VERSION 5.8 ;
BUSBITCHARS "[]" ;
DIVIDERCHAR "/" ;
UNITS
    DATABASE MICRONS 1000 ;
END UNITS

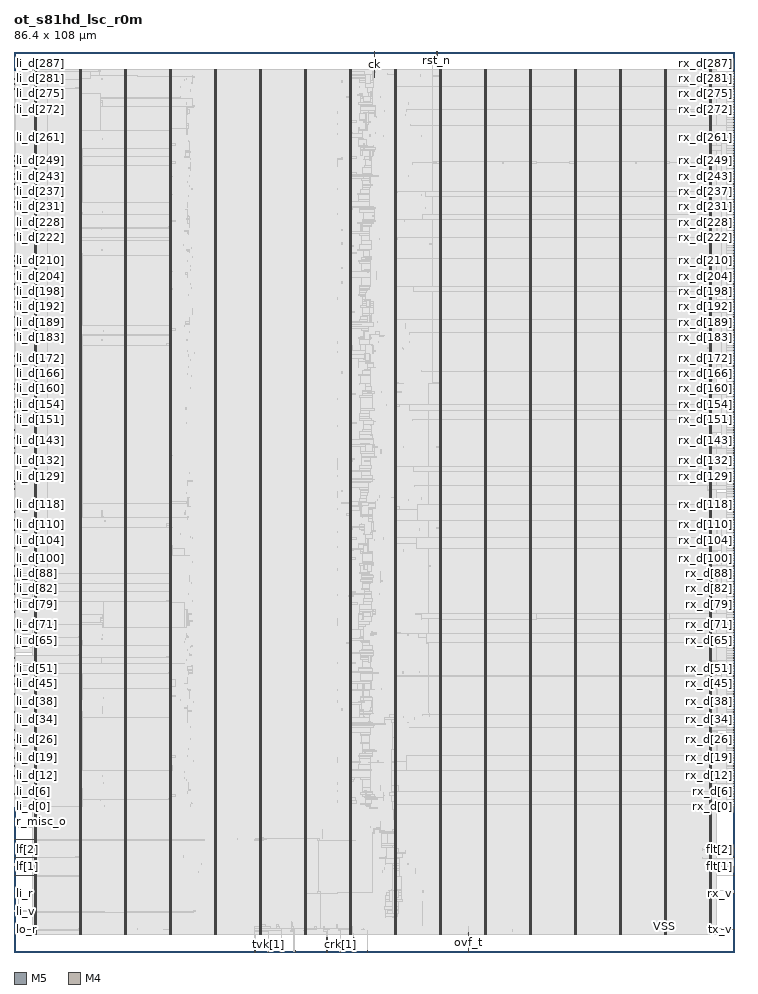
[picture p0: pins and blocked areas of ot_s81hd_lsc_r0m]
MACRO ot_s81hd_lsc_r0m
  FOREIGN ot_s81hd_lsc_r0m 0 0 ;
  CLASS BLOCK ;
  SIZE 86.4 BY 108 ;
  PIN ck
    DIRECTION INPUT ;
    USE SIGNAL ;
    PORT
      LAYER M5 ;
        RECT  43.2 107.916 43.224 108 ;
    END
    PORT
      LAYER M5 ;
        RECT  43.2 104.915 43.224 107.984 ;
    END
  END ck
  PIN crk[0]
    DIRECTION OUTPUT ;
    USE SIGNAL ;
    PORT
      LAYER M5 ;
        RECT  37.536 0 37.56 0.084 ;
    END
    PORT
      LAYER M5 ;
        RECT  37.536 0.016 37.56 1.763 ;
    END
  END crk[0]
  PIN crk[1]
    DIRECTION OUTPUT ;
    USE SIGNAL ;
    PORT
      LAYER M5 ;
        RECT  39.12 0 39.144 0.084 ;
    END
    PORT
      LAYER M5 ;
        RECT  39.12 0.016 39.144 0.131 ;
    END
  END crk[1]
  PIN crk[2]
    DIRECTION OUTPUT ;
    USE SIGNAL ;
    PORT
      LAYER M5 ;
        RECT  40.752 0 40.776 0.084 ;
    END
    PORT
      LAYER M5 ;
        RECT  40.752 0.016 40.776 1.763 ;
    END
  END crk[2]
  PIN crk[3]
    DIRECTION OUTPUT ;
    USE SIGNAL ;
    PORT
      LAYER M5 ;
        RECT  42.384 0 42.408 0.084 ;
    END
    PORT
      LAYER M5 ;
        RECT  42.384 0.016 42.408 0.131 ;
    END
  END crk[3]
  PIN flt[0]
    DIRECTION OUTPUT ;
    USE SIGNAL ;
    PORT
      LAYER M4 ;
        RECT  86.316 9.168 86.4 9.192 ;
    END
    PORT
      LAYER M4 ;
        RECT  86.281 9.168 86.364 9.192 ;
    END
  END flt[0]
  PIN flt[1]
    DIRECTION OUTPUT ;
    USE SIGNAL ;
    PORT
      LAYER M4 ;
        RECT  86.316 10.272 86.4 10.296 ;
    END
    PORT
      LAYER M4 ;
        RECT  86.321 10.272 86.364 10.296 ;
    END
  END flt[1]
  PIN flt[2]
    DIRECTION OUTPUT ;
    USE SIGNAL ;
    PORT
      LAYER M4 ;
        RECT  86.316 11.328 86.4 11.352 ;
    END
    PORT
      LAYER M4 ;
        RECT  86.321 11.328 86.364 11.352 ;
    END
  END flt[2]
  PIN flt[3]
    DIRECTION OUTPUT ;
    USE SIGNAL ;
    PORT
      LAYER M4 ;
        RECT  86.316 12.432 86.4 12.456 ;
    END
    PORT
      LAYER M4 ;
        RECT  83.704 12.432 86.364 12.456 ;
    END
  END flt[3]
  PIN lf[0]
    DIRECTION INPUT ;
    USE SIGNAL ;
    PORT
      LAYER M4 ;
        RECT  0 9.168 0.084 9.192 ;
    END
    PORT
      LAYER M4 ;
        RECT  0.06 9.168 2.408 9.192 ;
    END
  END lf[0]
  PIN lf[1]
    DIRECTION INPUT ;
    USE SIGNAL ;
    PORT
      LAYER M4 ;
        RECT  0 10.272 0.084 10.296 ;
    END
    PORT
      LAYER M4 ;
        RECT  0.06 10.272 0.137 10.296 ;
    END
  END lf[1]
  PIN lf[2]
    DIRECTION INPUT ;
    USE SIGNAL ;
    PORT
      LAYER M4 ;
        RECT  0 11.328 0.084 11.352 ;
    END
    PORT
      LAYER M4 ;
        RECT  0.06 11.328 2.408 11.352 ;
    END
  END lf[2]
  PIN li_d[0]
    DIRECTION INPUT ;
    USE SIGNAL ;
    PORT
      LAYER M4 ;
        RECT  0 17.424 0.084 17.448 ;
    END
  END li_d[0]
  PIN li_d[100]
    DIRECTION INPUT ;
    USE SIGNAL ;
    PORT
      LAYER M4 ;
        RECT  0 48.192 0.084 48.216 ;
    END
  END li_d[100]
  PIN li_d[101]
    DIRECTION INPUT ;
    USE SIGNAL ;
    PORT
      LAYER M4 ;
        RECT  0 48.48 0.084 48.504 ;
    END
  END li_d[101]
  PIN li_d[102]
    DIRECTION INPUT ;
    USE SIGNAL ;
    PORT
      LAYER M4 ;
        RECT  0 48.768 0.084 48.792 ;
    END
  END li_d[102]
  PIN li_d[103]
    DIRECTION INPUT ;
    USE SIGNAL ;
    PORT
      LAYER M4 ;
        RECT  0 49.104 0.084 49.128 ;
    END
  END li_d[103]
  PIN li_d[104]
    DIRECTION INPUT ;
    USE SIGNAL ;
    PORT
      LAYER M4 ;
        RECT  0 49.392 0.084 49.416 ;
    END
  END li_d[104]
  PIN li_d[105]
    DIRECTION INPUT ;
    USE SIGNAL ;
    PORT
      LAYER M4 ;
        RECT  0 49.728 0.084 49.752 ;
    END
  END li_d[105]
  PIN li_d[106]
    DIRECTION INPUT ;
    USE SIGNAL ;
    PORT
      LAYER M4 ;
        RECT  0 50.016 0.084 50.04 ;
    END
  END li_d[106]
  PIN li_d[107]
    DIRECTION INPUT ;
    USE SIGNAL ;
    PORT
      LAYER M4 ;
        RECT  0 50.304 0.084 50.328 ;
    END
  END li_d[107]
  PIN li_d[108]
    DIRECTION INPUT ;
    USE SIGNAL ;
    PORT
      LAYER M4 ;
        RECT  0 50.64 0.084 50.664 ;
    END
  END li_d[108]
  PIN li_d[109]
    DIRECTION INPUT ;
    USE SIGNAL ;
    PORT
      LAYER M4 ;
        RECT  0 50.928 0.084 50.952 ;
    END
  END li_d[109]
  PIN li_d[10]
    DIRECTION INPUT ;
    USE SIGNAL ;
    PORT
      LAYER M4 ;
        RECT  0 20.496 0.084 20.52 ;
    END
  END li_d[10]
  PIN li_d[110]
    DIRECTION INPUT ;
    USE SIGNAL ;
    PORT
      LAYER M4 ;
        RECT  0 51.264 0.084 51.288 ;
    END
  END li_d[110]
  PIN li_d[111]
    DIRECTION INPUT ;
    USE SIGNAL ;
    PORT
      LAYER M4 ;
        RECT  0 51.552 0.084 51.576 ;
    END
  END li_d[111]
  PIN li_d[112]
    DIRECTION INPUT ;
    USE SIGNAL ;
    PORT
      LAYER M4 ;
        RECT  0 51.84 0.084 51.864 ;
    END
  END li_d[112]
  PIN li_d[113]
    DIRECTION INPUT ;
    USE SIGNAL ;
    PORT
      LAYER M4 ;
        RECT  0 52.176 0.084 52.2 ;
    END
  END li_d[113]
  PIN li_d[114]
    DIRECTION INPUT ;
    USE SIGNAL ;
    PORT
      LAYER M4 ;
        RECT  0 52.464 0.084 52.488 ;
    END
  END li_d[114]
  PIN li_d[115]
    DIRECTION INPUT ;
    USE SIGNAL ;
    PORT
      LAYER M4 ;
        RECT  0 52.8 0.084 52.824 ;
    END
  END li_d[115]
  PIN li_d[116]
    DIRECTION INPUT ;
    USE SIGNAL ;
    PORT
      LAYER M4 ;
        RECT  0 53.088 0.084 53.112 ;
    END
  END li_d[116]
  PIN li_d[117]
    DIRECTION INPUT ;
    USE SIGNAL ;
    PORT
      LAYER M4 ;
        RECT  0 53.376 0.084 53.4 ;
    END
  END li_d[117]
  PIN li_d[118]
    DIRECTION INPUT ;
    USE SIGNAL ;
    PORT
      LAYER M4 ;
        RECT  0 53.712 0.084 53.736 ;
    END
  END li_d[118]
  PIN li_d[119]
    DIRECTION INPUT ;
    USE SIGNAL ;
    PORT
      LAYER M4 ;
        RECT  0 54 0.084 54.024 ;
    END
  END li_d[119]
  PIN li_d[11]
    DIRECTION INPUT ;
    USE SIGNAL ;
    PORT
      LAYER M4 ;
        RECT  0 20.784 0.084 20.808 ;
    END
  END li_d[11]
  PIN li_d[120]
    DIRECTION INPUT ;
    USE SIGNAL ;
    PORT
      LAYER M4 ;
        RECT  0 54.336 0.084 54.36 ;
    END
  END li_d[120]
  PIN li_d[121]
    DIRECTION INPUT ;
    USE SIGNAL ;
    PORT
      LAYER M4 ;
        RECT  0 54.624 0.084 54.648 ;
    END
  END li_d[121]
  PIN li_d[122]
    DIRECTION INPUT ;
    USE SIGNAL ;
    PORT
      LAYER M4 ;
        RECT  0 54.96 0.084 54.984 ;
    END
  END li_d[122]
  PIN li_d[123]
    DIRECTION INPUT ;
    USE SIGNAL ;
    PORT
      LAYER M4 ;
        RECT  0 55.248 0.084 55.272 ;
    END
  END li_d[123]
  PIN li_d[124]
    DIRECTION INPUT ;
    USE SIGNAL ;
    PORT
      LAYER M4 ;
        RECT  0 55.536 0.084 55.56 ;
    END
  END li_d[124]
  PIN li_d[125]
    DIRECTION INPUT ;
    USE SIGNAL ;
    PORT
      LAYER M4 ;
        RECT  0 55.872 0.084 55.896 ;
    END
  END li_d[125]
  PIN li_d[126]
    DIRECTION INPUT ;
    USE SIGNAL ;
    PORT
      LAYER M4 ;
        RECT  0 56.16 0.084 56.184 ;
    END
  END li_d[126]
  PIN li_d[127]
    DIRECTION INPUT ;
    USE SIGNAL ;
    PORT
      LAYER M4 ;
        RECT  0 56.496 0.084 56.52 ;
    END
  END li_d[127]
  PIN li_d[128]
    DIRECTION INPUT ;
    USE SIGNAL ;
    PORT
      LAYER M4 ;
        RECT  0 56.784 0.084 56.808 ;
    END
  END li_d[128]
  PIN li_d[129]
    DIRECTION INPUT ;
    USE SIGNAL ;
    PORT
      LAYER M4 ;
        RECT  0 57.072 0.084 57.096 ;
    END
  END li_d[129]
  PIN li_d[12]
    DIRECTION INPUT ;
    USE SIGNAL ;
    PORT
      LAYER M4 ;
        RECT  0 21.12 0.084 21.144 ;
    END
  END li_d[12]
  PIN li_d[130]
    DIRECTION INPUT ;
    USE SIGNAL ;
    PORT
      LAYER M4 ;
        RECT  0 57.408 0.084 57.432 ;
    END
  END li_d[130]
  PIN li_d[131]
    DIRECTION INPUT ;
    USE SIGNAL ;
    PORT
      LAYER M4 ;
        RECT  0 57.696 0.084 57.72 ;
    END
  END li_d[131]
  PIN li_d[132]
    DIRECTION INPUT ;
    USE SIGNAL ;
    PORT
      LAYER M4 ;
        RECT  0 58.032 0.084 58.056 ;
    END
  END li_d[132]
  PIN li_d[133]
    DIRECTION INPUT ;
    USE SIGNAL ;
    PORT
      LAYER M4 ;
        RECT  0 58.32 0.084 58.344 ;
    END
  END li_d[133]
  PIN li_d[134]
    DIRECTION INPUT ;
    USE SIGNAL ;
    PORT
      LAYER M4 ;
        RECT  0 58.608 0.084 58.632 ;
    END
  END li_d[134]
  PIN li_d[135]
    DIRECTION INPUT ;
    USE SIGNAL ;
    PORT
      LAYER M4 ;
        RECT  0 58.944 0.084 58.968 ;
    END
  END li_d[135]
  PIN li_d[136]
    DIRECTION INPUT ;
    USE SIGNAL ;
    PORT
      LAYER M4 ;
        RECT  0 59.232 0.084 59.256 ;
    END
  END li_d[136]
  PIN li_d[137]
    DIRECTION INPUT ;
    USE SIGNAL ;
    PORT
      LAYER M4 ;
        RECT  0 59.568 0.084 59.592 ;
    END
  END li_d[137]
  PIN li_d[138]
    DIRECTION INPUT ;
    USE SIGNAL ;
    PORT
      LAYER M4 ;
        RECT  0 59.856 0.084 59.88 ;
    END
  END li_d[138]
  PIN li_d[139]
    DIRECTION INPUT ;
    USE SIGNAL ;
    PORT
      LAYER M4 ;
        RECT  0 60.144 0.084 60.168 ;
    END
  END li_d[139]
  PIN li_d[13]
    DIRECTION INPUT ;
    USE SIGNAL ;
    PORT
      LAYER M4 ;
        RECT  0 21.408 0.084 21.432 ;
    END
  END li_d[13]
  PIN li_d[140]
    DIRECTION INPUT ;
    USE SIGNAL ;
    PORT
      LAYER M4 ;
        RECT  0 60.48 0.084 60.504 ;
    END
  END li_d[140]
  PIN li_d[141]
    DIRECTION INPUT ;
    USE SIGNAL ;
    PORT
      LAYER M4 ;
        RECT  0 60.768 0.084 60.792 ;
    END
  END li_d[141]
  PIN li_d[142]
    DIRECTION INPUT ;
    USE SIGNAL ;
    PORT
      LAYER M4 ;
        RECT  0 61.104 0.084 61.128 ;
    END
  END li_d[142]
  PIN li_d[143]
    DIRECTION INPUT ;
    USE SIGNAL ;
    PORT
      LAYER M4 ;
        RECT  0 61.392 0.084 61.416 ;
    END
  END li_d[143]
  PIN li_d[144]
    DIRECTION INPUT ;
    USE SIGNAL ;
    PORT
      LAYER M4 ;
        RECT  0 61.68 0.084 61.704 ;
    END
  END li_d[144]
  PIN li_d[145]
    DIRECTION INPUT ;
    USE SIGNAL ;
    PORT
      LAYER M4 ;
        RECT  0 62.016 0.084 62.04 ;
    END
  END li_d[145]
  PIN li_d[146]
    DIRECTION INPUT ;
    USE SIGNAL ;
    PORT
      LAYER M4 ;
        RECT  0 62.304 0.084 62.328 ;
    END
  END li_d[146]
  PIN li_d[147]
    DIRECTION INPUT ;
    USE SIGNAL ;
    PORT
      LAYER M4 ;
        RECT  0 62.64 0.084 62.664 ;
    END
  END li_d[147]
  PIN li_d[148]
    DIRECTION INPUT ;
    USE SIGNAL ;
    PORT
      LAYER M4 ;
        RECT  0 62.928 0.084 62.952 ;
    END
  END li_d[148]
  PIN li_d[149]
    DIRECTION INPUT ;
    USE SIGNAL ;
    PORT
      LAYER M4 ;
        RECT  0 63.216 0.084 63.24 ;
    END
  END li_d[149]
  PIN li_d[14]
    DIRECTION INPUT ;
    USE SIGNAL ;
    PORT
      LAYER M4 ;
        RECT  0 21.744 0.084 21.768 ;
    END
  END li_d[14]
  PIN li_d[150]
    DIRECTION INPUT ;
    USE SIGNAL ;
    PORT
      LAYER M4 ;
        RECT  0 63.552 0.084 63.576 ;
    END
  END li_d[150]
  PIN li_d[151]
    DIRECTION INPUT ;
    USE SIGNAL ;
    PORT
      LAYER M4 ;
        RECT  0 63.84 0.084 63.864 ;
    END
  END li_d[151]
  PIN li_d[152]
    DIRECTION INPUT ;
    USE SIGNAL ;
    PORT
      LAYER M4 ;
        RECT  0 64.176 0.084 64.2 ;
    END
  END li_d[152]
  PIN li_d[153]
    DIRECTION INPUT ;
    USE SIGNAL ;
    PORT
      LAYER M4 ;
        RECT  0 64.464 0.084 64.488 ;
    END
  END li_d[153]
  PIN li_d[154]
    DIRECTION INPUT ;
    USE SIGNAL ;
    PORT
      LAYER M4 ;
        RECT  0 64.8 0.084 64.824 ;
    END
  END li_d[154]
  PIN li_d[155]
    DIRECTION INPUT ;
    USE SIGNAL ;
    PORT
      LAYER M4 ;
        RECT  0 65.088 0.084 65.112 ;
    END
  END li_d[155]
  PIN li_d[156]
    DIRECTION INPUT ;
    USE SIGNAL ;
    PORT
      LAYER M4 ;
        RECT  0 65.376 0.084 65.4 ;
    END
  END li_d[156]
  PIN li_d[157]
    DIRECTION INPUT ;
    USE SIGNAL ;
    PORT
      LAYER M4 ;
        RECT  0 65.712 0.084 65.736 ;
    END
  END li_d[157]
  PIN li_d[158]
    DIRECTION INPUT ;
    USE SIGNAL ;
    PORT
      LAYER M4 ;
        RECT  0 66 0.084 66.024 ;
    END
  END li_d[158]
  PIN li_d[159]
    DIRECTION INPUT ;
    USE SIGNAL ;
    PORT
      LAYER M4 ;
        RECT  0 66.336 0.084 66.36 ;
    END
  END li_d[159]
  PIN li_d[15]
    DIRECTION INPUT ;
    USE SIGNAL ;
    PORT
      LAYER M4 ;
        RECT  0 22.032 0.084 22.056 ;
    END
  END li_d[15]
  PIN li_d[160]
    DIRECTION INPUT ;
    USE SIGNAL ;
    PORT
      LAYER M4 ;
        RECT  0 66.624 0.084 66.648 ;
    END
  END li_d[160]
  PIN li_d[161]
    DIRECTION INPUT ;
    USE SIGNAL ;
    PORT
      LAYER M4 ;
        RECT  0 66.912 0.084 66.936 ;
    END
  END li_d[161]
  PIN li_d[162]
    DIRECTION INPUT ;
    USE SIGNAL ;
    PORT
      LAYER M4 ;
        RECT  0 67.248 0.084 67.272 ;
    END
  END li_d[162]
  PIN li_d[163]
    DIRECTION INPUT ;
    USE SIGNAL ;
    PORT
      LAYER M4 ;
        RECT  0 67.536 0.084 67.56 ;
    END
  END li_d[163]
  PIN li_d[164]
    DIRECTION INPUT ;
    USE SIGNAL ;
    PORT
      LAYER M4 ;
        RECT  0 67.872 0.084 67.896 ;
    END
  END li_d[164]
  PIN li_d[165]
    DIRECTION INPUT ;
    USE SIGNAL ;
    PORT
      LAYER M4 ;
        RECT  0 68.16 0.084 68.184 ;
    END
  END li_d[165]
  PIN li_d[166]
    DIRECTION INPUT ;
    USE SIGNAL ;
    PORT
      LAYER M4 ;
        RECT  0 68.448 0.084 68.472 ;
    END
  END li_d[166]
  PIN li_d[167]
    DIRECTION INPUT ;
    USE SIGNAL ;
    PORT
      LAYER M4 ;
        RECT  0 68.784 0.084 68.808 ;
    END
  END li_d[167]
  PIN li_d[168]
    DIRECTION INPUT ;
    USE SIGNAL ;
    PORT
      LAYER M4 ;
        RECT  0 69.072 0.084 69.096 ;
    END
  END li_d[168]
  PIN li_d[169]
    DIRECTION INPUT ;
    USE SIGNAL ;
    PORT
      LAYER M4 ;
        RECT  0 69.408 0.084 69.432 ;
    END
  END li_d[169]
  PIN li_d[16]
    DIRECTION INPUT ;
    USE SIGNAL ;
    PORT
      LAYER M4 ;
        RECT  0 22.32 0.084 22.344 ;
    END
  END li_d[16]
  PIN li_d[170]
    DIRECTION INPUT ;
    USE SIGNAL ;
    PORT
      LAYER M4 ;
        RECT  0 69.696 0.084 69.72 ;
    END
  END li_d[170]
  PIN li_d[171]
    DIRECTION INPUT ;
    USE SIGNAL ;
    PORT
      LAYER M4 ;
        RECT  0 69.984 0.084 70.008 ;
    END
  END li_d[171]
  PIN li_d[172]
    DIRECTION INPUT ;
    USE SIGNAL ;
    PORT
      LAYER M4 ;
        RECT  0 70.32 0.084 70.344 ;
    END
  END li_d[172]
  PIN li_d[173]
    DIRECTION INPUT ;
    USE SIGNAL ;
    PORT
      LAYER M4 ;
        RECT  0 70.608 0.084 70.632 ;
    END
  END li_d[173]
  PIN li_d[174]
    DIRECTION INPUT ;
    USE SIGNAL ;
    PORT
      LAYER M4 ;
        RECT  0 70.944 0.084 70.968 ;
    END
  END li_d[174]
  PIN li_d[175]
    DIRECTION INPUT ;
    USE SIGNAL ;
    PORT
      LAYER M4 ;
        RECT  0 71.232 0.084 71.256 ;
    END
  END li_d[175]
  PIN li_d[176]
    DIRECTION INPUT ;
    USE SIGNAL ;
    PORT
      LAYER M4 ;
        RECT  0 71.52 0.084 71.544 ;
    END
  END li_d[176]
  PIN li_d[177]
    DIRECTION INPUT ;
    USE SIGNAL ;
    PORT
      LAYER M4 ;
        RECT  0 71.856 0.084 71.88 ;
    END
  END li_d[177]
  PIN li_d[178]
    DIRECTION INPUT ;
    USE SIGNAL ;
    PORT
      LAYER M4 ;
        RECT  0 72.144 0.084 72.168 ;
    END
  END li_d[178]
  PIN li_d[179]
    DIRECTION INPUT ;
    USE SIGNAL ;
    PORT
      LAYER M4 ;
        RECT  0 72.48 0.084 72.504 ;
    END
  END li_d[179]
  PIN li_d[17]
    DIRECTION INPUT ;
    USE SIGNAL ;
    PORT
      LAYER M4 ;
        RECT  0 22.656 0.084 22.68 ;
    END
  END li_d[17]
  PIN li_d[180]
    DIRECTION INPUT ;
    USE SIGNAL ;
    PORT
      LAYER M4 ;
        RECT  0 72.768 0.084 72.792 ;
    END
  END li_d[180]
  PIN li_d[181]
    DIRECTION INPUT ;
    USE SIGNAL ;
    PORT
      LAYER M4 ;
        RECT  0 73.056 0.084 73.08 ;
    END
  END li_d[181]
  PIN li_d[182]
    DIRECTION INPUT ;
    USE SIGNAL ;
    PORT
      LAYER M4 ;
        RECT  0 73.392 0.084 73.416 ;
    END
  END li_d[182]
  PIN li_d[183]
    DIRECTION INPUT ;
    USE SIGNAL ;
    PORT
      LAYER M4 ;
        RECT  0 73.68 0.084 73.704 ;
    END
  END li_d[183]
  PIN li_d[184]
    DIRECTION INPUT ;
    USE SIGNAL ;
    PORT
      LAYER M4 ;
        RECT  0 74.016 0.084 74.04 ;
    END
  END li_d[184]
  PIN li_d[185]
    DIRECTION INPUT ;
    USE SIGNAL ;
    PORT
      LAYER M4 ;
        RECT  0 74.304 0.084 74.328 ;
    END
  END li_d[185]
  PIN li_d[186]
    DIRECTION INPUT ;
    USE SIGNAL ;
    PORT
      LAYER M4 ;
        RECT  0 74.64 0.084 74.664 ;
    END
  END li_d[186]
  PIN li_d[187]
    DIRECTION INPUT ;
    USE SIGNAL ;
    PORT
      LAYER M4 ;
        RECT  0 74.928 0.084 74.952 ;
    END
  END li_d[187]
  PIN li_d[188]
    DIRECTION INPUT ;
    USE SIGNAL ;
    PORT
      LAYER M4 ;
        RECT  0 75.216 0.084 75.24 ;
    END
  END li_d[188]
  PIN li_d[189]
    DIRECTION INPUT ;
    USE SIGNAL ;
    PORT
      LAYER M4 ;
        RECT  0 75.552 0.084 75.576 ;
    END
  END li_d[189]
  PIN li_d[18]
    DIRECTION INPUT ;
    USE SIGNAL ;
    PORT
      LAYER M4 ;
        RECT  0 22.944 0.084 22.968 ;
    END
  END li_d[18]
  PIN li_d[190]
    DIRECTION INPUT ;
    USE SIGNAL ;
    PORT
      LAYER M4 ;
        RECT  0 75.84 0.084 75.864 ;
    END
  END li_d[190]
  PIN li_d[191]
    DIRECTION INPUT ;
    USE SIGNAL ;
    PORT
      LAYER M4 ;
        RECT  0 76.176 0.084 76.2 ;
    END
  END li_d[191]
  PIN li_d[192]
    DIRECTION INPUT ;
    USE SIGNAL ;
    PORT
      LAYER M4 ;
        RECT  0 76.464 0.084 76.488 ;
    END
  END li_d[192]
  PIN li_d[193]
    DIRECTION INPUT ;
    USE SIGNAL ;
    PORT
      LAYER M4 ;
        RECT  0 76.752 0.084 76.776 ;
    END
  END li_d[193]
  PIN li_d[194]
    DIRECTION INPUT ;
    USE SIGNAL ;
    PORT
      LAYER M4 ;
        RECT  0 77.088 0.084 77.112 ;
    END
  END li_d[194]
  PIN li_d[195]
    DIRECTION INPUT ;
    USE SIGNAL ;
    PORT
      LAYER M4 ;
        RECT  0 77.376 0.084 77.4 ;
    END
  END li_d[195]
  PIN li_d[196]
    DIRECTION INPUT ;
    USE SIGNAL ;
    PORT
      LAYER M4 ;
        RECT  0 77.712 0.084 77.736 ;
    END
  END li_d[196]
  PIN li_d[197]
    DIRECTION INPUT ;
    USE SIGNAL ;
    PORT
      LAYER M4 ;
        RECT  0 78 0.084 78.024 ;
    END
  END li_d[197]
  PIN li_d[198]
    DIRECTION INPUT ;
    USE SIGNAL ;
    PORT
      LAYER M4 ;
        RECT  0 78.288 0.084 78.312 ;
    END
  END li_d[198]
  PIN li_d[199]
    DIRECTION INPUT ;
    USE SIGNAL ;
    PORT
      LAYER M4 ;
        RECT  0 78.624 0.084 78.648 ;
    END
  END li_d[199]
  PIN li_d[19]
    DIRECTION INPUT ;
    USE SIGNAL ;
    PORT
      LAYER M4 ;
        RECT  0 23.28 0.084 23.304 ;
    END
  END li_d[19]
  PIN li_d[1]
    DIRECTION INPUT ;
    USE SIGNAL ;
    PORT
      LAYER M4 ;
        RECT  0 17.712 0.084 17.736 ;
    END
  END li_d[1]
  PIN li_d[200]
    DIRECTION INPUT ;
    USE SIGNAL ;
    PORT
      LAYER M4 ;
        RECT  0 78.912 0.084 78.936 ;
    END
  END li_d[200]
  PIN li_d[201]
    DIRECTION INPUT ;
    USE SIGNAL ;
    PORT
      LAYER M4 ;
        RECT  0 79.248 0.084 79.272 ;
    END
  END li_d[201]
  PIN li_d[202]
    DIRECTION INPUT ;
    USE SIGNAL ;
    PORT
      LAYER M4 ;
        RECT  0 79.536 0.084 79.56 ;
    END
  END li_d[202]
  PIN li_d[203]
    DIRECTION INPUT ;
    USE SIGNAL ;
    PORT
      LAYER M4 ;
        RECT  0 79.824 0.084 79.848 ;
    END
  END li_d[203]
  PIN li_d[204]
    DIRECTION INPUT ;
    USE SIGNAL ;
    PORT
      LAYER M4 ;
        RECT  0 80.16 0.084 80.184 ;
    END
  END li_d[204]
  PIN li_d[205]
    DIRECTION INPUT ;
    USE SIGNAL ;
    PORT
      LAYER M4 ;
        RECT  0 80.448 0.084 80.472 ;
    END
  END li_d[205]
  PIN li_d[206]
    DIRECTION INPUT ;
    USE SIGNAL ;
    PORT
      LAYER M4 ;
        RECT  0 80.784 0.084 80.808 ;
    END
  END li_d[206]
  PIN li_d[207]
    DIRECTION INPUT ;
    USE SIGNAL ;
    PORT
      LAYER M4 ;
        RECT  0 81.072 0.084 81.096 ;
    END
  END li_d[207]
  PIN li_d[208]
    DIRECTION INPUT ;
    USE SIGNAL ;
    PORT
      LAYER M4 ;
        RECT  0 81.36 0.084 81.384 ;
    END
  END li_d[208]
  PIN li_d[209]
    DIRECTION INPUT ;
    USE SIGNAL ;
    PORT
      LAYER M4 ;
        RECT  0 81.696 0.084 81.72 ;
    END
  END li_d[209]
  PIN li_d[20]
    DIRECTION INPUT ;
    USE SIGNAL ;
    PORT
      LAYER M4 ;
        RECT  0 23.568 0.084 23.592 ;
    END
  END li_d[20]
  PIN li_d[210]
    DIRECTION INPUT ;
    USE SIGNAL ;
    PORT
      LAYER M4 ;
        RECT  0 81.984 0.084 82.008 ;
    END
  END li_d[210]
  PIN li_d[211]
    DIRECTION INPUT ;
    USE SIGNAL ;
    PORT
      LAYER M4 ;
        RECT  0 82.32 0.084 82.344 ;
    END
  END li_d[211]
  PIN li_d[212]
    DIRECTION INPUT ;
    USE SIGNAL ;
    PORT
      LAYER M4 ;
        RECT  0 82.608 0.084 82.632 ;
    END
  END li_d[212]
  PIN li_d[213]
    DIRECTION INPUT ;
    USE SIGNAL ;
    PORT
      LAYER M4 ;
        RECT  0 82.896 0.084 82.92 ;
    END
  END li_d[213]
  PIN li_d[214]
    DIRECTION INPUT ;
    USE SIGNAL ;
    PORT
      LAYER M4 ;
        RECT  0 83.232 0.084 83.256 ;
    END
  END li_d[214]
  PIN li_d[215]
    DIRECTION INPUT ;
    USE SIGNAL ;
    PORT
      LAYER M4 ;
        RECT  0 83.52 0.084 83.544 ;
    END
  END li_d[215]
  PIN li_d[216]
    DIRECTION INPUT ;
    USE SIGNAL ;
    PORT
      LAYER M4 ;
        RECT  0 83.856 0.084 83.88 ;
    END
  END li_d[216]
  PIN li_d[217]
    DIRECTION INPUT ;
    USE SIGNAL ;
    PORT
      LAYER M4 ;
        RECT  0 84.144 0.084 84.168 ;
    END
  END li_d[217]
  PIN li_d[218]
    DIRECTION INPUT ;
    USE SIGNAL ;
    PORT
      LAYER M4 ;
        RECT  0 84.48 0.084 84.504 ;
    END
  END li_d[218]
  PIN li_d[219]
    DIRECTION INPUT ;
    USE SIGNAL ;
    PORT
      LAYER M4 ;
        RECT  0 84.768 0.084 84.792 ;
    END
  END li_d[219]
  PIN li_d[21]
    DIRECTION INPUT ;
    USE SIGNAL ;
    PORT
      LAYER M4 ;
        RECT  0 23.856 0.084 23.88 ;
    END
  END li_d[21]
  PIN li_d[220]
    DIRECTION INPUT ;
    USE SIGNAL ;
    PORT
      LAYER M4 ;
        RECT  0 85.056 0.084 85.08 ;
    END
  END li_d[220]
  PIN li_d[221]
    DIRECTION INPUT ;
    USE SIGNAL ;
    PORT
      LAYER M4 ;
        RECT  0 85.392 0.084 85.416 ;
    END
  END li_d[221]
  PIN li_d[222]
    DIRECTION INPUT ;
    USE SIGNAL ;
    PORT
      LAYER M4 ;
        RECT  0 85.68 0.084 85.704 ;
    END
  END li_d[222]
  PIN li_d[223]
    DIRECTION INPUT ;
    USE SIGNAL ;
    PORT
      LAYER M4 ;
        RECT  0 86.016 0.084 86.04 ;
    END
  END li_d[223]
  PIN li_d[224]
    DIRECTION INPUT ;
    USE SIGNAL ;
    PORT
      LAYER M4 ;
        RECT  0 86.304 0.084 86.328 ;
    END
  END li_d[224]
  PIN li_d[225]
    DIRECTION INPUT ;
    USE SIGNAL ;
    PORT
      LAYER M4 ;
        RECT  0 86.592 0.084 86.616 ;
    END
  END li_d[225]
  PIN li_d[226]
    DIRECTION INPUT ;
    USE SIGNAL ;
    PORT
      LAYER M4 ;
        RECT  0 86.928 0.084 86.952 ;
    END
  END li_d[226]
  PIN li_d[227]
    DIRECTION INPUT ;
    USE SIGNAL ;
    PORT
      LAYER M4 ;
        RECT  0 87.216 0.084 87.24 ;
    END
  END li_d[227]
  PIN li_d[228]
    DIRECTION INPUT ;
    USE SIGNAL ;
    PORT
      LAYER M4 ;
        RECT  0 87.552 0.084 87.576 ;
    END
  END li_d[228]
  PIN li_d[229]
    DIRECTION INPUT ;
    USE SIGNAL ;
    PORT
      LAYER M4 ;
        RECT  0 87.84 0.084 87.864 ;
    END
  END li_d[229]
  PIN li_d[22]
    DIRECTION INPUT ;
    USE SIGNAL ;
    PORT
      LAYER M4 ;
        RECT  0 24.192 0.084 24.216 ;
    END
  END li_d[22]
  PIN li_d[230]
    DIRECTION INPUT ;
    USE SIGNAL ;
    PORT
      LAYER M4 ;
        RECT  0 88.128 0.084 88.152 ;
    END
  END li_d[230]
  PIN li_d[231]
    DIRECTION INPUT ;
    USE SIGNAL ;
    PORT
      LAYER M4 ;
        RECT  0 88.464 0.084 88.488 ;
    END
  END li_d[231]
  PIN li_d[232]
    DIRECTION INPUT ;
    USE SIGNAL ;
    PORT
      LAYER M4 ;
        RECT  0 88.752 0.084 88.776 ;
    END
  END li_d[232]
  PIN li_d[233]
    DIRECTION INPUT ;
    USE SIGNAL ;
    PORT
      LAYER M4 ;
        RECT  0 89.088 0.084 89.112 ;
    END
  END li_d[233]
  PIN li_d[234]
    DIRECTION INPUT ;
    USE SIGNAL ;
    PORT
      LAYER M4 ;
        RECT  0 89.376 0.084 89.4 ;
    END
  END li_d[234]
  PIN li_d[235]
    DIRECTION INPUT ;
    USE SIGNAL ;
    PORT
      LAYER M4 ;
        RECT  0 89.664 0.084 89.688 ;
    END
  END li_d[235]
  PIN li_d[236]
    DIRECTION INPUT ;
    USE SIGNAL ;
    PORT
      LAYER M4 ;
        RECT  0 90 0.084 90.024 ;
    END
  END li_d[236]
  PIN li_d[237]
    DIRECTION INPUT ;
    USE SIGNAL ;
    PORT
      LAYER M4 ;
        RECT  0 90.288 0.084 90.312 ;
    END
  END li_d[237]
  PIN li_d[238]
    DIRECTION INPUT ;
    USE SIGNAL ;
    PORT
      LAYER M4 ;
        RECT  0 90.624 0.084 90.648 ;
    END
  END li_d[238]
  PIN li_d[239]
    DIRECTION INPUT ;
    USE SIGNAL ;
    PORT
      LAYER M4 ;
        RECT  0 90.912 0.084 90.936 ;
    END
  END li_d[239]
  PIN li_d[23]
    DIRECTION INPUT ;
    USE SIGNAL ;
    PORT
      LAYER M4 ;
        RECT  0 24.48 0.084 24.504 ;
    END
  END li_d[23]
  PIN li_d[240]
    DIRECTION INPUT ;
    USE SIGNAL ;
    PORT
      LAYER M4 ;
        RECT  0 91.2 0.084 91.224 ;
    END
  END li_d[240]
  PIN li_d[241]
    DIRECTION INPUT ;
    USE SIGNAL ;
    PORT
      LAYER M4 ;
        RECT  0 91.536 0.084 91.56 ;
    END
  END li_d[241]
  PIN li_d[242]
    DIRECTION INPUT ;
    USE SIGNAL ;
    PORT
      LAYER M4 ;
        RECT  0 91.824 0.084 91.848 ;
    END
  END li_d[242]
  PIN li_d[243]
    DIRECTION INPUT ;
    USE SIGNAL ;
    PORT
      LAYER M4 ;
        RECT  0 92.16 0.084 92.184 ;
    END
  END li_d[243]
  PIN li_d[244]
    DIRECTION INPUT ;
    USE SIGNAL ;
    PORT
      LAYER M4 ;
        RECT  0 92.448 0.084 92.472 ;
    END
  END li_d[244]
  PIN li_d[245]
    DIRECTION INPUT ;
    USE SIGNAL ;
    PORT
      LAYER M4 ;
        RECT  0 92.736 0.084 92.76 ;
    END
  END li_d[245]
  PIN li_d[246]
    DIRECTION INPUT ;
    USE SIGNAL ;
    PORT
      LAYER M4 ;
        RECT  0 93.072 0.084 93.096 ;
    END
  END li_d[246]
  PIN li_d[247]
    DIRECTION INPUT ;
    USE SIGNAL ;
    PORT
      LAYER M4 ;
        RECT  0 93.36 0.084 93.384 ;
    END
  END li_d[247]
  PIN li_d[248]
    DIRECTION INPUT ;
    USE SIGNAL ;
    PORT
      LAYER M4 ;
        RECT  0 93.696 0.084 93.72 ;
    END
  END li_d[248]
  PIN li_d[249]
    DIRECTION INPUT ;
    USE SIGNAL ;
    PORT
      LAYER M4 ;
        RECT  0 93.984 0.084 94.008 ;
    END
  END li_d[249]
  PIN li_d[24]
    DIRECTION INPUT ;
    USE SIGNAL ;
    PORT
      LAYER M4 ;
        RECT  0 24.816 0.084 24.84 ;
    END
  END li_d[24]
  PIN li_d[250]
    DIRECTION INPUT ;
    USE SIGNAL ;
    PORT
      LAYER M4 ;
        RECT  0 94.32 0.084 94.344 ;
    END
  END li_d[250]
  PIN li_d[251]
    DIRECTION INPUT ;
    USE SIGNAL ;
    PORT
      LAYER M4 ;
        RECT  0 94.608 0.084 94.632 ;
    END
  END li_d[251]
  PIN li_d[252]
    DIRECTION INPUT ;
    USE SIGNAL ;
    PORT
      LAYER M4 ;
        RECT  0 94.896 0.084 94.92 ;
    END
  END li_d[252]
  PIN li_d[253]
    DIRECTION INPUT ;
    USE SIGNAL ;
    PORT
      LAYER M4 ;
        RECT  0 95.232 0.084 95.256 ;
    END
  END li_d[253]
  PIN li_d[254]
    DIRECTION INPUT ;
    USE SIGNAL ;
    PORT
      LAYER M4 ;
        RECT  0 95.52 0.084 95.544 ;
    END
  END li_d[254]
  PIN li_d[255]
    DIRECTION INPUT ;
    USE SIGNAL ;
    PORT
      LAYER M4 ;
        RECT  0 95.856 0.084 95.88 ;
    END
  END li_d[255]
  PIN li_d[256]
    DIRECTION INPUT ;
    USE SIGNAL ;
    PORT
      LAYER M4 ;
        RECT  0 96.144 0.084 96.168 ;
    END
  END li_d[256]
  PIN li_d[257]
    DIRECTION INPUT ;
    USE SIGNAL ;
    PORT
      LAYER M4 ;
        RECT  0 96.432 0.084 96.456 ;
    END
  END li_d[257]
  PIN li_d[258]
    DIRECTION INPUT ;
    USE SIGNAL ;
    PORT
      LAYER M4 ;
        RECT  0 96.768 0.084 96.792 ;
    END
  END li_d[258]
  PIN li_d[259]
    DIRECTION INPUT ;
    USE SIGNAL ;
    PORT
      LAYER M4 ;
        RECT  0 97.056 0.084 97.08 ;
    END
  END li_d[259]
  PIN li_d[25]
    DIRECTION INPUT ;
    USE SIGNAL ;
    PORT
      LAYER M4 ;
        RECT  0 25.104 0.084 25.128 ;
    END
  END li_d[25]
  PIN li_d[260]
    DIRECTION INPUT ;
    USE SIGNAL ;
    PORT
      LAYER M4 ;
        RECT  0 97.392 0.084 97.416 ;
    END
  END li_d[260]
  PIN li_d[261]
    DIRECTION INPUT ;
    USE SIGNAL ;
    PORT
      LAYER M4 ;
        RECT  0 97.68 0.084 97.704 ;
    END
  END li_d[261]
  PIN li_d[262]
    DIRECTION INPUT ;
    USE SIGNAL ;
    PORT
      LAYER M4 ;
        RECT  0 97.968 0.084 97.992 ;
    END
  END li_d[262]
  PIN li_d[263]
    DIRECTION INPUT ;
    USE SIGNAL ;
    PORT
      LAYER M4 ;
        RECT  0 98.304 0.084 98.328 ;
    END
  END li_d[263]
  PIN li_d[264]
    DIRECTION INPUT ;
    USE SIGNAL ;
    PORT
      LAYER M4 ;
        RECT  0 98.592 0.084 98.616 ;
    END
  END li_d[264]
  PIN li_d[265]
    DIRECTION INPUT ;
    USE SIGNAL ;
    PORT
      LAYER M4 ;
        RECT  0 98.928 0.084 98.952 ;
    END
  END li_d[265]
  PIN li_d[266]
    DIRECTION INPUT ;
    USE SIGNAL ;
    PORT
      LAYER M4 ;
        RECT  0 99.216 0.084 99.24 ;
    END
  END li_d[266]
  PIN li_d[267]
    DIRECTION INPUT ;
    USE SIGNAL ;
    PORT
      LAYER M4 ;
        RECT  0 99.504 0.084 99.528 ;
    END
  END li_d[267]
  PIN li_d[268]
    DIRECTION INPUT ;
    USE SIGNAL ;
    PORT
      LAYER M4 ;
        RECT  0 99.84 0.084 99.864 ;
    END
  END li_d[268]
  PIN li_d[269]
    DIRECTION INPUT ;
    USE SIGNAL ;
    PORT
      LAYER M4 ;
        RECT  0 100.128 0.084 100.152 ;
    END
  END li_d[269]
  PIN li_d[26]
    DIRECTION INPUT ;
    USE SIGNAL ;
    PORT
      LAYER M4 ;
        RECT  0 25.44 0.084 25.464 ;
    END
  END li_d[26]
  PIN li_d[270]
    DIRECTION INPUT ;
    USE SIGNAL ;
    PORT
      LAYER M4 ;
        RECT  0 100.464 0.084 100.488 ;
    END
  END li_d[270]
  PIN li_d[271]
    DIRECTION INPUT ;
    USE SIGNAL ;
    PORT
      LAYER M4 ;
        RECT  0 100.752 0.084 100.776 ;
    END
  END li_d[271]
  PIN li_d[272]
    DIRECTION INPUT ;
    USE SIGNAL ;
    PORT
      LAYER M4 ;
        RECT  0 101.04 0.084 101.064 ;
    END
  END li_d[272]
  PIN li_d[273]
    DIRECTION INPUT ;
    USE SIGNAL ;
    PORT
      LAYER M4 ;
        RECT  0 101.376 0.084 101.4 ;
    END
  END li_d[273]
  PIN li_d[274]
    DIRECTION INPUT ;
    USE SIGNAL ;
    PORT
      LAYER M4 ;
        RECT  0 101.664 0.084 101.688 ;
    END
  END li_d[274]
  PIN li_d[275]
    DIRECTION INPUT ;
    USE SIGNAL ;
    PORT
      LAYER M4 ;
        RECT  0 102 0.084 102.024 ;
    END
  END li_d[275]
  PIN li_d[276]
    DIRECTION INPUT ;
    USE SIGNAL ;
    PORT
      LAYER M4 ;
        RECT  0 102.288 0.084 102.312 ;
    END
  END li_d[276]
  PIN li_d[277]
    DIRECTION INPUT ;
    USE SIGNAL ;
    PORT
      LAYER M4 ;
        RECT  0 102.576 0.084 102.6 ;
    END
  END li_d[277]
  PIN li_d[278]
    DIRECTION INPUT ;
    USE SIGNAL ;
    PORT
      LAYER M4 ;
        RECT  0 102.912 0.084 102.936 ;
    END
  END li_d[278]
  PIN li_d[279]
    DIRECTION INPUT ;
    USE SIGNAL ;
    PORT
      LAYER M4 ;
        RECT  0 103.2 0.084 103.224 ;
    END
  END li_d[279]
  PIN li_d[27]
    DIRECTION INPUT ;
    USE SIGNAL ;
    PORT
      LAYER M4 ;
        RECT  0 25.728 0.084 25.752 ;
    END
  END li_d[27]
  PIN li_d[280]
    DIRECTION INPUT ;
    USE SIGNAL ;
    PORT
      LAYER M4 ;
        RECT  0 103.536 0.084 103.56 ;
    END
  END li_d[280]
  PIN li_d[281]
    DIRECTION INPUT ;
    USE SIGNAL ;
    PORT
      LAYER M4 ;
        RECT  0 103.824 0.084 103.848 ;
    END
  END li_d[281]
  PIN li_d[282]
    DIRECTION INPUT ;
    USE SIGNAL ;
    PORT
      LAYER M4 ;
        RECT  0 104.16 0.084 104.184 ;
    END
  END li_d[282]
  PIN li_d[283]
    DIRECTION INPUT ;
    USE SIGNAL ;
    PORT
      LAYER M4 ;
        RECT  0 104.448 0.084 104.472 ;
    END
  END li_d[283]
  PIN li_d[284]
    DIRECTION INPUT ;
    USE SIGNAL ;
    PORT
      LAYER M4 ;
        RECT  0 104.736 0.084 104.76 ;
    END
  END li_d[284]
  PIN li_d[285]
    DIRECTION INPUT ;
    USE SIGNAL ;
    PORT
      LAYER M4 ;
        RECT  0 105.072 0.084 105.096 ;
    END
  END li_d[285]
  PIN li_d[286]
    DIRECTION INPUT ;
    USE SIGNAL ;
    PORT
      LAYER M4 ;
        RECT  0 105.36 0.084 105.384 ;
    END
  END li_d[286]
  PIN li_d[287]
    DIRECTION INPUT ;
    USE SIGNAL ;
    PORT
      LAYER M4 ;
        RECT  0 105.696 0.084 105.72 ;
    END
  END li_d[287]
  PIN li_d[28]
    DIRECTION INPUT ;
    USE SIGNAL ;
    PORT
      LAYER M4 ;
        RECT  0 26.016 0.084 26.04 ;
    END
  END li_d[28]
  PIN li_d[29]
    DIRECTION INPUT ;
    USE SIGNAL ;
    PORT
      LAYER M4 ;
        RECT  0 26.352 0.084 26.376 ;
    END
  END li_d[29]
  PIN li_d[2]
    DIRECTION INPUT ;
    USE SIGNAL ;
    PORT
      LAYER M4 ;
        RECT  0 18.048 0.084 18.072 ;
    END
  END li_d[2]
  PIN li_d[30]
    DIRECTION INPUT ;
    USE SIGNAL ;
    PORT
      LAYER M4 ;
        RECT  0 26.64 0.084 26.664 ;
    END
  END li_d[30]
  PIN li_d[31]
    DIRECTION INPUT ;
    USE SIGNAL ;
    PORT
      LAYER M4 ;
        RECT  0 26.976 0.084 27 ;
    END
  END li_d[31]
  PIN li_d[32]
    DIRECTION INPUT ;
    USE SIGNAL ;
    PORT
      LAYER M4 ;
        RECT  0 27.264 0.084 27.288 ;
    END
  END li_d[32]
  PIN li_d[33]
    DIRECTION INPUT ;
    USE SIGNAL ;
    PORT
      LAYER M4 ;
        RECT  0 27.552 0.084 27.576 ;
    END
  END li_d[33]
  PIN li_d[34]
    DIRECTION INPUT ;
    USE SIGNAL ;
    PORT
      LAYER M4 ;
        RECT  0 27.888 0.084 27.912 ;
    END
  END li_d[34]
  PIN li_d[35]
    DIRECTION INPUT ;
    USE SIGNAL ;
    PORT
      LAYER M4 ;
        RECT  0 28.176 0.084 28.2 ;
    END
  END li_d[35]
  PIN li_d[36]
    DIRECTION INPUT ;
    USE SIGNAL ;
    PORT
      LAYER M4 ;
        RECT  0 28.512 0.084 28.536 ;
    END
  END li_d[36]
  PIN li_d[37]
    DIRECTION INPUT ;
    USE SIGNAL ;
    PORT
      LAYER M4 ;
        RECT  0 28.8 0.084 28.824 ;
    END
  END li_d[37]
  PIN li_d[38]
    DIRECTION INPUT ;
    USE SIGNAL ;
    PORT
      LAYER M4 ;
        RECT  0 29.088 0.084 29.112 ;
    END
  END li_d[38]
  PIN li_d[39]
    DIRECTION INPUT ;
    USE SIGNAL ;
    PORT
      LAYER M4 ;
        RECT  0 29.424 0.084 29.448 ;
    END
  END li_d[39]
  PIN li_d[3]
    DIRECTION INPUT ;
    USE SIGNAL ;
    PORT
      LAYER M4 ;
        RECT  0 18.336 0.084 18.36 ;
    END
  END li_d[3]
  PIN li_d[40]
    DIRECTION INPUT ;
    USE SIGNAL ;
    PORT
      LAYER M4 ;
        RECT  0 29.712 0.084 29.736 ;
    END
  END li_d[40]
  PIN li_d[41]
    DIRECTION INPUT ;
    USE SIGNAL ;
    PORT
      LAYER M4 ;
        RECT  0 30.048 0.084 30.072 ;
    END
  END li_d[41]
  PIN li_d[42]
    DIRECTION INPUT ;
    USE SIGNAL ;
    PORT
      LAYER M4 ;
        RECT  0 30.336 0.084 30.36 ;
    END
  END li_d[42]
  PIN li_d[43]
    DIRECTION INPUT ;
    USE SIGNAL ;
    PORT
      LAYER M4 ;
        RECT  0 30.624 0.084 30.648 ;
    END
  END li_d[43]
  PIN li_d[44]
    DIRECTION INPUT ;
    USE SIGNAL ;
    PORT
      LAYER M4 ;
        RECT  0 30.96 0.084 30.984 ;
    END
  END li_d[44]
  PIN li_d[45]
    DIRECTION INPUT ;
    USE SIGNAL ;
    PORT
      LAYER M4 ;
        RECT  0 31.248 0.084 31.272 ;
    END
  END li_d[45]
  PIN li_d[46]
    DIRECTION INPUT ;
    USE SIGNAL ;
    PORT
      LAYER M4 ;
        RECT  0 31.584 0.084 31.608 ;
    END
  END li_d[46]
  PIN li_d[47]
    DIRECTION INPUT ;
    USE SIGNAL ;
    PORT
      LAYER M4 ;
        RECT  0 31.872 0.084 31.896 ;
    END
  END li_d[47]
  PIN li_d[48]
    DIRECTION INPUT ;
    USE SIGNAL ;
    PORT
      LAYER M4 ;
        RECT  0 32.16 0.084 32.184 ;
    END
  END li_d[48]
  PIN li_d[49]
    DIRECTION INPUT ;
    USE SIGNAL ;
    PORT
      LAYER M4 ;
        RECT  0 32.496 0.084 32.52 ;
    END
  END li_d[49]
  PIN li_d[4]
    DIRECTION INPUT ;
    USE SIGNAL ;
    PORT
      LAYER M4 ;
        RECT  0 18.672 0.084 18.696 ;
    END
  END li_d[4]
  PIN li_d[50]
    DIRECTION INPUT ;
    USE SIGNAL ;
    PORT
      LAYER M4 ;
        RECT  0 32.784 0.084 32.808 ;
    END
  END li_d[50]
  PIN li_d[51]
    DIRECTION INPUT ;
    USE SIGNAL ;
    PORT
      LAYER M4 ;
        RECT  0 33.12 0.084 33.144 ;
    END
  END li_d[51]
  PIN li_d[52]
    DIRECTION INPUT ;
    USE SIGNAL ;
    PORT
      LAYER M4 ;
        RECT  0 33.408 0.084 33.432 ;
    END
  END li_d[52]
  PIN li_d[53]
    DIRECTION INPUT ;
    USE SIGNAL ;
    PORT
      LAYER M4 ;
        RECT  0 33.696 0.084 33.72 ;
    END
  END li_d[53]
  PIN li_d[54]
    DIRECTION INPUT ;
    USE SIGNAL ;
    PORT
      LAYER M4 ;
        RECT  0 34.032 0.084 34.056 ;
    END
  END li_d[54]
  PIN li_d[55]
    DIRECTION INPUT ;
    USE SIGNAL ;
    PORT
      LAYER M4 ;
        RECT  0 34.32 0.084 34.344 ;
    END
  END li_d[55]
  PIN li_d[56]
    DIRECTION INPUT ;
    USE SIGNAL ;
    PORT
      LAYER M4 ;
        RECT  0 34.656 0.084 34.68 ;
    END
  END li_d[56]
  PIN li_d[57]
    DIRECTION INPUT ;
    USE SIGNAL ;
    PORT
      LAYER M4 ;
        RECT  0 34.944 0.084 34.968 ;
    END
  END li_d[57]
  PIN li_d[58]
    DIRECTION INPUT ;
    USE SIGNAL ;
    PORT
      LAYER M4 ;
        RECT  0 35.28 0.084 35.304 ;
    END
  END li_d[58]
  PIN li_d[59]
    DIRECTION INPUT ;
    USE SIGNAL ;
    PORT
      LAYER M4 ;
        RECT  0 35.568 0.084 35.592 ;
    END
  END li_d[59]
  PIN li_d[5]
    DIRECTION INPUT ;
    USE SIGNAL ;
    PORT
      LAYER M4 ;
        RECT  0 18.96 0.084 18.984 ;
    END
  END li_d[5]
  PIN li_d[60]
    DIRECTION INPUT ;
    USE SIGNAL ;
    PORT
      LAYER M4 ;
        RECT  0 35.856 0.084 35.88 ;
    END
  END li_d[60]
  PIN li_d[61]
    DIRECTION INPUT ;
    USE SIGNAL ;
    PORT
      LAYER M4 ;
        RECT  0 36.192 0.084 36.216 ;
    END
  END li_d[61]
  PIN li_d[62]
    DIRECTION INPUT ;
    USE SIGNAL ;
    PORT
      LAYER M4 ;
        RECT  0 36.48 0.084 36.504 ;
    END
  END li_d[62]
  PIN li_d[63]
    DIRECTION INPUT ;
    USE SIGNAL ;
    PORT
      LAYER M4 ;
        RECT  0 36.816 0.084 36.84 ;
    END
  END li_d[63]
  PIN li_d[64]
    DIRECTION INPUT ;
    USE SIGNAL ;
    PORT
      LAYER M4 ;
        RECT  0 37.104 0.084 37.128 ;
    END
  END li_d[64]
  PIN li_d[65]
    DIRECTION INPUT ;
    USE SIGNAL ;
    PORT
      LAYER M4 ;
        RECT  0 37.392 0.084 37.416 ;
    END
  END li_d[65]
  PIN li_d[66]
    DIRECTION INPUT ;
    USE SIGNAL ;
    PORT
      LAYER M4 ;
        RECT  0 37.728 0.084 37.752 ;
    END
  END li_d[66]
  PIN li_d[67]
    DIRECTION INPUT ;
    USE SIGNAL ;
    PORT
      LAYER M4 ;
        RECT  0 38.016 0.084 38.04 ;
    END
  END li_d[67]
  PIN li_d[68]
    DIRECTION INPUT ;
    USE SIGNAL ;
    PORT
      LAYER M4 ;
        RECT  0 38.352 0.084 38.376 ;
    END
  END li_d[68]
  PIN li_d[69]
    DIRECTION INPUT ;
    USE SIGNAL ;
    PORT
      LAYER M4 ;
        RECT  0 38.64 0.084 38.664 ;
    END
  END li_d[69]
  PIN li_d[6]
    DIRECTION INPUT ;
    USE SIGNAL ;
    PORT
      LAYER M4 ;
        RECT  0 19.248 0.084 19.272 ;
    END
  END li_d[6]
  PIN li_d[70]
    DIRECTION INPUT ;
    USE SIGNAL ;
    PORT
      LAYER M4 ;
        RECT  0 38.928 0.084 38.952 ;
    END
  END li_d[70]
  PIN li_d[71]
    DIRECTION INPUT ;
    USE SIGNAL ;
    PORT
      LAYER M4 ;
        RECT  0 39.264 0.084 39.288 ;
    END
  END li_d[71]
  PIN li_d[72]
    DIRECTION INPUT ;
    USE SIGNAL ;
    PORT
      LAYER M4 ;
        RECT  0 39.552 0.084 39.576 ;
    END
  END li_d[72]
  PIN li_d[73]
    DIRECTION INPUT ;
    USE SIGNAL ;
    PORT
      LAYER M4 ;
        RECT  0 39.888 0.084 39.912 ;
    END
  END li_d[73]
  PIN li_d[74]
    DIRECTION INPUT ;
    USE SIGNAL ;
    PORT
      LAYER M4 ;
        RECT  0 40.176 0.084 40.2 ;
    END
  END li_d[74]
  PIN li_d[75]
    DIRECTION INPUT ;
    USE SIGNAL ;
    PORT
      LAYER M4 ;
        RECT  0 40.464 0.084 40.488 ;
    END
  END li_d[75]
  PIN li_d[76]
    DIRECTION INPUT ;
    USE SIGNAL ;
    PORT
      LAYER M4 ;
        RECT  0 40.8 0.084 40.824 ;
    END
  END li_d[76]
  PIN li_d[77]
    DIRECTION INPUT ;
    USE SIGNAL ;
    PORT
      LAYER M4 ;
        RECT  0 41.088 0.084 41.112 ;
    END
  END li_d[77]
  PIN li_d[78]
    DIRECTION INPUT ;
    USE SIGNAL ;
    PORT
      LAYER M4 ;
        RECT  0 41.424 0.084 41.448 ;
    END
  END li_d[78]
  PIN li_d[79]
    DIRECTION INPUT ;
    USE SIGNAL ;
    PORT
      LAYER M4 ;
        RECT  0 41.712 0.084 41.736 ;
    END
  END li_d[79]
  PIN li_d[7]
    DIRECTION INPUT ;
    USE SIGNAL ;
    PORT
      LAYER M4 ;
        RECT  0 19.584 0.084 19.608 ;
    END
  END li_d[7]
  PIN li_d[80]
    DIRECTION INPUT ;
    USE SIGNAL ;
    PORT
      LAYER M4 ;
        RECT  0 42 0.084 42.024 ;
    END
  END li_d[80]
  PIN li_d[81]
    DIRECTION INPUT ;
    USE SIGNAL ;
    PORT
      LAYER M4 ;
        RECT  0 42.336 0.084 42.36 ;
    END
  END li_d[81]
  PIN li_d[82]
    DIRECTION INPUT ;
    USE SIGNAL ;
    PORT
      LAYER M4 ;
        RECT  0 42.624 0.084 42.648 ;
    END
  END li_d[82]
  PIN li_d[83]
    DIRECTION INPUT ;
    USE SIGNAL ;
    PORT
      LAYER M4 ;
        RECT  0 42.96 0.084 42.984 ;
    END
  END li_d[83]
  PIN li_d[84]
    DIRECTION INPUT ;
    USE SIGNAL ;
    PORT
      LAYER M4 ;
        RECT  0 43.248 0.084 43.272 ;
    END
  END li_d[84]
  PIN li_d[85]
    DIRECTION INPUT ;
    USE SIGNAL ;
    PORT
      LAYER M4 ;
        RECT  0 43.536 0.084 43.56 ;
    END
  END li_d[85]
  PIN li_d[86]
    DIRECTION INPUT ;
    USE SIGNAL ;
    PORT
      LAYER M4 ;
        RECT  0 43.872 0.084 43.896 ;
    END
  END li_d[86]
  PIN li_d[87]
    DIRECTION INPUT ;
    USE SIGNAL ;
    PORT
      LAYER M4 ;
        RECT  0 44.16 0.084 44.184 ;
    END
  END li_d[87]
  PIN li_d[88]
    DIRECTION INPUT ;
    USE SIGNAL ;
    PORT
      LAYER M4 ;
        RECT  0 44.496 0.084 44.52 ;
    END
  END li_d[88]
  PIN li_d[89]
    DIRECTION INPUT ;
    USE SIGNAL ;
    PORT
      LAYER M4 ;
        RECT  0 44.784 0.084 44.808 ;
    END
  END li_d[89]
  PIN li_d[8]
    DIRECTION INPUT ;
    USE SIGNAL ;
    PORT
      LAYER M4 ;
        RECT  0 19.872 0.084 19.896 ;
    END
  END li_d[8]
  PIN li_d[90]
    DIRECTION INPUT ;
    USE SIGNAL ;
    PORT
      LAYER M4 ;
        RECT  0 45.12 0.084 45.144 ;
    END
  END li_d[90]
  PIN li_d[91]
    DIRECTION INPUT ;
    USE SIGNAL ;
    PORT
      LAYER M4 ;
        RECT  0 45.408 0.084 45.432 ;
    END
  END li_d[91]
  PIN li_d[92]
    DIRECTION INPUT ;
    USE SIGNAL ;
    PORT
      LAYER M4 ;
        RECT  0 45.696 0.084 45.72 ;
    END
  END li_d[92]
  PIN li_d[93]
    DIRECTION INPUT ;
    USE SIGNAL ;
    PORT
      LAYER M4 ;
        RECT  0 46.032 0.084 46.056 ;
    END
  END li_d[93]
  PIN li_d[94]
    DIRECTION INPUT ;
    USE SIGNAL ;
    PORT
      LAYER M4 ;
        RECT  0 46.32 0.084 46.344 ;
    END
  END li_d[94]
  PIN li_d[95]
    DIRECTION INPUT ;
    USE SIGNAL ;
    PORT
      LAYER M4 ;
        RECT  0 46.656 0.084 46.68 ;
    END
  END li_d[95]
  PIN li_d[96]
    DIRECTION INPUT ;
    USE SIGNAL ;
    PORT
      LAYER M4 ;
        RECT  0 46.944 0.084 46.968 ;
    END
  END li_d[96]
  PIN li_d[97]
    DIRECTION INPUT ;
    USE SIGNAL ;
    PORT
      LAYER M4 ;
        RECT  0 47.232 0.084 47.256 ;
    END
  END li_d[97]
  PIN li_d[98]
    DIRECTION INPUT ;
    USE SIGNAL ;
    PORT
      LAYER M4 ;
        RECT  0 47.568 0.084 47.592 ;
    END
  END li_d[98]
  PIN li_d[99]
    DIRECTION INPUT ;
    USE SIGNAL ;
    PORT
      LAYER M4 ;
        RECT  0 47.856 0.084 47.88 ;
    END
  END li_d[99]
  PIN li_d[9]
    DIRECTION INPUT ;
    USE SIGNAL ;
    PORT
      LAYER M4 ;
        RECT  0 20.208 0.084 20.232 ;
    END
  END li_d[9]
  PIN li_r
    DIRECTION OUTPUT ;
    USE SIGNAL ;
    PORT
      LAYER M4 ;
        RECT  0 7.008 0.084 7.032 ;
    END
    PORT
      LAYER M4 ;
        RECT  0.06 7.008 0.569 7.032 ;
    END
  END li_r
  PIN li_v
    DIRECTION INPUT ;
    USE SIGNAL ;
    PORT
      LAYER M4 ;
        RECT  0 4.848 0.084 4.872 ;
    END
    PORT
      LAYER M4 ;
        RECT  0.06 4.848 0.097 4.872 ;
    END
  END li_v
  PIN lo_r
    DIRECTION INPUT ;
    USE SIGNAL ;
    PORT
      LAYER M4 ;
        RECT  0 2.688 0.084 2.712 ;
    END
    PORT
      LAYER M4 ;
        RECT  0.06 2.688 2.408 2.712 ;
    END
  END lo_r
  PIN ovf_t
    DIRECTION INPUT ;
    USE SIGNAL ;
    PORT
      LAYER M5 ;
        RECT  54.528 0 54.552 0.084 ;
    END
    PORT
      LAYER M5 ;
        RECT  54.528 0.016 54.552 2.291 ;
    END
  END ovf_t
  PIN r_lane
    DIRECTION OUTPUT ;
    USE SIGNAL ;
    PORT
      LAYER M4 ;
        RECT  0 13.488 0.084 13.512 ;
    END
    PORT
      LAYER M4 ;
        RECT  0.06 13.488 2.408 13.512 ;
    END
  END r_lane
  PIN r_misc_o
    DIRECTION OUTPUT ;
    USE SIGNAL ;
    PORT
      LAYER M4 ;
        RECT  0 15.648 0.084 15.672 ;
    END
    PORT
      LAYER M4 ;
        RECT  0.06 15.648 0.569 15.672 ;
    END
  END r_misc_o
  PIN rst_n
    DIRECTION INPUT ;
    USE SIGNAL ;
    PORT
      LAYER M5 ;
        RECT  50.736 107.916 50.76 108 ;
    END
    PORT
      LAYER M5 ;
        RECT  50.736 107.173 50.76 107.984 ;
    END
  END rst_n
  PIN rx_d[0]
    DIRECTION OUTPUT ;
    USE SIGNAL ;
    PORT
      LAYER M4 ;
        RECT  86.316 17.424 86.4 17.448 ;
    END
  END rx_d[0]
  PIN rx_d[100]
    DIRECTION OUTPUT ;
    USE SIGNAL ;
    PORT
      LAYER M4 ;
        RECT  86.316 48.192 86.4 48.216 ;
    END
  END rx_d[100]
  PIN rx_d[101]
    DIRECTION OUTPUT ;
    USE SIGNAL ;
    PORT
      LAYER M4 ;
        RECT  86.316 48.48 86.4 48.504 ;
    END
  END rx_d[101]
  PIN rx_d[102]
    DIRECTION OUTPUT ;
    USE SIGNAL ;
    PORT
      LAYER M4 ;
        RECT  86.316 48.768 86.4 48.792 ;
    END
  END rx_d[102]
  PIN rx_d[103]
    DIRECTION OUTPUT ;
    USE SIGNAL ;
    PORT
      LAYER M4 ;
        RECT  86.316 49.104 86.4 49.128 ;
    END
  END rx_d[103]
  PIN rx_d[104]
    DIRECTION OUTPUT ;
    USE SIGNAL ;
    PORT
      LAYER M4 ;
        RECT  86.316 49.392 86.4 49.416 ;
    END
  END rx_d[104]
  PIN rx_d[105]
    DIRECTION OUTPUT ;
    USE SIGNAL ;
    PORT
      LAYER M4 ;
        RECT  86.316 49.728 86.4 49.752 ;
    END
  END rx_d[105]
  PIN rx_d[106]
    DIRECTION OUTPUT ;
    USE SIGNAL ;
    PORT
      LAYER M4 ;
        RECT  86.316 50.016 86.4 50.04 ;
    END
  END rx_d[106]
  PIN rx_d[107]
    DIRECTION OUTPUT ;
    USE SIGNAL ;
    PORT
      LAYER M4 ;
        RECT  86.316 50.304 86.4 50.328 ;
    END
  END rx_d[107]
  PIN rx_d[108]
    DIRECTION OUTPUT ;
    USE SIGNAL ;
    PORT
      LAYER M4 ;
        RECT  86.316 50.64 86.4 50.664 ;
    END
  END rx_d[108]
  PIN rx_d[109]
    DIRECTION OUTPUT ;
    USE SIGNAL ;
    PORT
      LAYER M4 ;
        RECT  86.316 50.928 86.4 50.952 ;
    END
  END rx_d[109]
  PIN rx_d[10]
    DIRECTION OUTPUT ;
    USE SIGNAL ;
    PORT
      LAYER M4 ;
        RECT  86.316 20.496 86.4 20.52 ;
    END
  END rx_d[10]
  PIN rx_d[110]
    DIRECTION OUTPUT ;
    USE SIGNAL ;
    PORT
      LAYER M4 ;
        RECT  86.316 51.264 86.4 51.288 ;
    END
  END rx_d[110]
  PIN rx_d[111]
    DIRECTION OUTPUT ;
    USE SIGNAL ;
    PORT
      LAYER M4 ;
        RECT  86.316 51.552 86.4 51.576 ;
    END
  END rx_d[111]
  PIN rx_d[112]
    DIRECTION OUTPUT ;
    USE SIGNAL ;
    PORT
      LAYER M4 ;
        RECT  86.316 51.84 86.4 51.864 ;
    END
  END rx_d[112]
  PIN rx_d[113]
    DIRECTION OUTPUT ;
    USE SIGNAL ;
    PORT
      LAYER M4 ;
        RECT  86.316 52.176 86.4 52.2 ;
    END
  END rx_d[113]
  PIN rx_d[114]
    DIRECTION OUTPUT ;
    USE SIGNAL ;
    PORT
      LAYER M4 ;
        RECT  86.316 52.464 86.4 52.488 ;
    END
  END rx_d[114]
  PIN rx_d[115]
    DIRECTION OUTPUT ;
    USE SIGNAL ;
    PORT
      LAYER M4 ;
        RECT  86.316 52.8 86.4 52.824 ;
    END
  END rx_d[115]
  PIN rx_d[116]
    DIRECTION OUTPUT ;
    USE SIGNAL ;
    PORT
      LAYER M4 ;
        RECT  86.316 53.088 86.4 53.112 ;
    END
  END rx_d[116]
  PIN rx_d[117]
    DIRECTION OUTPUT ;
    USE SIGNAL ;
    PORT
      LAYER M4 ;
        RECT  86.316 53.376 86.4 53.4 ;
    END
  END rx_d[117]
  PIN rx_d[118]
    DIRECTION OUTPUT ;
    USE SIGNAL ;
    PORT
      LAYER M4 ;
        RECT  86.316 53.712 86.4 53.736 ;
    END
  END rx_d[118]
  PIN rx_d[119]
    DIRECTION OUTPUT ;
    USE SIGNAL ;
    PORT
      LAYER M4 ;
        RECT  86.316 54 86.4 54.024 ;
    END
  END rx_d[119]
  PIN rx_d[11]
    DIRECTION OUTPUT ;
    USE SIGNAL ;
    PORT
      LAYER M4 ;
        RECT  86.316 20.784 86.4 20.808 ;
    END
  END rx_d[11]
  PIN rx_d[120]
    DIRECTION OUTPUT ;
    USE SIGNAL ;
    PORT
      LAYER M4 ;
        RECT  86.316 54.336 86.4 54.36 ;
    END
  END rx_d[120]
  PIN rx_d[121]
    DIRECTION OUTPUT ;
    USE SIGNAL ;
    PORT
      LAYER M4 ;
        RECT  86.316 54.624 86.4 54.648 ;
    END
  END rx_d[121]
  PIN rx_d[122]
    DIRECTION OUTPUT ;
    USE SIGNAL ;
    PORT
      LAYER M4 ;
        RECT  86.316 54.96 86.4 54.984 ;
    END
  END rx_d[122]
  PIN rx_d[123]
    DIRECTION OUTPUT ;
    USE SIGNAL ;
    PORT
      LAYER M4 ;
        RECT  86.316 55.248 86.4 55.272 ;
    END
  END rx_d[123]
  PIN rx_d[124]
    DIRECTION OUTPUT ;
    USE SIGNAL ;
    PORT
      LAYER M4 ;
        RECT  86.316 55.536 86.4 55.56 ;
    END
  END rx_d[124]
  PIN rx_d[125]
    DIRECTION OUTPUT ;
    USE SIGNAL ;
    PORT
      LAYER M4 ;
        RECT  86.316 55.872 86.4 55.896 ;
    END
  END rx_d[125]
  PIN rx_d[126]
    DIRECTION OUTPUT ;
    USE SIGNAL ;
    PORT
      LAYER M4 ;
        RECT  86.316 56.16 86.4 56.184 ;
    END
  END rx_d[126]
  PIN rx_d[127]
    DIRECTION OUTPUT ;
    USE SIGNAL ;
    PORT
      LAYER M4 ;
        RECT  86.316 56.496 86.4 56.52 ;
    END
  END rx_d[127]
  PIN rx_d[128]
    DIRECTION OUTPUT ;
    USE SIGNAL ;
    PORT
      LAYER M4 ;
        RECT  86.316 56.784 86.4 56.808 ;
    END
  END rx_d[128]
  PIN rx_d[129]
    DIRECTION OUTPUT ;
    USE SIGNAL ;
    PORT
      LAYER M4 ;
        RECT  86.316 57.072 86.4 57.096 ;
    END
  END rx_d[129]
  PIN rx_d[12]
    DIRECTION OUTPUT ;
    USE SIGNAL ;
    PORT
      LAYER M4 ;
        RECT  86.316 21.12 86.4 21.144 ;
    END
  END rx_d[12]
  PIN rx_d[130]
    DIRECTION OUTPUT ;
    USE SIGNAL ;
    PORT
      LAYER M4 ;
        RECT  86.316 57.408 86.4 57.432 ;
    END
  END rx_d[130]
  PIN rx_d[131]
    DIRECTION OUTPUT ;
    USE SIGNAL ;
    PORT
      LAYER M4 ;
        RECT  86.316 57.696 86.4 57.72 ;
    END
  END rx_d[131]
  PIN rx_d[132]
    DIRECTION OUTPUT ;
    USE SIGNAL ;
    PORT
      LAYER M4 ;
        RECT  86.316 58.032 86.4 58.056 ;
    END
  END rx_d[132]
  PIN rx_d[133]
    DIRECTION OUTPUT ;
    USE SIGNAL ;
    PORT
      LAYER M4 ;
        RECT  86.316 58.32 86.4 58.344 ;
    END
  END rx_d[133]
  PIN rx_d[134]
    DIRECTION OUTPUT ;
    USE SIGNAL ;
    PORT
      LAYER M4 ;
        RECT  86.316 58.608 86.4 58.632 ;
    END
  END rx_d[134]
  PIN rx_d[135]
    DIRECTION OUTPUT ;
    USE SIGNAL ;
    PORT
      LAYER M4 ;
        RECT  86.316 58.944 86.4 58.968 ;
    END
  END rx_d[135]
  PIN rx_d[136]
    DIRECTION OUTPUT ;
    USE SIGNAL ;
    PORT
      LAYER M4 ;
        RECT  86.316 59.232 86.4 59.256 ;
    END
  END rx_d[136]
  PIN rx_d[137]
    DIRECTION OUTPUT ;
    USE SIGNAL ;
    PORT
      LAYER M4 ;
        RECT  86.316 59.568 86.4 59.592 ;
    END
  END rx_d[137]
  PIN rx_d[138]
    DIRECTION OUTPUT ;
    USE SIGNAL ;
    PORT
      LAYER M4 ;
        RECT  86.316 59.856 86.4 59.88 ;
    END
  END rx_d[138]
  PIN rx_d[139]
    DIRECTION OUTPUT ;
    USE SIGNAL ;
    PORT
      LAYER M4 ;
        RECT  86.316 60.144 86.4 60.168 ;
    END
  END rx_d[139]
  PIN rx_d[13]
    DIRECTION OUTPUT ;
    USE SIGNAL ;
    PORT
      LAYER M4 ;
        RECT  86.316 21.408 86.4 21.432 ;
    END
  END rx_d[13]
  PIN rx_d[140]
    DIRECTION OUTPUT ;
    USE SIGNAL ;
    PORT
      LAYER M4 ;
        RECT  86.316 60.48 86.4 60.504 ;
    END
  END rx_d[140]
  PIN rx_d[141]
    DIRECTION OUTPUT ;
    USE SIGNAL ;
    PORT
      LAYER M4 ;
        RECT  86.316 60.768 86.4 60.792 ;
    END
  END rx_d[141]
  PIN rx_d[142]
    DIRECTION OUTPUT ;
    USE SIGNAL ;
    PORT
      LAYER M4 ;
        RECT  86.316 61.104 86.4 61.128 ;
    END
  END rx_d[142]
  PIN rx_d[143]
    DIRECTION OUTPUT ;
    USE SIGNAL ;
    PORT
      LAYER M4 ;
        RECT  86.316 61.392 86.4 61.416 ;
    END
  END rx_d[143]
  PIN rx_d[144]
    DIRECTION OUTPUT ;
    USE SIGNAL ;
    PORT
      LAYER M4 ;
        RECT  86.316 61.68 86.4 61.704 ;
    END
  END rx_d[144]
  PIN rx_d[145]
    DIRECTION OUTPUT ;
    USE SIGNAL ;
    PORT
      LAYER M4 ;
        RECT  86.316 62.016 86.4 62.04 ;
    END
  END rx_d[145]
  PIN rx_d[146]
    DIRECTION OUTPUT ;
    USE SIGNAL ;
    PORT
      LAYER M4 ;
        RECT  86.316 62.304 86.4 62.328 ;
    END
  END rx_d[146]
  PIN rx_d[147]
    DIRECTION OUTPUT ;
    USE SIGNAL ;
    PORT
      LAYER M4 ;
        RECT  86.316 62.64 86.4 62.664 ;
    END
  END rx_d[147]
  PIN rx_d[148]
    DIRECTION OUTPUT ;
    USE SIGNAL ;
    PORT
      LAYER M4 ;
        RECT  86.316 62.928 86.4 62.952 ;
    END
  END rx_d[148]
  PIN rx_d[149]
    DIRECTION OUTPUT ;
    USE SIGNAL ;
    PORT
      LAYER M4 ;
        RECT  86.316 63.216 86.4 63.24 ;
    END
  END rx_d[149]
  PIN rx_d[14]
    DIRECTION OUTPUT ;
    USE SIGNAL ;
    PORT
      LAYER M4 ;
        RECT  86.316 21.744 86.4 21.768 ;
    END
  END rx_d[14]
  PIN rx_d[150]
    DIRECTION OUTPUT ;
    USE SIGNAL ;
    PORT
      LAYER M4 ;
        RECT  86.316 63.552 86.4 63.576 ;
    END
  END rx_d[150]
  PIN rx_d[151]
    DIRECTION OUTPUT ;
    USE SIGNAL ;
    PORT
      LAYER M4 ;
        RECT  86.316 63.84 86.4 63.864 ;
    END
  END rx_d[151]
  PIN rx_d[152]
    DIRECTION OUTPUT ;
    USE SIGNAL ;
    PORT
      LAYER M4 ;
        RECT  86.316 64.176 86.4 64.2 ;
    END
  END rx_d[152]
  PIN rx_d[153]
    DIRECTION OUTPUT ;
    USE SIGNAL ;
    PORT
      LAYER M4 ;
        RECT  86.316 64.464 86.4 64.488 ;
    END
  END rx_d[153]
  PIN rx_d[154]
    DIRECTION OUTPUT ;
    USE SIGNAL ;
    PORT
      LAYER M4 ;
        RECT  86.316 64.8 86.4 64.824 ;
    END
  END rx_d[154]
  PIN rx_d[155]
    DIRECTION OUTPUT ;
    USE SIGNAL ;
    PORT
      LAYER M4 ;
        RECT  86.316 65.088 86.4 65.112 ;
    END
  END rx_d[155]
  PIN rx_d[156]
    DIRECTION OUTPUT ;
    USE SIGNAL ;
    PORT
      LAYER M4 ;
        RECT  86.316 65.376 86.4 65.4 ;
    END
  END rx_d[156]
  PIN rx_d[157]
    DIRECTION OUTPUT ;
    USE SIGNAL ;
    PORT
      LAYER M4 ;
        RECT  86.316 65.712 86.4 65.736 ;
    END
  END rx_d[157]
  PIN rx_d[158]
    DIRECTION OUTPUT ;
    USE SIGNAL ;
    PORT
      LAYER M4 ;
        RECT  86.316 66 86.4 66.024 ;
    END
  END rx_d[158]
  PIN rx_d[159]
    DIRECTION OUTPUT ;
    USE SIGNAL ;
    PORT
      LAYER M4 ;
        RECT  86.316 66.336 86.4 66.36 ;
    END
  END rx_d[159]
  PIN rx_d[15]
    DIRECTION OUTPUT ;
    USE SIGNAL ;
    PORT
      LAYER M4 ;
        RECT  86.316 22.032 86.4 22.056 ;
    END
  END rx_d[15]
  PIN rx_d[160]
    DIRECTION OUTPUT ;
    USE SIGNAL ;
    PORT
      LAYER M4 ;
        RECT  86.316 66.624 86.4 66.648 ;
    END
  END rx_d[160]
  PIN rx_d[161]
    DIRECTION OUTPUT ;
    USE SIGNAL ;
    PORT
      LAYER M4 ;
        RECT  86.316 66.912 86.4 66.936 ;
    END
  END rx_d[161]
  PIN rx_d[162]
    DIRECTION OUTPUT ;
    USE SIGNAL ;
    PORT
      LAYER M4 ;
        RECT  86.316 67.248 86.4 67.272 ;
    END
  END rx_d[162]
  PIN rx_d[163]
    DIRECTION OUTPUT ;
    USE SIGNAL ;
    PORT
      LAYER M4 ;
        RECT  86.316 67.536 86.4 67.56 ;
    END
  END rx_d[163]
  PIN rx_d[164]
    DIRECTION OUTPUT ;
    USE SIGNAL ;
    PORT
      LAYER M4 ;
        RECT  86.316 67.872 86.4 67.896 ;
    END
  END rx_d[164]
  PIN rx_d[165]
    DIRECTION OUTPUT ;
    USE SIGNAL ;
    PORT
      LAYER M4 ;
        RECT  86.316 68.16 86.4 68.184 ;
    END
  END rx_d[165]
  PIN rx_d[166]
    DIRECTION OUTPUT ;
    USE SIGNAL ;
    PORT
      LAYER M4 ;
        RECT  86.316 68.448 86.4 68.472 ;
    END
  END rx_d[166]
  PIN rx_d[167]
    DIRECTION OUTPUT ;
    USE SIGNAL ;
    PORT
      LAYER M4 ;
        RECT  86.316 68.784 86.4 68.808 ;
    END
  END rx_d[167]
  PIN rx_d[168]
    DIRECTION OUTPUT ;
    USE SIGNAL ;
    PORT
      LAYER M4 ;
        RECT  86.316 69.072 86.4 69.096 ;
    END
  END rx_d[168]
  PIN rx_d[169]
    DIRECTION OUTPUT ;
    USE SIGNAL ;
    PORT
      LAYER M4 ;
        RECT  86.316 69.408 86.4 69.432 ;
    END
  END rx_d[169]
  PIN rx_d[16]
    DIRECTION OUTPUT ;
    USE SIGNAL ;
    PORT
      LAYER M4 ;
        RECT  86.316 22.32 86.4 22.344 ;
    END
  END rx_d[16]
  PIN rx_d[170]
    DIRECTION OUTPUT ;
    USE SIGNAL ;
    PORT
      LAYER M4 ;
        RECT  86.316 69.696 86.4 69.72 ;
    END
  END rx_d[170]
  PIN rx_d[171]
    DIRECTION OUTPUT ;
    USE SIGNAL ;
    PORT
      LAYER M4 ;
        RECT  86.316 69.984 86.4 70.008 ;
    END
  END rx_d[171]
  PIN rx_d[172]
    DIRECTION OUTPUT ;
    USE SIGNAL ;
    PORT
      LAYER M4 ;
        RECT  86.316 70.32 86.4 70.344 ;
    END
  END rx_d[172]
  PIN rx_d[173]
    DIRECTION OUTPUT ;
    USE SIGNAL ;
    PORT
      LAYER M4 ;
        RECT  86.316 70.608 86.4 70.632 ;
    END
  END rx_d[173]
  PIN rx_d[174]
    DIRECTION OUTPUT ;
    USE SIGNAL ;
    PORT
      LAYER M4 ;
        RECT  86.316 70.944 86.4 70.968 ;
    END
  END rx_d[174]
  PIN rx_d[175]
    DIRECTION OUTPUT ;
    USE SIGNAL ;
    PORT
      LAYER M4 ;
        RECT  86.316 71.232 86.4 71.256 ;
    END
  END rx_d[175]
  PIN rx_d[176]
    DIRECTION OUTPUT ;
    USE SIGNAL ;
    PORT
      LAYER M4 ;
        RECT  86.316 71.52 86.4 71.544 ;
    END
  END rx_d[176]
  PIN rx_d[177]
    DIRECTION OUTPUT ;
    USE SIGNAL ;
    PORT
      LAYER M4 ;
        RECT  86.316 71.856 86.4 71.88 ;
    END
  END rx_d[177]
  PIN rx_d[178]
    DIRECTION OUTPUT ;
    USE SIGNAL ;
    PORT
      LAYER M4 ;
        RECT  86.316 72.144 86.4 72.168 ;
    END
  END rx_d[178]
  PIN rx_d[179]
    DIRECTION OUTPUT ;
    USE SIGNAL ;
    PORT
      LAYER M4 ;
        RECT  86.316 72.48 86.4 72.504 ;
    END
  END rx_d[179]
  PIN rx_d[17]
    DIRECTION OUTPUT ;
    USE SIGNAL ;
    PORT
      LAYER M4 ;
        RECT  86.316 22.656 86.4 22.68 ;
    END
  END rx_d[17]
  PIN rx_d[180]
    DIRECTION OUTPUT ;
    USE SIGNAL ;
    PORT
      LAYER M4 ;
        RECT  86.316 72.768 86.4 72.792 ;
    END
  END rx_d[180]
  PIN rx_d[181]
    DIRECTION OUTPUT ;
    USE SIGNAL ;
    PORT
      LAYER M4 ;
        RECT  86.316 73.056 86.4 73.08 ;
    END
  END rx_d[181]
  PIN rx_d[182]
    DIRECTION OUTPUT ;
    USE SIGNAL ;
    PORT
      LAYER M4 ;
        RECT  86.316 73.392 86.4 73.416 ;
    END
  END rx_d[182]
  PIN rx_d[183]
    DIRECTION OUTPUT ;
    USE SIGNAL ;
    PORT
      LAYER M4 ;
        RECT  86.316 73.68 86.4 73.704 ;
    END
  END rx_d[183]
  PIN rx_d[184]
    DIRECTION OUTPUT ;
    USE SIGNAL ;
    PORT
      LAYER M4 ;
        RECT  86.316 74.016 86.4 74.04 ;
    END
  END rx_d[184]
  PIN rx_d[185]
    DIRECTION OUTPUT ;
    USE SIGNAL ;
    PORT
      LAYER M4 ;
        RECT  86.316 74.304 86.4 74.328 ;
    END
  END rx_d[185]
  PIN rx_d[186]
    DIRECTION OUTPUT ;
    USE SIGNAL ;
    PORT
      LAYER M4 ;
        RECT  86.316 74.64 86.4 74.664 ;
    END
  END rx_d[186]
  PIN rx_d[187]
    DIRECTION OUTPUT ;
    USE SIGNAL ;
    PORT
      LAYER M4 ;
        RECT  86.316 74.928 86.4 74.952 ;
    END
  END rx_d[187]
  PIN rx_d[188]
    DIRECTION OUTPUT ;
    USE SIGNAL ;
    PORT
      LAYER M4 ;
        RECT  86.316 75.216 86.4 75.24 ;
    END
  END rx_d[188]
  PIN rx_d[189]
    DIRECTION OUTPUT ;
    USE SIGNAL ;
    PORT
      LAYER M4 ;
        RECT  86.316 75.552 86.4 75.576 ;
    END
  END rx_d[189]
  PIN rx_d[18]
    DIRECTION OUTPUT ;
    USE SIGNAL ;
    PORT
      LAYER M4 ;
        RECT  86.316 22.944 86.4 22.968 ;
    END
  END rx_d[18]
  PIN rx_d[190]
    DIRECTION OUTPUT ;
    USE SIGNAL ;
    PORT
      LAYER M4 ;
        RECT  86.316 75.84 86.4 75.864 ;
    END
  END rx_d[190]
  PIN rx_d[191]
    DIRECTION OUTPUT ;
    USE SIGNAL ;
    PORT
      LAYER M4 ;
        RECT  86.316 76.176 86.4 76.2 ;
    END
  END rx_d[191]
  PIN rx_d[192]
    DIRECTION OUTPUT ;
    USE SIGNAL ;
    PORT
      LAYER M4 ;
        RECT  86.316 76.464 86.4 76.488 ;
    END
  END rx_d[192]
  PIN rx_d[193]
    DIRECTION OUTPUT ;
    USE SIGNAL ;
    PORT
      LAYER M4 ;
        RECT  86.316 76.752 86.4 76.776 ;
    END
  END rx_d[193]
  PIN rx_d[194]
    DIRECTION OUTPUT ;
    USE SIGNAL ;
    PORT
      LAYER M4 ;
        RECT  86.316 77.088 86.4 77.112 ;
    END
  END rx_d[194]
  PIN rx_d[195]
    DIRECTION OUTPUT ;
    USE SIGNAL ;
    PORT
      LAYER M4 ;
        RECT  86.316 77.376 86.4 77.4 ;
    END
  END rx_d[195]
  PIN rx_d[196]
    DIRECTION OUTPUT ;
    USE SIGNAL ;
    PORT
      LAYER M4 ;
        RECT  86.316 77.712 86.4 77.736 ;
    END
  END rx_d[196]
  PIN rx_d[197]
    DIRECTION OUTPUT ;
    USE SIGNAL ;
    PORT
      LAYER M4 ;
        RECT  86.316 78 86.4 78.024 ;
    END
  END rx_d[197]
  PIN rx_d[198]
    DIRECTION OUTPUT ;
    USE SIGNAL ;
    PORT
      LAYER M4 ;
        RECT  86.316 78.288 86.4 78.312 ;
    END
  END rx_d[198]
  PIN rx_d[199]
    DIRECTION OUTPUT ;
    USE SIGNAL ;
    PORT
      LAYER M4 ;
        RECT  86.316 78.624 86.4 78.648 ;
    END
  END rx_d[199]
  PIN rx_d[19]
    DIRECTION OUTPUT ;
    USE SIGNAL ;
    PORT
      LAYER M4 ;
        RECT  86.316 23.28 86.4 23.304 ;
    END
  END rx_d[19]
  PIN rx_d[1]
    DIRECTION OUTPUT ;
    USE SIGNAL ;
    PORT
      LAYER M4 ;
        RECT  86.316 17.712 86.4 17.736 ;
    END
  END rx_d[1]
  PIN rx_d[200]
    DIRECTION OUTPUT ;
    USE SIGNAL ;
    PORT
      LAYER M4 ;
        RECT  86.316 78.912 86.4 78.936 ;
    END
  END rx_d[200]
  PIN rx_d[201]
    DIRECTION OUTPUT ;
    USE SIGNAL ;
    PORT
      LAYER M4 ;
        RECT  86.316 79.248 86.4 79.272 ;
    END
  END rx_d[201]
  PIN rx_d[202]
    DIRECTION OUTPUT ;
    USE SIGNAL ;
    PORT
      LAYER M4 ;
        RECT  86.316 79.536 86.4 79.56 ;
    END
  END rx_d[202]
  PIN rx_d[203]
    DIRECTION OUTPUT ;
    USE SIGNAL ;
    PORT
      LAYER M4 ;
        RECT  86.316 79.824 86.4 79.848 ;
    END
  END rx_d[203]
  PIN rx_d[204]
    DIRECTION OUTPUT ;
    USE SIGNAL ;
    PORT
      LAYER M4 ;
        RECT  86.316 80.16 86.4 80.184 ;
    END
  END rx_d[204]
  PIN rx_d[205]
    DIRECTION OUTPUT ;
    USE SIGNAL ;
    PORT
      LAYER M4 ;
        RECT  86.316 80.448 86.4 80.472 ;
    END
  END rx_d[205]
  PIN rx_d[206]
    DIRECTION OUTPUT ;
    USE SIGNAL ;
    PORT
      LAYER M4 ;
        RECT  86.316 80.784 86.4 80.808 ;
    END
  END rx_d[206]
  PIN rx_d[207]
    DIRECTION OUTPUT ;
    USE SIGNAL ;
    PORT
      LAYER M4 ;
        RECT  86.316 81.072 86.4 81.096 ;
    END
  END rx_d[207]
  PIN rx_d[208]
    DIRECTION OUTPUT ;
    USE SIGNAL ;
    PORT
      LAYER M4 ;
        RECT  86.316 81.36 86.4 81.384 ;
    END
  END rx_d[208]
  PIN rx_d[209]
    DIRECTION OUTPUT ;
    USE SIGNAL ;
    PORT
      LAYER M4 ;
        RECT  86.316 81.696 86.4 81.72 ;
    END
  END rx_d[209]
  PIN rx_d[20]
    DIRECTION OUTPUT ;
    USE SIGNAL ;
    PORT
      LAYER M4 ;
        RECT  86.316 23.568 86.4 23.592 ;
    END
  END rx_d[20]
  PIN rx_d[210]
    DIRECTION OUTPUT ;
    USE SIGNAL ;
    PORT
      LAYER M4 ;
        RECT  86.316 81.984 86.4 82.008 ;
    END
  END rx_d[210]
  PIN rx_d[211]
    DIRECTION OUTPUT ;
    USE SIGNAL ;
    PORT
      LAYER M4 ;
        RECT  86.316 82.32 86.4 82.344 ;
    END
  END rx_d[211]
  PIN rx_d[212]
    DIRECTION OUTPUT ;
    USE SIGNAL ;
    PORT
      LAYER M4 ;
        RECT  86.316 82.608 86.4 82.632 ;
    END
  END rx_d[212]
  PIN rx_d[213]
    DIRECTION OUTPUT ;
    USE SIGNAL ;
    PORT
      LAYER M4 ;
        RECT  86.316 82.896 86.4 82.92 ;
    END
  END rx_d[213]
  PIN rx_d[214]
    DIRECTION OUTPUT ;
    USE SIGNAL ;
    PORT
      LAYER M4 ;
        RECT  86.316 83.232 86.4 83.256 ;
    END
  END rx_d[214]
  PIN rx_d[215]
    DIRECTION OUTPUT ;
    USE SIGNAL ;
    PORT
      LAYER M4 ;
        RECT  86.316 83.52 86.4 83.544 ;
    END
  END rx_d[215]
  PIN rx_d[216]
    DIRECTION OUTPUT ;
    USE SIGNAL ;
    PORT
      LAYER M4 ;
        RECT  86.316 83.856 86.4 83.88 ;
    END
  END rx_d[216]
  PIN rx_d[217]
    DIRECTION OUTPUT ;
    USE SIGNAL ;
    PORT
      LAYER M4 ;
        RECT  86.316 84.144 86.4 84.168 ;
    END
  END rx_d[217]
  PIN rx_d[218]
    DIRECTION OUTPUT ;
    USE SIGNAL ;
    PORT
      LAYER M4 ;
        RECT  86.316 84.48 86.4 84.504 ;
    END
  END rx_d[218]
  PIN rx_d[219]
    DIRECTION OUTPUT ;
    USE SIGNAL ;
    PORT
      LAYER M4 ;
        RECT  86.316 84.768 86.4 84.792 ;
    END
  END rx_d[219]
  PIN rx_d[21]
    DIRECTION OUTPUT ;
    USE SIGNAL ;
    PORT
      LAYER M4 ;
        RECT  86.316 23.856 86.4 23.88 ;
    END
  END rx_d[21]
  PIN rx_d[220]
    DIRECTION OUTPUT ;
    USE SIGNAL ;
    PORT
      LAYER M4 ;
        RECT  86.316 85.056 86.4 85.08 ;
    END
  END rx_d[220]
  PIN rx_d[221]
    DIRECTION OUTPUT ;
    USE SIGNAL ;
    PORT
      LAYER M4 ;
        RECT  86.316 85.392 86.4 85.416 ;
    END
  END rx_d[221]
  PIN rx_d[222]
    DIRECTION OUTPUT ;
    USE SIGNAL ;
    PORT
      LAYER M4 ;
        RECT  86.316 85.68 86.4 85.704 ;
    END
  END rx_d[222]
  PIN rx_d[223]
    DIRECTION OUTPUT ;
    USE SIGNAL ;
    PORT
      LAYER M4 ;
        RECT  86.316 86.016 86.4 86.04 ;
    END
  END rx_d[223]
  PIN rx_d[224]
    DIRECTION OUTPUT ;
    USE SIGNAL ;
    PORT
      LAYER M4 ;
        RECT  86.316 86.304 86.4 86.328 ;
    END
  END rx_d[224]
  PIN rx_d[225]
    DIRECTION OUTPUT ;
    USE SIGNAL ;
    PORT
      LAYER M4 ;
        RECT  86.316 86.592 86.4 86.616 ;
    END
  END rx_d[225]
  PIN rx_d[226]
    DIRECTION OUTPUT ;
    USE SIGNAL ;
    PORT
      LAYER M4 ;
        RECT  86.316 86.928 86.4 86.952 ;
    END
  END rx_d[226]
  PIN rx_d[227]
    DIRECTION OUTPUT ;
    USE SIGNAL ;
    PORT
      LAYER M4 ;
        RECT  86.316 87.216 86.4 87.24 ;
    END
  END rx_d[227]
  PIN rx_d[228]
    DIRECTION OUTPUT ;
    USE SIGNAL ;
    PORT
      LAYER M4 ;
        RECT  86.316 87.552 86.4 87.576 ;
    END
  END rx_d[228]
  PIN rx_d[229]
    DIRECTION OUTPUT ;
    USE SIGNAL ;
    PORT
      LAYER M4 ;
        RECT  86.316 87.84 86.4 87.864 ;
    END
  END rx_d[229]
  PIN rx_d[22]
    DIRECTION OUTPUT ;
    USE SIGNAL ;
    PORT
      LAYER M4 ;
        RECT  86.316 24.192 86.4 24.216 ;
    END
  END rx_d[22]
  PIN rx_d[230]
    DIRECTION OUTPUT ;
    USE SIGNAL ;
    PORT
      LAYER M4 ;
        RECT  86.316 88.128 86.4 88.152 ;
    END
  END rx_d[230]
  PIN rx_d[231]
    DIRECTION OUTPUT ;
    USE SIGNAL ;
    PORT
      LAYER M4 ;
        RECT  86.316 88.464 86.4 88.488 ;
    END
  END rx_d[231]
  PIN rx_d[232]
    DIRECTION OUTPUT ;
    USE SIGNAL ;
    PORT
      LAYER M4 ;
        RECT  86.316 88.752 86.4 88.776 ;
    END
  END rx_d[232]
  PIN rx_d[233]
    DIRECTION OUTPUT ;
    USE SIGNAL ;
    PORT
      LAYER M4 ;
        RECT  86.316 89.088 86.4 89.112 ;
    END
  END rx_d[233]
  PIN rx_d[234]
    DIRECTION OUTPUT ;
    USE SIGNAL ;
    PORT
      LAYER M4 ;
        RECT  86.316 89.376 86.4 89.4 ;
    END
  END rx_d[234]
  PIN rx_d[235]
    DIRECTION OUTPUT ;
    USE SIGNAL ;
    PORT
      LAYER M4 ;
        RECT  86.316 89.664 86.4 89.688 ;
    END
  END rx_d[235]
  PIN rx_d[236]
    DIRECTION OUTPUT ;
    USE SIGNAL ;
    PORT
      LAYER M4 ;
        RECT  86.316 90 86.4 90.024 ;
    END
  END rx_d[236]
  PIN rx_d[237]
    DIRECTION OUTPUT ;
    USE SIGNAL ;
    PORT
      LAYER M4 ;
        RECT  86.316 90.288 86.4 90.312 ;
    END
  END rx_d[237]
  PIN rx_d[238]
    DIRECTION OUTPUT ;
    USE SIGNAL ;
    PORT
      LAYER M4 ;
        RECT  86.316 90.624 86.4 90.648 ;
    END
  END rx_d[238]
  PIN rx_d[239]
    DIRECTION OUTPUT ;
    USE SIGNAL ;
    PORT
      LAYER M4 ;
        RECT  86.316 90.912 86.4 90.936 ;
    END
  END rx_d[239]
  PIN rx_d[23]
    DIRECTION OUTPUT ;
    USE SIGNAL ;
    PORT
      LAYER M4 ;
        RECT  86.316 24.48 86.4 24.504 ;
    END
  END rx_d[23]
  PIN rx_d[240]
    DIRECTION OUTPUT ;
    USE SIGNAL ;
    PORT
      LAYER M4 ;
        RECT  86.316 91.2 86.4 91.224 ;
    END
  END rx_d[240]
  PIN rx_d[241]
    DIRECTION OUTPUT ;
    USE SIGNAL ;
    PORT
      LAYER M4 ;
        RECT  86.316 91.536 86.4 91.56 ;
    END
  END rx_d[241]
  PIN rx_d[242]
    DIRECTION OUTPUT ;
    USE SIGNAL ;
    PORT
      LAYER M4 ;
        RECT  86.316 91.824 86.4 91.848 ;
    END
  END rx_d[242]
  PIN rx_d[243]
    DIRECTION OUTPUT ;
    USE SIGNAL ;
    PORT
      LAYER M4 ;
        RECT  86.316 92.16 86.4 92.184 ;
    END
  END rx_d[243]
  PIN rx_d[244]
    DIRECTION OUTPUT ;
    USE SIGNAL ;
    PORT
      LAYER M4 ;
        RECT  86.316 92.448 86.4 92.472 ;
    END
  END rx_d[244]
  PIN rx_d[245]
    DIRECTION OUTPUT ;
    USE SIGNAL ;
    PORT
      LAYER M4 ;
        RECT  86.316 92.736 86.4 92.76 ;
    END
  END rx_d[245]
  PIN rx_d[246]
    DIRECTION OUTPUT ;
    USE SIGNAL ;
    PORT
      LAYER M4 ;
        RECT  86.316 93.072 86.4 93.096 ;
    END
  END rx_d[246]
  PIN rx_d[247]
    DIRECTION OUTPUT ;
    USE SIGNAL ;
    PORT
      LAYER M4 ;
        RECT  86.316 93.36 86.4 93.384 ;
    END
  END rx_d[247]
  PIN rx_d[248]
    DIRECTION OUTPUT ;
    USE SIGNAL ;
    PORT
      LAYER M4 ;
        RECT  86.316 93.696 86.4 93.72 ;
    END
  END rx_d[248]
  PIN rx_d[249]
    DIRECTION OUTPUT ;
    USE SIGNAL ;
    PORT
      LAYER M4 ;
        RECT  86.316 93.984 86.4 94.008 ;
    END
  END rx_d[249]
  PIN rx_d[24]
    DIRECTION OUTPUT ;
    USE SIGNAL ;
    PORT
      LAYER M4 ;
        RECT  86.316 24.816 86.4 24.84 ;
    END
  END rx_d[24]
  PIN rx_d[250]
    DIRECTION OUTPUT ;
    USE SIGNAL ;
    PORT
      LAYER M4 ;
        RECT  86.316 94.32 86.4 94.344 ;
    END
  END rx_d[250]
  PIN rx_d[251]
    DIRECTION OUTPUT ;
    USE SIGNAL ;
    PORT
      LAYER M4 ;
        RECT  86.316 94.608 86.4 94.632 ;
    END
  END rx_d[251]
  PIN rx_d[252]
    DIRECTION OUTPUT ;
    USE SIGNAL ;
    PORT
      LAYER M4 ;
        RECT  86.316 94.896 86.4 94.92 ;
    END
  END rx_d[252]
  PIN rx_d[253]
    DIRECTION OUTPUT ;
    USE SIGNAL ;
    PORT
      LAYER M4 ;
        RECT  86.316 95.232 86.4 95.256 ;
    END
  END rx_d[253]
  PIN rx_d[254]
    DIRECTION OUTPUT ;
    USE SIGNAL ;
    PORT
      LAYER M4 ;
        RECT  86.316 95.52 86.4 95.544 ;
    END
  END rx_d[254]
  PIN rx_d[255]
    DIRECTION OUTPUT ;
    USE SIGNAL ;
    PORT
      LAYER M4 ;
        RECT  86.316 95.856 86.4 95.88 ;
    END
  END rx_d[255]
  PIN rx_d[256]
    DIRECTION OUTPUT ;
    USE SIGNAL ;
    PORT
      LAYER M4 ;
        RECT  86.316 96.144 86.4 96.168 ;
    END
  END rx_d[256]
  PIN rx_d[257]
    DIRECTION OUTPUT ;
    USE SIGNAL ;
    PORT
      LAYER M4 ;
        RECT  86.316 96.432 86.4 96.456 ;
    END
  END rx_d[257]
  PIN rx_d[258]
    DIRECTION OUTPUT ;
    USE SIGNAL ;
    PORT
      LAYER M4 ;
        RECT  86.316 96.768 86.4 96.792 ;
    END
  END rx_d[258]
  PIN rx_d[259]
    DIRECTION OUTPUT ;
    USE SIGNAL ;
    PORT
      LAYER M4 ;
        RECT  86.316 97.056 86.4 97.08 ;
    END
  END rx_d[259]
  PIN rx_d[25]
    DIRECTION OUTPUT ;
    USE SIGNAL ;
    PORT
      LAYER M4 ;
        RECT  86.316 25.104 86.4 25.128 ;
    END
  END rx_d[25]
  PIN rx_d[260]
    DIRECTION OUTPUT ;
    USE SIGNAL ;
    PORT
      LAYER M4 ;
        RECT  86.316 97.392 86.4 97.416 ;
    END
  END rx_d[260]
  PIN rx_d[261]
    DIRECTION OUTPUT ;
    USE SIGNAL ;
    PORT
      LAYER M4 ;
        RECT  86.316 97.68 86.4 97.704 ;
    END
  END rx_d[261]
  PIN rx_d[262]
    DIRECTION OUTPUT ;
    USE SIGNAL ;
    PORT
      LAYER M4 ;
        RECT  86.316 97.968 86.4 97.992 ;
    END
  END rx_d[262]
  PIN rx_d[263]
    DIRECTION OUTPUT ;
    USE SIGNAL ;
    PORT
      LAYER M4 ;
        RECT  86.316 98.304 86.4 98.328 ;
    END
  END rx_d[263]
  PIN rx_d[264]
    DIRECTION OUTPUT ;
    USE SIGNAL ;
    PORT
      LAYER M4 ;
        RECT  86.316 98.592 86.4 98.616 ;
    END
  END rx_d[264]
  PIN rx_d[265]
    DIRECTION OUTPUT ;
    USE SIGNAL ;
    PORT
      LAYER M4 ;
        RECT  86.316 98.928 86.4 98.952 ;
    END
  END rx_d[265]
  PIN rx_d[266]
    DIRECTION OUTPUT ;
    USE SIGNAL ;
    PORT
      LAYER M4 ;
        RECT  86.316 99.216 86.4 99.24 ;
    END
  END rx_d[266]
  PIN rx_d[267]
    DIRECTION OUTPUT ;
    USE SIGNAL ;
    PORT
      LAYER M4 ;
        RECT  86.316 99.504 86.4 99.528 ;
    END
  END rx_d[267]
  PIN rx_d[268]
    DIRECTION OUTPUT ;
    USE SIGNAL ;
    PORT
      LAYER M4 ;
        RECT  86.316 99.84 86.4 99.864 ;
    END
  END rx_d[268]
  PIN rx_d[269]
    DIRECTION OUTPUT ;
    USE SIGNAL ;
    PORT
      LAYER M4 ;
        RECT  86.316 100.128 86.4 100.152 ;
    END
  END rx_d[269]
  PIN rx_d[26]
    DIRECTION OUTPUT ;
    USE SIGNAL ;
    PORT
      LAYER M4 ;
        RECT  86.316 25.44 86.4 25.464 ;
    END
  END rx_d[26]
  PIN rx_d[270]
    DIRECTION OUTPUT ;
    USE SIGNAL ;
    PORT
      LAYER M4 ;
        RECT  86.316 100.464 86.4 100.488 ;
    END
  END rx_d[270]
  PIN rx_d[271]
    DIRECTION OUTPUT ;
    USE SIGNAL ;
    PORT
      LAYER M4 ;
        RECT  86.316 100.752 86.4 100.776 ;
    END
  END rx_d[271]
  PIN rx_d[272]
    DIRECTION OUTPUT ;
    USE SIGNAL ;
    PORT
      LAYER M4 ;
        RECT  86.316 101.04 86.4 101.064 ;
    END
  END rx_d[272]
  PIN rx_d[273]
    DIRECTION OUTPUT ;
    USE SIGNAL ;
    PORT
      LAYER M4 ;
        RECT  86.316 101.376 86.4 101.4 ;
    END
  END rx_d[273]
  PIN rx_d[274]
    DIRECTION OUTPUT ;
    USE SIGNAL ;
    PORT
      LAYER M4 ;
        RECT  86.316 101.664 86.4 101.688 ;
    END
  END rx_d[274]
  PIN rx_d[275]
    DIRECTION OUTPUT ;
    USE SIGNAL ;
    PORT
      LAYER M4 ;
        RECT  86.316 102 86.4 102.024 ;
    END
  END rx_d[275]
  PIN rx_d[276]
    DIRECTION OUTPUT ;
    USE SIGNAL ;
    PORT
      LAYER M4 ;
        RECT  86.316 102.288 86.4 102.312 ;
    END
  END rx_d[276]
  PIN rx_d[277]
    DIRECTION OUTPUT ;
    USE SIGNAL ;
    PORT
      LAYER M4 ;
        RECT  86.316 102.576 86.4 102.6 ;
    END
  END rx_d[277]
  PIN rx_d[278]
    DIRECTION OUTPUT ;
    USE SIGNAL ;
    PORT
      LAYER M4 ;
        RECT  86.316 102.912 86.4 102.936 ;
    END
  END rx_d[278]
  PIN rx_d[279]
    DIRECTION OUTPUT ;
    USE SIGNAL ;
    PORT
      LAYER M4 ;
        RECT  86.316 103.2 86.4 103.224 ;
    END
  END rx_d[279]
  PIN rx_d[27]
    DIRECTION OUTPUT ;
    USE SIGNAL ;
    PORT
      LAYER M4 ;
        RECT  86.316 25.728 86.4 25.752 ;
    END
  END rx_d[27]
  PIN rx_d[280]
    DIRECTION OUTPUT ;
    USE SIGNAL ;
    PORT
      LAYER M4 ;
        RECT  86.316 103.536 86.4 103.56 ;
    END
  END rx_d[280]
  PIN rx_d[281]
    DIRECTION OUTPUT ;
    USE SIGNAL ;
    PORT
      LAYER M4 ;
        RECT  86.316 103.824 86.4 103.848 ;
    END
  END rx_d[281]
  PIN rx_d[282]
    DIRECTION OUTPUT ;
    USE SIGNAL ;
    PORT
      LAYER M4 ;
        RECT  86.316 104.16 86.4 104.184 ;
    END
  END rx_d[282]
  PIN rx_d[283]
    DIRECTION OUTPUT ;
    USE SIGNAL ;
    PORT
      LAYER M4 ;
        RECT  86.316 104.448 86.4 104.472 ;
    END
  END rx_d[283]
  PIN rx_d[284]
    DIRECTION OUTPUT ;
    USE SIGNAL ;
    PORT
      LAYER M4 ;
        RECT  86.316 104.736 86.4 104.76 ;
    END
  END rx_d[284]
  PIN rx_d[285]
    DIRECTION OUTPUT ;
    USE SIGNAL ;
    PORT
      LAYER M4 ;
        RECT  86.316 105.072 86.4 105.096 ;
    END
  END rx_d[285]
  PIN rx_d[286]
    DIRECTION OUTPUT ;
    USE SIGNAL ;
    PORT
      LAYER M4 ;
        RECT  86.316 105.36 86.4 105.384 ;
    END
  END rx_d[286]
  PIN rx_d[287]
    DIRECTION OUTPUT ;
    USE SIGNAL ;
    PORT
      LAYER M4 ;
        RECT  86.316 105.696 86.4 105.72 ;
    END
  END rx_d[287]
  PIN rx_d[28]
    DIRECTION OUTPUT ;
    USE SIGNAL ;
    PORT
      LAYER M4 ;
        RECT  86.316 26.016 86.4 26.04 ;
    END
  END rx_d[28]
  PIN rx_d[29]
    DIRECTION OUTPUT ;
    USE SIGNAL ;
    PORT
      LAYER M4 ;
        RECT  86.316 26.352 86.4 26.376 ;
    END
  END rx_d[29]
  PIN rx_d[2]
    DIRECTION OUTPUT ;
    USE SIGNAL ;
    PORT
      LAYER M4 ;
        RECT  86.316 18.048 86.4 18.072 ;
    END
  END rx_d[2]
  PIN rx_d[30]
    DIRECTION OUTPUT ;
    USE SIGNAL ;
    PORT
      LAYER M4 ;
        RECT  86.316 26.64 86.4 26.664 ;
    END
  END rx_d[30]
  PIN rx_d[31]
    DIRECTION OUTPUT ;
    USE SIGNAL ;
    PORT
      LAYER M4 ;
        RECT  86.316 26.976 86.4 27 ;
    END
  END rx_d[31]
  PIN rx_d[32]
    DIRECTION OUTPUT ;
    USE SIGNAL ;
    PORT
      LAYER M4 ;
        RECT  86.316 27.264 86.4 27.288 ;
    END
  END rx_d[32]
  PIN rx_d[33]
    DIRECTION OUTPUT ;
    USE SIGNAL ;
    PORT
      LAYER M4 ;
        RECT  86.316 27.552 86.4 27.576 ;
    END
  END rx_d[33]
  PIN rx_d[34]
    DIRECTION OUTPUT ;
    USE SIGNAL ;
    PORT
      LAYER M4 ;
        RECT  86.316 27.888 86.4 27.912 ;
    END
  END rx_d[34]
  PIN rx_d[35]
    DIRECTION OUTPUT ;
    USE SIGNAL ;
    PORT
      LAYER M4 ;
        RECT  86.316 28.176 86.4 28.2 ;
    END
  END rx_d[35]
  PIN rx_d[36]
    DIRECTION OUTPUT ;
    USE SIGNAL ;
    PORT
      LAYER M4 ;
        RECT  86.316 28.512 86.4 28.536 ;
    END
  END rx_d[36]
  PIN rx_d[37]
    DIRECTION OUTPUT ;
    USE SIGNAL ;
    PORT
      LAYER M4 ;
        RECT  86.316 28.8 86.4 28.824 ;
    END
  END rx_d[37]
  PIN rx_d[38]
    DIRECTION OUTPUT ;
    USE SIGNAL ;
    PORT
      LAYER M4 ;
        RECT  86.316 29.088 86.4 29.112 ;
    END
  END rx_d[38]
  PIN rx_d[39]
    DIRECTION OUTPUT ;
    USE SIGNAL ;
    PORT
      LAYER M4 ;
        RECT  86.316 29.424 86.4 29.448 ;
    END
  END rx_d[39]
  PIN rx_d[3]
    DIRECTION OUTPUT ;
    USE SIGNAL ;
    PORT
      LAYER M4 ;
        RECT  86.316 18.336 86.4 18.36 ;
    END
  END rx_d[3]
  PIN rx_d[40]
    DIRECTION OUTPUT ;
    USE SIGNAL ;
    PORT
      LAYER M4 ;
        RECT  86.316 29.712 86.4 29.736 ;
    END
  END rx_d[40]
  PIN rx_d[41]
    DIRECTION OUTPUT ;
    USE SIGNAL ;
    PORT
      LAYER M4 ;
        RECT  86.316 30.048 86.4 30.072 ;
    END
  END rx_d[41]
  PIN rx_d[42]
    DIRECTION OUTPUT ;
    USE SIGNAL ;
    PORT
      LAYER M4 ;
        RECT  86.316 30.336 86.4 30.36 ;
    END
  END rx_d[42]
  PIN rx_d[43]
    DIRECTION OUTPUT ;
    USE SIGNAL ;
    PORT
      LAYER M4 ;
        RECT  86.316 30.624 86.4 30.648 ;
    END
  END rx_d[43]
  PIN rx_d[44]
    DIRECTION OUTPUT ;
    USE SIGNAL ;
    PORT
      LAYER M4 ;
        RECT  86.316 30.96 86.4 30.984 ;
    END
  END rx_d[44]
  PIN rx_d[45]
    DIRECTION OUTPUT ;
    USE SIGNAL ;
    PORT
      LAYER M4 ;
        RECT  86.316 31.248 86.4 31.272 ;
    END
  END rx_d[45]
  PIN rx_d[46]
    DIRECTION OUTPUT ;
    USE SIGNAL ;
    PORT
      LAYER M4 ;
        RECT  86.316 31.584 86.4 31.608 ;
    END
  END rx_d[46]
  PIN rx_d[47]
    DIRECTION OUTPUT ;
    USE SIGNAL ;
    PORT
      LAYER M4 ;
        RECT  86.316 31.872 86.4 31.896 ;
    END
  END rx_d[47]
  PIN rx_d[48]
    DIRECTION OUTPUT ;
    USE SIGNAL ;
    PORT
      LAYER M4 ;
        RECT  86.316 32.16 86.4 32.184 ;
    END
  END rx_d[48]
  PIN rx_d[49]
    DIRECTION OUTPUT ;
    USE SIGNAL ;
    PORT
      LAYER M4 ;
        RECT  86.316 32.496 86.4 32.52 ;
    END
  END rx_d[49]
  PIN rx_d[4]
    DIRECTION OUTPUT ;
    USE SIGNAL ;
    PORT
      LAYER M4 ;
        RECT  86.316 18.672 86.4 18.696 ;
    END
  END rx_d[4]
  PIN rx_d[50]
    DIRECTION OUTPUT ;
    USE SIGNAL ;
    PORT
      LAYER M4 ;
        RECT  86.316 32.784 86.4 32.808 ;
    END
  END rx_d[50]
  PIN rx_d[51]
    DIRECTION OUTPUT ;
    USE SIGNAL ;
    PORT
      LAYER M4 ;
        RECT  86.316 33.12 86.4 33.144 ;
    END
  END rx_d[51]
  PIN rx_d[52]
    DIRECTION OUTPUT ;
    USE SIGNAL ;
    PORT
      LAYER M4 ;
        RECT  86.316 33.408 86.4 33.432 ;
    END
  END rx_d[52]
  PIN rx_d[53]
    DIRECTION OUTPUT ;
    USE SIGNAL ;
    PORT
      LAYER M4 ;
        RECT  86.316 33.696 86.4 33.72 ;
    END
  END rx_d[53]
  PIN rx_d[54]
    DIRECTION OUTPUT ;
    USE SIGNAL ;
    PORT
      LAYER M4 ;
        RECT  86.316 34.032 86.4 34.056 ;
    END
  END rx_d[54]
  PIN rx_d[55]
    DIRECTION OUTPUT ;
    USE SIGNAL ;
    PORT
      LAYER M4 ;
        RECT  86.316 34.32 86.4 34.344 ;
    END
  END rx_d[55]
  PIN rx_d[56]
    DIRECTION OUTPUT ;
    USE SIGNAL ;
    PORT
      LAYER M4 ;
        RECT  86.316 34.656 86.4 34.68 ;
    END
  END rx_d[56]
  PIN rx_d[57]
    DIRECTION OUTPUT ;
    USE SIGNAL ;
    PORT
      LAYER M4 ;
        RECT  86.316 34.944 86.4 34.968 ;
    END
  END rx_d[57]
  PIN rx_d[58]
    DIRECTION OUTPUT ;
    USE SIGNAL ;
    PORT
      LAYER M4 ;
        RECT  86.316 35.28 86.4 35.304 ;
    END
  END rx_d[58]
  PIN rx_d[59]
    DIRECTION OUTPUT ;
    USE SIGNAL ;
    PORT
      LAYER M4 ;
        RECT  86.316 35.568 86.4 35.592 ;
    END
  END rx_d[59]
  PIN rx_d[5]
    DIRECTION OUTPUT ;
    USE SIGNAL ;
    PORT
      LAYER M4 ;
        RECT  86.316 18.96 86.4 18.984 ;
    END
  END rx_d[5]
  PIN rx_d[60]
    DIRECTION OUTPUT ;
    USE SIGNAL ;
    PORT
      LAYER M4 ;
        RECT  86.316 35.856 86.4 35.88 ;
    END
  END rx_d[60]
  PIN rx_d[61]
    DIRECTION OUTPUT ;
    USE SIGNAL ;
    PORT
      LAYER M4 ;
        RECT  86.316 36.192 86.4 36.216 ;
    END
  END rx_d[61]
  PIN rx_d[62]
    DIRECTION OUTPUT ;
    USE SIGNAL ;
    PORT
      LAYER M4 ;
        RECT  86.316 36.48 86.4 36.504 ;
    END
  END rx_d[62]
  PIN rx_d[63]
    DIRECTION OUTPUT ;
    USE SIGNAL ;
    PORT
      LAYER M4 ;
        RECT  86.316 36.816 86.4 36.84 ;
    END
  END rx_d[63]
  PIN rx_d[64]
    DIRECTION OUTPUT ;
    USE SIGNAL ;
    PORT
      LAYER M4 ;
        RECT  86.316 37.104 86.4 37.128 ;
    END
  END rx_d[64]
  PIN rx_d[65]
    DIRECTION OUTPUT ;
    USE SIGNAL ;
    PORT
      LAYER M4 ;
        RECT  86.316 37.392 86.4 37.416 ;
    END
  END rx_d[65]
  PIN rx_d[66]
    DIRECTION OUTPUT ;
    USE SIGNAL ;
    PORT
      LAYER M4 ;
        RECT  86.316 37.728 86.4 37.752 ;
    END
  END rx_d[66]
  PIN rx_d[67]
    DIRECTION OUTPUT ;
    USE SIGNAL ;
    PORT
      LAYER M4 ;
        RECT  86.316 38.016 86.4 38.04 ;
    END
  END rx_d[67]
  PIN rx_d[68]
    DIRECTION OUTPUT ;
    USE SIGNAL ;
    PORT
      LAYER M4 ;
        RECT  86.316 38.352 86.4 38.376 ;
    END
  END rx_d[68]
  PIN rx_d[69]
    DIRECTION OUTPUT ;
    USE SIGNAL ;
    PORT
      LAYER M4 ;
        RECT  86.316 38.64 86.4 38.664 ;
    END
  END rx_d[69]
  PIN rx_d[6]
    DIRECTION OUTPUT ;
    USE SIGNAL ;
    PORT
      LAYER M4 ;
        RECT  86.316 19.248 86.4 19.272 ;
    END
  END rx_d[6]
  PIN rx_d[70]
    DIRECTION OUTPUT ;
    USE SIGNAL ;
    PORT
      LAYER M4 ;
        RECT  86.316 38.928 86.4 38.952 ;
    END
  END rx_d[70]
  PIN rx_d[71]
    DIRECTION OUTPUT ;
    USE SIGNAL ;
    PORT
      LAYER M4 ;
        RECT  86.316 39.264 86.4 39.288 ;
    END
  END rx_d[71]
  PIN rx_d[72]
    DIRECTION OUTPUT ;
    USE SIGNAL ;
    PORT
      LAYER M4 ;
        RECT  86.316 39.552 86.4 39.576 ;
    END
  END rx_d[72]
  PIN rx_d[73]
    DIRECTION OUTPUT ;
    USE SIGNAL ;
    PORT
      LAYER M4 ;
        RECT  86.316 39.888 86.4 39.912 ;
    END
  END rx_d[73]
  PIN rx_d[74]
    DIRECTION OUTPUT ;
    USE SIGNAL ;
    PORT
      LAYER M4 ;
        RECT  86.316 40.176 86.4 40.2 ;
    END
  END rx_d[74]
  PIN rx_d[75]
    DIRECTION OUTPUT ;
    USE SIGNAL ;
    PORT
      LAYER M4 ;
        RECT  86.316 40.464 86.4 40.488 ;
    END
  END rx_d[75]
  PIN rx_d[76]
    DIRECTION OUTPUT ;
    USE SIGNAL ;
    PORT
      LAYER M4 ;
        RECT  86.316 40.8 86.4 40.824 ;
    END
  END rx_d[76]
  PIN rx_d[77]
    DIRECTION OUTPUT ;
    USE SIGNAL ;
    PORT
      LAYER M4 ;
        RECT  86.316 41.088 86.4 41.112 ;
    END
  END rx_d[77]
  PIN rx_d[78]
    DIRECTION OUTPUT ;
    USE SIGNAL ;
    PORT
      LAYER M4 ;
        RECT  86.316 41.424 86.4 41.448 ;
    END
  END rx_d[78]
  PIN rx_d[79]
    DIRECTION OUTPUT ;
    USE SIGNAL ;
    PORT
      LAYER M4 ;
        RECT  86.316 41.712 86.4 41.736 ;
    END
  END rx_d[79]
  PIN rx_d[7]
    DIRECTION OUTPUT ;
    USE SIGNAL ;
    PORT
      LAYER M4 ;
        RECT  86.316 19.584 86.4 19.608 ;
    END
  END rx_d[7]
  PIN rx_d[80]
    DIRECTION OUTPUT ;
    USE SIGNAL ;
    PORT
      LAYER M4 ;
        RECT  86.316 42 86.4 42.024 ;
    END
  END rx_d[80]
  PIN rx_d[81]
    DIRECTION OUTPUT ;
    USE SIGNAL ;
    PORT
      LAYER M4 ;
        RECT  86.316 42.336 86.4 42.36 ;
    END
  END rx_d[81]
  PIN rx_d[82]
    DIRECTION OUTPUT ;
    USE SIGNAL ;
    PORT
      LAYER M4 ;
        RECT  86.316 42.624 86.4 42.648 ;
    END
  END rx_d[82]
  PIN rx_d[83]
    DIRECTION OUTPUT ;
    USE SIGNAL ;
    PORT
      LAYER M4 ;
        RECT  86.316 42.96 86.4 42.984 ;
    END
  END rx_d[83]
  PIN rx_d[84]
    DIRECTION OUTPUT ;
    USE SIGNAL ;
    PORT
      LAYER M4 ;
        RECT  86.316 43.248 86.4 43.272 ;
    END
  END rx_d[84]
  PIN rx_d[85]
    DIRECTION OUTPUT ;
    USE SIGNAL ;
    PORT
      LAYER M4 ;
        RECT  86.316 43.536 86.4 43.56 ;
    END
  END rx_d[85]
  PIN rx_d[86]
    DIRECTION OUTPUT ;
    USE SIGNAL ;
    PORT
      LAYER M4 ;
        RECT  86.316 43.872 86.4 43.896 ;
    END
  END rx_d[86]
  PIN rx_d[87]
    DIRECTION OUTPUT ;
    USE SIGNAL ;
    PORT
      LAYER M4 ;
        RECT  86.316 44.16 86.4 44.184 ;
    END
  END rx_d[87]
  PIN rx_d[88]
    DIRECTION OUTPUT ;
    USE SIGNAL ;
    PORT
      LAYER M4 ;
        RECT  86.316 44.496 86.4 44.52 ;
    END
  END rx_d[88]
  PIN rx_d[89]
    DIRECTION OUTPUT ;
    USE SIGNAL ;
    PORT
      LAYER M4 ;
        RECT  86.316 44.784 86.4 44.808 ;
    END
  END rx_d[89]
  PIN rx_d[8]
    DIRECTION OUTPUT ;
    USE SIGNAL ;
    PORT
      LAYER M4 ;
        RECT  86.316 19.872 86.4 19.896 ;
    END
  END rx_d[8]
  PIN rx_d[90]
    DIRECTION OUTPUT ;
    USE SIGNAL ;
    PORT
      LAYER M4 ;
        RECT  86.316 45.12 86.4 45.144 ;
    END
  END rx_d[90]
  PIN rx_d[91]
    DIRECTION OUTPUT ;
    USE SIGNAL ;
    PORT
      LAYER M4 ;
        RECT  86.316 45.408 86.4 45.432 ;
    END
  END rx_d[91]
  PIN rx_d[92]
    DIRECTION OUTPUT ;
    USE SIGNAL ;
    PORT
      LAYER M4 ;
        RECT  86.316 45.696 86.4 45.72 ;
    END
  END rx_d[92]
  PIN rx_d[93]
    DIRECTION OUTPUT ;
    USE SIGNAL ;
    PORT
      LAYER M4 ;
        RECT  86.316 46.032 86.4 46.056 ;
    END
  END rx_d[93]
  PIN rx_d[94]
    DIRECTION OUTPUT ;
    USE SIGNAL ;
    PORT
      LAYER M4 ;
        RECT  86.316 46.32 86.4 46.344 ;
    END
  END rx_d[94]
  PIN rx_d[95]
    DIRECTION OUTPUT ;
    USE SIGNAL ;
    PORT
      LAYER M4 ;
        RECT  86.316 46.656 86.4 46.68 ;
    END
  END rx_d[95]
  PIN rx_d[96]
    DIRECTION OUTPUT ;
    USE SIGNAL ;
    PORT
      LAYER M4 ;
        RECT  86.316 46.944 86.4 46.968 ;
    END
  END rx_d[96]
  PIN rx_d[97]
    DIRECTION OUTPUT ;
    USE SIGNAL ;
    PORT
      LAYER M4 ;
        RECT  86.316 47.232 86.4 47.256 ;
    END
  END rx_d[97]
  PIN rx_d[98]
    DIRECTION OUTPUT ;
    USE SIGNAL ;
    PORT
      LAYER M4 ;
        RECT  86.316 47.568 86.4 47.592 ;
    END
  END rx_d[98]
  PIN rx_d[99]
    DIRECTION OUTPUT ;
    USE SIGNAL ;
    PORT
      LAYER M4 ;
        RECT  86.316 47.856 86.4 47.88 ;
    END
  END rx_d[99]
  PIN rx_d[9]
    DIRECTION OUTPUT ;
    USE SIGNAL ;
    PORT
      LAYER M4 ;
        RECT  86.316 20.208 86.4 20.232 ;
    END
  END rx_d[9]
  PIN rx_v
    DIRECTION OUTPUT ;
    USE SIGNAL ;
    PORT
      LAYER M4 ;
        RECT  86.316 7.008 86.4 7.032 ;
    END
    PORT
      LAYER M4 ;
        RECT  86.281 7.008 86.364 7.032 ;
    END
  END rx_v
  PIN tvk[0]
    DIRECTION OUTPUT ;
    USE SIGNAL ;
    PORT
      LAYER M5 ;
        RECT  28.896 0 28.92 0.084 ;
    END
    PORT
      LAYER M5 ;
        RECT  28.896 0.016 28.92 0.611 ;
    END
  END tvk[0]
  PIN tvk[1]
    DIRECTION OUTPUT ;
    USE SIGNAL ;
    PORT
      LAYER M5 ;
        RECT  30.48 0 30.504 0.084 ;
    END
    PORT
      LAYER M5 ;
        RECT  30.48 0.016 30.504 0.131 ;
    END
  END tvk[1]
  PIN tvk[2]
    DIRECTION OUTPUT ;
    USE SIGNAL ;
    PORT
      LAYER M5 ;
        RECT  32.112 0 32.136 0.084 ;
    END
    PORT
      LAYER M5 ;
        RECT  32.112 0.016 32.136 0.131 ;
    END
  END tvk[2]
  PIN tvk[3]
    DIRECTION OUTPUT ;
    USE SIGNAL ;
    PORT
      LAYER M5 ;
        RECT  33.744 0 33.768 0.084 ;
    END
    PORT
      LAYER M5 ;
        RECT  33.744 0.016 33.768 0.131 ;
    END
  END tvk[3]
  PIN tx_v
    DIRECTION INPUT ;
    USE SIGNAL ;
    PORT
      LAYER M4 ;
        RECT  86.316 2.688 86.4 2.712 ;
    END
    PORT
      LAYER M4 ;
        RECT  84.877 2.688 86.364 2.712 ;
    END
  END tx_v
  PIN VDD
    DIRECTION INOUT ;
    USE POWER ;
    PORT
      LAYER M5 ;
        RECT  83.592 2.151 83.712 105.849 ;
        RECT  78.192 2.151 78.312 105.849 ;
        RECT  72.792 2.151 72.912 105.849 ;
        RECT  67.392 2.151 67.512 105.849 ;
        RECT  61.992 2.151 62.112 105.849 ;
        RECT  56.592 2.151 56.712 105.849 ;
        RECT  51.192 2.151 51.312 105.849 ;
        RECT  45.792 2.151 45.912 105.849 ;
        RECT  40.392 2.151 40.512 105.849 ;
        RECT  34.992 2.151 35.112 105.849 ;
        RECT  29.592 2.151 29.712 105.849 ;
        RECT  24.192 2.151 24.312 105.849 ;
        RECT  18.792 2.151 18.912 105.849 ;
        RECT  13.392 2.151 13.512 105.849 ;
        RECT  7.992 2.151 8.112 105.849 ;
        RECT  2.592 2.151 2.712 105.849 ;
    END
  END VDD
  PIN VSS
    DIRECTION INOUT ;
    USE GROUND ;
    PORT
      LAYER M5 ;
        RECT  83.4 2.137 83.52 105.863 ;
        RECT  78 2.137 78.12 105.863 ;
        RECT  72.6 2.137 72.72 105.863 ;
        RECT  67.2 2.137 67.32 105.863 ;
        RECT  61.8 2.137 61.92 105.863 ;
        RECT  56.4 2.137 56.52 105.863 ;
        RECT  51 2.137 51.12 105.863 ;
        RECT  45.6 2.137 45.72 105.863 ;
        RECT  40.2 2.137 40.32 105.863 ;
        RECT  34.8 2.137 34.92 105.863 ;
        RECT  29.4 2.137 29.52 105.863 ;
        RECT  24 2.137 24.12 105.863 ;
        RECT  18.6 2.137 18.72 105.863 ;
        RECT  13.2 2.137 13.32 105.863 ;
        RECT  7.8 2.137 7.92 105.863 ;
        RECT  2.4 2.137 2.52 105.863 ;
    END
  END VSS
  # OT_OBS_CLOSED layer=M5 d_um=1.536 added=25
  OBS
    LAYER RVTN ;
     RECT  2.16 2.16 84.24 2.295 ;
     RECT  2.16 2.565 84.24 2.835 ;
     RECT  2.16 3.105 84.24 3.375 ;
     RECT  2.16 3.645 84.24 3.915 ;
     RECT  2.16 4.185 84.24 4.455 ;
     RECT  2.16 4.725 84.24 4.995 ;
     RECT  2.16 5.265 84.24 5.535 ;
     RECT  2.16 5.805 84.24 6.075 ;
     RECT  2.16 6.345 84.24 6.615 ;
     RECT  2.16 6.885 84.24 7.155 ;
     RECT  2.16 7.425 84.24 7.695 ;
     RECT  2.16 7.965 84.24 8.235 ;
     RECT  2.16 8.505 84.24 8.775 ;
     RECT  2.16 9.045 84.24 9.315 ;
     RECT  2.16 9.585 84.24 9.855 ;
     RECT  2.16 10.125 84.24 10.395 ;
     RECT  2.16 10.665 84.24 10.935 ;
     RECT  2.16 11.205 84.24 11.475 ;
     RECT  2.16 11.745 84.24 12.015 ;
     RECT  2.16 12.285 84.24 12.555 ;
     RECT  2.16 12.825 84.24 13.095 ;
     RECT  2.16 13.365 84.24 13.635 ;
     RECT  2.16 13.905 84.24 14.175 ;
     RECT  2.16 14.445 84.24 14.715 ;
     RECT  2.16 14.985 84.24 15.255 ;
     RECT  2.16 15.525 84.24 15.795 ;
     RECT  2.16 16.065 84.24 16.335 ;
     RECT  2.16 16.605 84.24 16.875 ;
     RECT  2.16 17.145 84.24 17.415 ;
     RECT  2.16 17.685 84.24 17.955 ;
     RECT  2.16 18.225 84.24 18.495 ;
     RECT  2.16 18.765 84.24 19.035 ;
     RECT  2.16 19.305 84.24 19.575 ;
     RECT  2.16 19.845 84.24 20.115 ;
     RECT  2.16 20.385 84.24 20.655 ;
     RECT  2.16 20.925 84.24 21.195 ;
     RECT  2.16 21.465 84.24 21.735 ;
     RECT  2.16 22.005 84.24 22.275 ;
     RECT  2.16 22.545 84.24 22.815 ;
     RECT  2.16 23.085 84.24 23.355 ;
     RECT  2.16 23.625 84.24 23.895 ;
     RECT  2.16 24.165 84.24 24.435 ;
     RECT  2.16 24.705 84.24 24.975 ;
     RECT  2.16 25.245 84.24 25.515 ;
     RECT  2.16 25.785 84.24 26.055 ;
     RECT  2.16 26.325 84.24 26.595 ;
     RECT  2.16 26.865 84.24 27.135 ;
     RECT  2.16 27.405 84.24 27.675 ;
     RECT  2.16 27.945 84.24 28.215 ;
     RECT  2.16 28.485 84.24 28.755 ;
     RECT  2.16 29.025 84.24 29.295 ;
     RECT  2.16 29.565 84.24 29.835 ;
     RECT  2.16 30.105 84.24 30.375 ;
     RECT  2.16 30.645 84.24 30.915 ;
     RECT  2.16 31.185 84.24 31.455 ;
     RECT  2.16 31.725 84.24 31.995 ;
     RECT  2.16 32.265 84.24 32.535 ;
     RECT  2.16 32.805 84.24 33.075 ;
     RECT  2.16 33.345 84.24 33.615 ;
     RECT  2.16 33.885 84.24 34.155 ;
     RECT  2.16 34.425 84.24 34.695 ;
     RECT  2.16 34.965 84.24 35.235 ;
     RECT  2.16 35.505 84.24 35.775 ;
     RECT  2.16 36.045 84.24 36.315 ;
     RECT  2.16 36.585 84.24 36.855 ;
     RECT  2.16 37.125 84.24 37.395 ;
     RECT  2.16 37.665 84.24 37.935 ;
     RECT  2.16 38.205 84.24 38.475 ;
     RECT  2.16 38.745 84.24 39.015 ;
     RECT  2.16 39.285 84.24 39.555 ;
     RECT  2.16 39.825 84.24 40.095 ;
     RECT  2.16 40.365 84.24 40.635 ;
     RECT  2.16 40.905 84.24 41.175 ;
     RECT  2.16 41.445 84.24 41.715 ;
     RECT  2.16 41.985 84.24 42.255 ;
     RECT  2.16 42.525 84.24 42.795 ;
     RECT  2.16 43.065 84.24 43.335 ;
     RECT  2.16 43.605 84.24 43.875 ;
     RECT  2.16 44.145 84.24 44.415 ;
     RECT  2.16 44.685 84.24 44.955 ;
     RECT  2.16 45.225 84.24 45.495 ;
     RECT  2.16 45.765 84.24 46.035 ;
     RECT  2.16 46.305 84.24 46.575 ;
     RECT  2.16 46.845 84.24 47.115 ;
     RECT  2.16 47.385 84.24 47.655 ;
     RECT  2.16 47.925 84.24 48.195 ;
     RECT  2.16 48.465 84.24 48.735 ;
     RECT  2.16 49.005 84.24 49.275 ;
     RECT  2.16 49.545 84.24 49.815 ;
     RECT  2.16 50.085 84.24 50.355 ;
     RECT  2.16 50.625 84.24 50.895 ;
     RECT  2.16 51.165 84.24 51.435 ;
     RECT  2.16 51.705 84.24 51.975 ;
     RECT  2.16 52.245 84.24 52.515 ;
     RECT  2.16 52.785 84.24 53.055 ;
     RECT  2.16 53.325 84.24 53.595 ;
     RECT  2.16 53.865 84.24 54.135 ;
     RECT  2.16 54.405 84.24 54.675 ;
     RECT  2.16 54.945 84.24 55.215 ;
     RECT  2.16 55.485 84.24 55.755 ;
     RECT  2.16 56.025 84.24 56.295 ;
     RECT  2.16 56.565 84.24 56.835 ;
     RECT  2.16 57.105 84.24 57.375 ;
     RECT  2.16 57.645 84.24 57.915 ;
     RECT  2.16 58.185 84.24 58.455 ;
     RECT  2.16 58.725 84.24 58.995 ;
     RECT  2.16 59.265 84.24 59.535 ;
     RECT  2.16 59.805 84.24 60.075 ;
     RECT  2.16 60.345 84.24 60.615 ;
     RECT  2.16 60.885 84.24 61.155 ;
     RECT  2.16 61.425 84.24 61.695 ;
     RECT  2.16 61.965 84.24 62.235 ;
     RECT  2.16 62.505 84.24 62.775 ;
     RECT  2.16 63.045 84.24 63.315 ;
     RECT  2.16 63.585 84.24 63.855 ;
     RECT  2.16 64.125 84.24 64.395 ;
     RECT  2.16 64.665 84.24 64.935 ;
     RECT  2.16 65.205 84.24 65.475 ;
     RECT  2.16 65.745 84.24 66.015 ;
     RECT  2.16 66.285 84.24 66.555 ;
     RECT  2.16 66.825 84.24 67.095 ;
     RECT  2.16 67.365 84.24 67.635 ;
     RECT  2.16 67.905 84.24 68.175 ;
     RECT  2.16 68.445 84.24 68.715 ;
     RECT  2.16 68.985 84.24 69.255 ;
     RECT  2.16 69.525 84.24 69.795 ;
     RECT  2.16 70.065 84.24 70.335 ;
     RECT  2.16 70.605 84.24 70.875 ;
     RECT  2.16 71.145 84.24 71.415 ;
     RECT  2.16 71.685 84.24 71.955 ;
     RECT  2.16 72.225 84.24 72.495 ;
     RECT  2.16 72.765 84.24 73.035 ;
     RECT  2.16 73.305 84.24 73.575 ;
     RECT  2.16 73.845 84.24 74.115 ;
     RECT  2.16 74.385 84.24 74.655 ;
     RECT  2.16 74.925 84.24 75.195 ;
     RECT  2.16 75.465 84.24 75.735 ;
     RECT  2.16 76.005 84.24 76.275 ;
     RECT  2.16 76.545 84.24 76.815 ;
     RECT  2.16 77.085 84.24 77.355 ;
     RECT  2.16 77.625 84.24 77.895 ;
     RECT  2.16 78.165 84.24 78.435 ;
     RECT  2.16 78.705 84.24 78.975 ;
     RECT  2.16 79.245 84.24 79.515 ;
     RECT  2.16 79.785 84.24 80.055 ;
     RECT  2.16 80.325 84.24 80.595 ;
     RECT  2.16 80.865 84.24 81.135 ;
     RECT  2.16 81.405 84.24 81.675 ;
     RECT  2.16 81.945 84.24 82.215 ;
     RECT  2.16 82.485 84.24 82.755 ;
     RECT  2.16 83.025 84.24 83.295 ;
     RECT  2.16 83.565 84.24 83.835 ;
     RECT  2.16 84.105 84.24 84.375 ;
     RECT  2.16 84.645 84.24 84.915 ;
     RECT  2.16 85.185 84.24 85.455 ;
     RECT  2.16 85.725 84.24 85.995 ;
     RECT  2.16 86.265 84.24 86.535 ;
     RECT  2.16 86.805 84.24 87.075 ;
     RECT  2.16 87.345 84.24 87.615 ;
     RECT  2.16 87.885 84.24 88.155 ;
     RECT  2.16 88.425 84.24 88.695 ;
     RECT  2.16 88.965 84.24 89.235 ;
     RECT  2.16 89.505 84.24 89.775 ;
     RECT  2.16 90.045 84.24 90.315 ;
     RECT  2.16 90.585 84.24 90.855 ;
     RECT  2.16 91.125 84.24 91.395 ;
     RECT  2.16 91.665 84.24 91.935 ;
     RECT  2.16 92.205 84.24 92.475 ;
     RECT  2.16 92.745 84.24 93.015 ;
     RECT  2.16 93.285 84.24 93.555 ;
     RECT  2.16 93.825 84.24 94.095 ;
     RECT  2.16 94.365 84.24 94.635 ;
     RECT  2.16 94.905 84.24 95.175 ;
     RECT  2.16 95.445 84.24 95.715 ;
     RECT  2.16 95.985 84.24 96.255 ;
     RECT  2.16 96.525 84.24 96.795 ;
     RECT  2.16 97.065 84.24 97.335 ;
     RECT  2.16 97.605 84.24 97.875 ;
     RECT  2.16 98.145 84.24 98.415 ;
     RECT  2.16 98.685 84.24 98.955 ;
     RECT  2.16 99.225 84.24 99.495 ;
     RECT  2.16 99.765 84.24 100.035 ;
     RECT  2.16 100.305 84.24 100.575 ;
     RECT  2.16 100.845 84.24 101.115 ;
     RECT  2.16 101.385 84.24 101.655 ;
     RECT  2.16 101.925 84.24 102.195 ;
     RECT  2.16 102.465 84.24 102.735 ;
     RECT  2.16 103.005 84.24 103.275 ;
     RECT  2.16 103.545 84.24 103.815 ;
     RECT  2.16 104.085 84.24 104.355 ;
     RECT  2.16 104.625 84.24 104.895 ;
     RECT  2.16 105.165 84.24 105.435 ;
     RECT  2.16 105.705 84.24 105.84 ;
    LAYER RVTP ;
     RECT  2.16 2.295 84.24 2.565 ;
     RECT  2.16 2.835 84.24 3.105 ;
     RECT  2.16 3.375 84.24 3.645 ;
     RECT  2.16 3.915 84.24 4.185 ;
     RECT  2.16 4.455 84.24 4.725 ;
     RECT  2.16 4.995 84.24 5.265 ;
     RECT  2.16 5.535 84.24 5.805 ;
     RECT  2.16 6.075 84.24 6.345 ;
     RECT  2.16 6.615 84.24 6.885 ;
     RECT  2.16 7.155 84.24 7.425 ;
     RECT  2.16 7.695 84.24 7.965 ;
     RECT  2.16 8.235 84.24 8.505 ;
     RECT  2.16 8.775 84.24 9.045 ;
     RECT  2.16 9.315 84.24 9.585 ;
     RECT  2.16 9.855 84.24 10.125 ;
     RECT  2.16 10.395 84.24 10.665 ;
     RECT  2.16 10.935 84.24 11.205 ;
     RECT  2.16 11.475 84.24 11.745 ;
     RECT  2.16 12.015 84.24 12.285 ;
     RECT  2.16 12.555 84.24 12.825 ;
     RECT  2.16 13.095 84.24 13.365 ;
     RECT  2.16 13.635 84.24 13.905 ;
     RECT  2.16 14.175 84.24 14.445 ;
     RECT  2.16 14.715 84.24 14.985 ;
     RECT  2.16 15.255 84.24 15.525 ;
     RECT  2.16 15.795 84.24 16.065 ;
     RECT  2.16 16.335 84.24 16.605 ;
     RECT  2.16 16.875 84.24 17.145 ;
     RECT  2.16 17.415 84.24 17.685 ;
     RECT  2.16 17.955 84.24 18.225 ;
     RECT  2.16 18.495 84.24 18.765 ;
     RECT  2.16 19.035 84.24 19.305 ;
     RECT  2.16 19.575 84.24 19.845 ;
     RECT  2.16 20.115 84.24 20.385 ;
     RECT  2.16 20.655 84.24 20.925 ;
     RECT  2.16 21.195 84.24 21.465 ;
     RECT  2.16 21.735 84.24 22.005 ;
     RECT  2.16 22.275 84.24 22.545 ;
     RECT  2.16 22.815 84.24 23.085 ;
     RECT  2.16 23.355 84.24 23.625 ;
     RECT  2.16 23.895 84.24 24.165 ;
     RECT  2.16 24.435 84.24 24.705 ;
     RECT  2.16 24.975 84.24 25.245 ;
     RECT  2.16 25.515 84.24 25.785 ;
     RECT  2.16 26.055 84.24 26.325 ;
     RECT  2.16 26.595 84.24 26.865 ;
     RECT  2.16 27.135 84.24 27.405 ;
     RECT  2.16 27.675 84.24 27.945 ;
     RECT  2.16 28.215 84.24 28.485 ;
     RECT  2.16 28.755 84.24 29.025 ;
     RECT  2.16 29.295 84.24 29.565 ;
     RECT  2.16 29.835 84.24 30.105 ;
     RECT  2.16 30.375 84.24 30.645 ;
     RECT  2.16 30.915 84.24 31.185 ;
     RECT  2.16 31.455 84.24 31.725 ;
     RECT  2.16 31.995 84.24 32.265 ;
     RECT  2.16 32.535 84.24 32.805 ;
     RECT  2.16 33.075 84.24 33.345 ;
     RECT  2.16 33.615 84.24 33.885 ;
     RECT  2.16 34.155 84.24 34.425 ;
     RECT  2.16 34.695 84.24 34.965 ;
     RECT  2.16 35.235 84.24 35.505 ;
     RECT  2.16 35.775 84.24 36.045 ;
     RECT  2.16 36.315 84.24 36.585 ;
     RECT  2.16 36.855 84.24 37.125 ;
     RECT  2.16 37.395 84.24 37.665 ;
     RECT  2.16 37.935 84.24 38.205 ;
     RECT  2.16 38.475 84.24 38.745 ;
     RECT  2.16 39.015 84.24 39.285 ;
     RECT  2.16 39.555 84.24 39.825 ;
     RECT  2.16 40.095 84.24 40.365 ;
     RECT  2.16 40.635 84.24 40.905 ;
     RECT  2.16 41.175 84.24 41.445 ;
     RECT  2.16 41.715 84.24 41.985 ;
     RECT  2.16 42.255 84.24 42.525 ;
     RECT  2.16 42.795 84.24 43.065 ;
     RECT  2.16 43.335 84.24 43.605 ;
     RECT  2.16 43.875 84.24 44.145 ;
     RECT  2.16 44.415 84.24 44.685 ;
     RECT  2.16 44.955 84.24 45.225 ;
     RECT  2.16 45.495 84.24 45.765 ;
     RECT  2.16 46.035 84.24 46.305 ;
     RECT  2.16 46.575 84.24 46.845 ;
     RECT  2.16 47.115 84.24 47.385 ;
     RECT  2.16 47.655 84.24 47.925 ;
     RECT  2.16 48.195 84.24 48.465 ;
     RECT  2.16 48.735 84.24 49.005 ;
     RECT  2.16 49.275 84.24 49.545 ;
     RECT  2.16 49.815 84.24 50.085 ;
     RECT  2.16 50.355 84.24 50.625 ;
     RECT  2.16 50.895 84.24 51.165 ;
     RECT  2.16 51.435 84.24 51.705 ;
     RECT  2.16 51.975 84.24 52.245 ;
     RECT  2.16 52.515 84.24 52.785 ;
     RECT  2.16 53.055 84.24 53.325 ;
     RECT  2.16 53.595 84.24 53.865 ;
     RECT  2.16 54.135 84.24 54.405 ;
     RECT  2.16 54.675 84.24 54.945 ;
     RECT  2.16 55.215 84.24 55.485 ;
     RECT  2.16 55.755 84.24 56.025 ;
     RECT  2.16 56.295 84.24 56.565 ;
     RECT  2.16 56.835 84.24 57.105 ;
     RECT  2.16 57.375 84.24 57.645 ;
     RECT  2.16 57.915 84.24 58.185 ;
     RECT  2.16 58.455 84.24 58.725 ;
     RECT  2.16 58.995 84.24 59.265 ;
     RECT  2.16 59.535 84.24 59.805 ;
     RECT  2.16 60.075 84.24 60.345 ;
     RECT  2.16 60.615 84.24 60.885 ;
     RECT  2.16 61.155 84.24 61.425 ;
     RECT  2.16 61.695 84.24 61.965 ;
     RECT  2.16 62.235 84.24 62.505 ;
     RECT  2.16 62.775 84.24 63.045 ;
     RECT  2.16 63.315 84.24 63.585 ;
     RECT  2.16 63.855 84.24 64.125 ;
     RECT  2.16 64.395 84.24 64.665 ;
     RECT  2.16 64.935 84.24 65.205 ;
     RECT  2.16 65.475 84.24 65.745 ;
     RECT  2.16 66.015 84.24 66.285 ;
     RECT  2.16 66.555 84.24 66.825 ;
     RECT  2.16 67.095 84.24 67.365 ;
     RECT  2.16 67.635 84.24 67.905 ;
     RECT  2.16 68.175 84.24 68.445 ;
     RECT  2.16 68.715 84.24 68.985 ;
     RECT  2.16 69.255 84.24 69.525 ;
     RECT  2.16 69.795 84.24 70.065 ;
     RECT  2.16 70.335 84.24 70.605 ;
     RECT  2.16 70.875 84.24 71.145 ;
     RECT  2.16 71.415 84.24 71.685 ;
     RECT  2.16 71.955 84.24 72.225 ;
     RECT  2.16 72.495 84.24 72.765 ;
     RECT  2.16 73.035 84.24 73.305 ;
     RECT  2.16 73.575 84.24 73.845 ;
     RECT  2.16 74.115 84.24 74.385 ;
     RECT  2.16 74.655 84.24 74.925 ;
     RECT  2.16 75.195 84.24 75.465 ;
     RECT  2.16 75.735 84.24 76.005 ;
     RECT  2.16 76.275 84.24 76.545 ;
     RECT  2.16 76.815 84.24 77.085 ;
     RECT  2.16 77.355 84.24 77.625 ;
     RECT  2.16 77.895 84.24 78.165 ;
     RECT  2.16 78.435 84.24 78.705 ;
     RECT  2.16 78.975 84.24 79.245 ;
     RECT  2.16 79.515 84.24 79.785 ;
     RECT  2.16 80.055 84.24 80.325 ;
     RECT  2.16 80.595 84.24 80.865 ;
     RECT  2.16 81.135 84.24 81.405 ;
     RECT  2.16 81.675 84.24 81.945 ;
     RECT  2.16 82.215 84.24 82.485 ;
     RECT  2.16 82.755 84.24 83.025 ;
     RECT  2.16 83.295 84.24 83.565 ;
     RECT  2.16 83.835 84.24 84.105 ;
     RECT  2.16 84.375 84.24 84.645 ;
     RECT  2.16 84.915 84.24 85.185 ;
     RECT  2.16 85.455 84.24 85.725 ;
     RECT  2.16 85.995 84.24 86.265 ;
     RECT  2.16 86.535 84.24 86.805 ;
     RECT  2.16 87.075 84.24 87.345 ;
     RECT  2.16 87.615 84.24 87.885 ;
     RECT  2.16 88.155 84.24 88.425 ;
     RECT  2.16 88.695 84.24 88.965 ;
     RECT  2.16 89.235 84.24 89.505 ;
     RECT  2.16 89.775 84.24 90.045 ;
     RECT  2.16 90.315 84.24 90.585 ;
     RECT  2.16 90.855 84.24 91.125 ;
     RECT  2.16 91.395 84.24 91.665 ;
     RECT  2.16 91.935 84.24 92.205 ;
     RECT  2.16 92.475 84.24 92.745 ;
     RECT  2.16 93.015 84.24 93.285 ;
     RECT  2.16 93.555 84.24 93.825 ;
     RECT  2.16 94.095 84.24 94.365 ;
     RECT  2.16 94.635 84.24 94.905 ;
     RECT  2.16 95.175 84.24 95.445 ;
     RECT  2.16 95.715 84.24 95.985 ;
     RECT  2.16 96.255 84.24 96.525 ;
     RECT  2.16 96.795 84.24 97.065 ;
     RECT  2.16 97.335 84.24 97.605 ;
     RECT  2.16 97.875 84.24 98.145 ;
     RECT  2.16 98.415 84.24 98.685 ;
     RECT  2.16 98.955 84.24 99.225 ;
     RECT  2.16 99.495 84.24 99.765 ;
     RECT  2.16 100.035 84.24 100.305 ;
     RECT  2.16 100.575 84.24 100.845 ;
     RECT  2.16 101.115 84.24 101.385 ;
     RECT  2.16 101.655 84.24 101.925 ;
     RECT  2.16 102.195 84.24 102.465 ;
     RECT  2.16 102.735 84.24 103.005 ;
     RECT  2.16 103.275 84.24 103.545 ;
     RECT  2.16 103.815 84.24 104.085 ;
     RECT  2.16 104.355 84.24 104.625 ;
     RECT  2.16 104.895 84.24 105.165 ;
     RECT  2.16 105.435 84.24 105.705 ;
    LAYER M1 ;
     RECT  2.16 2.151 84.24 105.849 ;
    LAYER M2 ;
     RECT  0.103 36.252 0.139 36.54 ;
     RECT  0.103 38.412 0.139 38.7 ;
     RECT  0.103 44.622 0.139 44.91 ;
     RECT  0.103 71.352 0.139 71.37 ;
     RECT  0.103 82.422 0.139 82.44 ;
     RECT  0.103 98.352 0.139 98.37 ;
     RECT  0.535 4.806 2.16 4.824 ;
     RECT  0.103 10.602 2.16 10.62 ;
     RECT  0.535 14.922 2.16 14.94 ;
     RECT  0.103 18.162 2.16 18.18 ;
     RECT  0.103 20.322 2.16 20.34 ;
     RECT  0.103 27.612 2.16 27.63 ;
     RECT  0.103 29.772 2.16 29.79 ;
     RECT  0.103 32.202 2.16 32.22 ;
     RECT  0.103 33.822 2.16 34.38 ;
     RECT  0.139 35.982 2.16 36.54 ;
     RECT  0.139 38.142 2.16 38.7 ;
     RECT  0.103 40.302 2.16 40.86 ;
     RECT  0.139 42.462 2.16 43.02 ;
     RECT  0.139 44.622 2.16 45.18 ;
     RECT  0.103 46.782 2.16 47.07 ;
     RECT  0.103 49.212 2.16 49.23 ;
     RECT  0.103 51.246 2.16 51.264 ;
     RECT  0.103 58.662 2.16 58.68 ;
     RECT  0.103 60.822 2.16 60.84 ;
     RECT  0.103 62.982 2.16 63 ;
     RECT  0.103 65.142 2.16 65.16 ;
     RECT  0.103 67.032 2.16 67.32 ;
     RECT  0.103 69.192 2.16 69.48 ;
     RECT  0.139 71.352 2.16 71.64 ;
     RECT  0.103 73.512 2.16 73.8 ;
     RECT  0.103 75.672 2.16 75.69 ;
     RECT  0.103 77.832 2.16 78.084 ;
     RECT  0.103 80.262 2.16 80.28 ;
     RECT  0.139 82.422 2.16 82.98 ;
     RECT  0.103 84.582 2.16 85.14 ;
     RECT  0.103 87.282 2.16 87.3 ;
     RECT  0.103 89.442 2.16 89.73 ;
     RECT  0.103 91.602 2.16 91.89 ;
     RECT  0.103 93.762 2.16 94.05 ;
     RECT  0.103 95.922 2.16 96.21 ;
     RECT  0.139 98.082 2.16 98.37 ;
     RECT  0.103 100.242 2.16 100.53 ;
     RECT  0.139 102.402 2.16 102.42 ;
     RECT  0.103 104.562 2.16 104.58 ;
     RECT  2.16 2.151 84.24 105.849 ;
     RECT  84.24 52.956 84.371 53.244 ;
     RECT  84.24 17.316 84.407 18.954 ;
     RECT  84.24 23.796 84.407 32.724 ;
     RECT  84.24 42.696 84.407 48.654 ;
     RECT  84.24 49.446 84.407 50.85 ;
     RECT  84.24 62.676 84.407 64.314 ;
     RECT  84.24 75.096 84.407 78.354 ;
     RECT  84.24 83.466 84.407 84.024 ;
     RECT  84.24 84.816 84.407 85.104 ;
     RECT  84.24 85.896 84.407 90.234 ;
     RECT  84.24 2.772 84.911 2.79 ;
     RECT  84.407 49.446 84.911 50.814 ;
     RECT  84.407 84.816 84.911 84.87 ;
     RECT  84.407 42.696 84.947 47.844 ;
     RECT  84.24 69.966 84.947 70.524 ;
     RECT  84.24 71.856 84.947 72.954 ;
     RECT  84.24 80.226 84.947 80.784 ;
     RECT  84.407 85.896 84.947 87.534 ;
     RECT  84.24 93.726 84.947 97.83 ;
     RECT  84.24 104.796 85.487 105.12 ;
     RECT  84.407 17.316 85.523 18.684 ;
     RECT  84.24 19.746 85.523 22.464 ;
     RECT  84.407 23.796 85.523 26.244 ;
     RECT  84.407 27.036 85.523 32.724 ;
     RECT  84.24 33.516 85.523 36.504 ;
     RECT  84.24 37.296 85.523 37.314 ;
     RECT  84.24 38.106 85.523 41.904 ;
     RECT  84.947 42.696 85.523 47.574 ;
     RECT  84.911 49.986 85.523 50.814 ;
     RECT  84.371 53.226 85.523 53.244 ;
     RECT  84.24 54.306 85.523 55.134 ;
     RECT  84.24 55.926 85.523 57.834 ;
     RECT  84.24 58.626 85.523 61.884 ;
     RECT  84.407 62.676 85.523 62.964 ;
     RECT  84.407 64.026 85.523 64.044 ;
     RECT  84.24 66.456 85.523 66.474 ;
     RECT  84.24 67.266 85.523 68.274 ;
     RECT  84.24 69.156 85.523 69.174 ;
     RECT  84.947 69.966 85.523 70.254 ;
     RECT  84.947 71.856 85.523 71.874 ;
     RECT  84.947 72.666 85.523 72.684 ;
     RECT  84.24 73.746 85.523 73.764 ;
     RECT  84.407 75.096 85.523 75.114 ;
     RECT  84.407 75.906 85.523 78.354 ;
     RECT  84.24 79.416 85.523 79.434 ;
     RECT  84.947 80.766 85.523 80.784 ;
     RECT  84.24 81.576 85.523 82.674 ;
     RECT  84.407 83.466 85.523 83.754 ;
     RECT  84.911 84.816 85.523 84.834 ;
     RECT  84.947 86.436 85.523 87.264 ;
     RECT  84.407 88.596 85.523 90.234 ;
     RECT  84.24 91.566 85.523 92.934 ;
     RECT  84.947 93.726 85.523 96.444 ;
     RECT  84.947 97.236 85.523 97.83 ;
     RECT  84.24 98.856 85.523 100.494 ;
     RECT  84.24 101.286 85.523 104.004 ;
     RECT  85.487 105.066 85.523 105.12 ;
     RECT  85.523 20.556 85.559 20.574 ;
     RECT  85.523 24.876 85.559 24.894 ;
     RECT  85.523 36.216 85.559 36.234 ;
     RECT  85.523 62.946 85.559 62.964 ;
     RECT  85.523 105.102 85.595 105.12 ;
     RECT  84.24 7.326 86.315 7.344 ;
     RECT  84.24 9.216 86.315 9.234 ;
     RECT  85.523 18.396 86.315 18.414 ;
     RECT  85.523 27.576 86.315 27.594 ;
     RECT  85.523 29.736 86.315 29.754 ;
     RECT  85.523 31.896 86.315 31.914 ;
     RECT  85.523 33.516 86.315 33.534 ;
     RECT  85.523 34.326 86.315 34.344 ;
     RECT  85.523 38.106 86.315 38.664 ;
     RECT  85.523 42.696 86.315 42.714 ;
     RECT  85.523 44.856 86.315 45.144 ;
     RECT  85.523 50.796 86.315 50.814 ;
     RECT  84.24 51.606 86.315 51.624 ;
     RECT  85.523 58.626 86.315 58.644 ;
     RECT  85.523 59.976 86.315 60.264 ;
     RECT  85.523 67.266 86.315 67.284 ;
     RECT  85.523 78.336 86.315 78.354 ;
     RECT  85.523 86.976 86.315 87.264 ;
     RECT  85.523 89.676 86.315 89.694 ;
     RECT  85.523 91.566 86.315 91.854 ;
     RECT  85.523 93.726 86.315 94.014 ;
     RECT  85.523 95.886 86.315 95.904 ;
     RECT  85.523 97.812 86.315 97.83 ;
     RECT  85.523 100.476 86.315 100.494 ;
     RECT  85.523 102.132 86.315 102.15 ;
    LAYER M3 ;
     RECT  28.908 0.571 28.926 2.143 ;
     RECT  40.752 1.723 40.77 2.143 ;
     RECT  40.215 2.143 40.77 2.219 ;
     RECT  37.548 1.723 37.566 2.371 ;
     RECT  2.415 2.143 2.505 2.413 ;
     RECT  7.815 2.143 7.905 2.413 ;
     RECT  13.215 2.143 13.305 2.413 ;
     RECT  18.615 2.143 18.705 2.413 ;
     RECT  24.015 2.143 24.105 2.413 ;
     RECT  28.908 2.143 29.505 2.413 ;
     RECT  34.815 2.143 34.905 2.413 ;
     RECT  45.615 2.143 45.705 2.413 ;
     RECT  51.015 2.143 51.105 2.413 ;
     RECT  56.415 2.143 56.505 2.413 ;
     RECT  61.815 2.143 61.905 2.413 ;
     RECT  67.215 2.143 67.305 2.413 ;
     RECT  72.615 2.143 72.705 2.413 ;
     RECT  78.015 2.143 78.105 2.413 ;
     RECT  83.415 2.143 83.505 2.413 ;
     RECT  28.908 2.413 29.697 2.461 ;
     RECT  30.492 0.091 30.51 2.461 ;
     RECT  33.588 0.091 33.606 2.461 ;
     RECT  37.476 2.371 37.566 2.461 ;
     RECT  42.372 0.091 42.39 2.497 ;
     RECT  33.192 2.461 33.606 2.561 ;
     RECT  34.815 2.413 35.097 2.569 ;
     RECT  42.372 2.497 42.462 2.597 ;
     RECT  28.908 2.461 30.51 2.605 ;
     RECT  31.248 2.533 31.266 2.605 ;
     RECT  32.112 0.091 32.13 2.605 ;
     RECT  39.132 0.091 39.15 2.605 ;
     RECT  34.776 2.569 35.097 2.633 ;
     RECT  7.815 2.413 8.097 2.635 ;
     RECT  2.415 2.413 2.697 2.641 ;
     RECT  18.615 2.413 18.897 2.641 ;
     RECT  34.815 2.633 35.097 2.641 ;
     RECT  37.188 2.461 37.566 2.641 ;
     RECT  38.988 2.605 39.15 2.641 ;
     RECT  40.215 2.219 40.59 2.641 ;
     RECT  2.304 2.641 2.697 2.717 ;
     RECT  34.815 2.641 35.478 2.731 ;
     RECT  36.324 2.641 36.342 2.731 ;
     RECT  17.928 2.641 18.897 2.759 ;
     RECT  33.264 2.561 33.606 2.759 ;
     RECT  37.188 2.641 37.89 2.759 ;
     RECT  38.988 2.641 40.59 2.759 ;
     RECT  41.724 2.641 42.066 2.759 ;
     RECT  59.832 2.497 59.85 2.759 ;
     RECT  28.8 2.605 32.13 2.767 ;
     RECT  7.704 2.635 8.097 2.795 ;
     RECT  28.8 2.767 32.346 2.795 ;
     RECT  34.815 2.731 36.342 2.795 ;
     RECT  41.904 2.759 41.922 2.795 ;
     RECT  84.888 2.683 84.906 2.795 ;
     RECT  31.536 2.795 32.346 2.813 ;
     RECT  37.188 2.759 37.746 2.813 ;
     RECT  38.988 2.759 39.366 2.813 ;
     RECT  14.832 2.731 14.85 2.831 ;
     RECT  37.188 2.813 37.206 2.911 ;
     RECT  38.844 2.875 38.862 2.911 ;
     RECT  28.8 2.795 30.762 3.029 ;
     RECT  31.536 2.813 31.878 3.029 ;
     RECT  33.264 2.759 33.534 3.029 ;
     RECT  36 2.795 36.342 3.029 ;
     RECT  37.116 2.911 37.206 3.029 ;
     RECT  40.215 2.759 40.59 3.029 ;
     RECT  29.415 3.029 30.618 3.065 ;
     RECT  31.536 3.029 31.806 3.065 ;
     RECT  36 3.029 36.018 3.065 ;
     RECT  37.116 3.029 37.134 3.065 ;
     RECT  38.664 2.911 38.862 3.065 ;
     RECT  54.504 2.251 54.522 3.065 ;
     RECT  29.415 3.065 30.222 3.299 ;
     RECT  31.536 3.065 31.698 3.299 ;
     RECT  38.736 3.065 38.862 3.299 ;
     RECT  31.536 3.299 31.554 3.335 ;
     RECT  33.264 3.029 33.426 3.569 ;
     RECT  33.264 3.569 33.282 3.605 ;
     RECT  45.615 2.413 45.897 4.117 ;
     RECT  45.54 4.117 45.897 4.153 ;
     RECT  44.568 4.153 44.586 4.261 ;
     RECT  45.432 4.153 45.897 4.261 ;
     RECT  44.568 4.261 45.99 4.657 ;
     RECT  10.836 4.699 10.854 4.829 ;
     RECT  0.54 4.801 0.558 4.843 ;
     RECT  21.528 4.795 21.546 4.891 ;
     RECT  21.528 4.891 21.726 4.955 ;
     RECT  0.108 4.843 0.558 4.973 ;
     RECT  21.708 4.955 21.726 4.991 ;
     RECT  44.568 4.657 46.17 5.071 ;
     RECT  44.46 5.071 46.17 5.459 ;
     RECT  49.032 3.181 49.05 6.035 ;
     RECT  44.568 5.459 46.17 6.079 ;
     RECT  44.568 6.079 46.674 6.269 ;
     RECT  44.568 6.269 46.53 6.305 ;
     RECT  44.568 6.305 46.458 6.809 ;
     RECT  0.54 4.973 0.558 7.037 ;
     RECT  34.815 2.795 35.097 7.051 ;
     RECT  34.815 7.051 35.154 7.088 ;
     RECT  38.772 7.051 38.79 7.181 ;
     RECT  44.748 6.809 46.458 7.187 ;
     RECT  86.292 7.003 86.31 7.349 ;
     RECT  49.068 7.087 49.086 7.385 ;
     RECT  45 7.187 46.458 7.421 ;
     RECT  36.504 7.231 36.522 7.457 ;
     RECT  45.252 7.421 46.458 7.457 ;
     RECT  45.432 7.457 46.458 9.005 ;
     RECT  7.815 2.795 8.097 9.112 ;
     RECT  2.415 2.717 2.697 9.121 ;
     RECT  7.704 9.112 8.097 9.121 ;
     RECT  7.704 9.121 8.154 9.149 ;
     RECT  2.304 9.121 2.697 9.197 ;
     RECT  86.292 9.163 86.31 9.239 ;
     RECT  7.815 9.149 8.154 9.545 ;
     RECT  22.176 9.481 22.194 9.653 ;
     RECT  45.432 9.005 46.278 9.787 ;
     RECT  44.244 9.481 44.262 9.815 ;
     RECT  48.204 9.391 48.222 10.049 ;
     RECT  45.396 9.787 46.278 10.057 ;
     RECT  44.46 9.931 44.478 10.085 ;
     RECT  83.415 2.413 83.697 10.267 ;
     RECT  83.415 10.267 83.79 10.319 ;
     RECT  45.396 10.057 46.314 10.355 ;
     RECT  44.568 10.471 44.586 10.561 ;
     RECT  45.396 10.355 46.278 10.561 ;
     RECT  22.536 10.471 22.554 10.589 ;
     RECT  47.268 10.471 47.286 10.589 ;
     RECT  0.108 10.267 0.126 10.625 ;
     RECT  44.568 10.561 46.278 11.245 ;
     RECT  43.884 11.245 46.278 11.281 ;
     RECT  2.415 9.197 2.697 11.323 ;
     RECT  86.292 11.179 86.31 11.357 ;
     RECT  7.815 9.545 8.097 11.371 ;
     RECT  2.304 11.323 2.697 11.399 ;
     RECT  43.884 11.281 46.674 11.399 ;
     RECT  82.62 11.179 82.638 11.399 ;
     RECT  7.416 11.371 8.097 11.435 ;
     RECT  44.532 11.399 44.55 11.435 ;
     RECT  20.376 11.371 20.394 11.543 ;
     RECT  45.36 11.399 46.674 11.821 ;
     RECT  45.36 11.821 47.034 11.975 ;
     RECT  47.016 11.975 47.034 12.209 ;
     RECT  82.656 12.181 82.674 12.365 ;
     RECT  45.36 11.975 46.134 12.479 ;
     RECT  45.36 12.479 45.954 12.757 ;
     RECT  44.1 12.523 44.118 12.793 ;
     RECT  44.964 12.757 45.954 12.793 ;
     RECT  44.1 12.793 45.954 13.055 ;
     RECT  29.415 3.299 29.697 13.333 ;
     RECT  28.836 13.333 29.697 13.405 ;
     RECT  13.215 2.413 13.497 13.432 ;
     RECT  2.415 11.399 2.697 13.441 ;
     RECT  28.836 13.405 29.898 13.441 ;
     RECT  13.104 13.432 13.497 13.469 ;
     RECT  2.304 13.441 2.697 13.517 ;
     RECT  22.824 13.435 22.842 13.559 ;
     RECT  28.836 13.441 30.33 13.559 ;
     RECT  26.784 13.531 26.802 13.631 ;
     RECT  29.016 13.559 29.898 13.667 ;
     RECT  29.415 13.667 29.898 13.703 ;
     RECT  44.1 13.055 44.838 14.251 ;
     RECT  45.615 13.055 45.954 14.251 ;
     RECT  44.1 14.251 45.954 14.369 ;
     RECT  44.1 14.369 45.897 14.377 ;
     RECT  43.884 14.377 45.897 14.441 ;
     RECT  43.884 14.441 44.514 14.549 ;
     RECT  45.468 14.441 45.897 14.675 ;
     RECT  37.008 13.639 37.026 14.747 ;
     RECT  43.884 14.549 43.938 14.779 ;
     RECT  43.56 14.779 43.938 14.915 ;
     RECT  42.768 14.917 42.786 15.089 ;
     RECT  0.54 14.917 0.558 15.677 ;
     RECT  43.92 14.915 43.938 15.719 ;
     RECT  45.615 14.675 45.897 15.871 ;
     RECT  45.504 15.871 45.897 17.077 ;
     RECT  7.815 11.435 8.097 17.419 ;
     RECT  42.624 17.275 42.786 17.455 ;
     RECT  42.3 17.455 42.786 17.491 ;
     RECT  10.8 17.491 10.818 17.609 ;
     RECT  7.815 17.419 8.154 17.645 ;
     RECT  21.204 17.491 21.222 17.645 ;
     RECT  42.3 17.491 42.822 17.653 ;
     RECT  41.616 17.653 42.822 17.761 ;
     RECT  41.616 17.761 42.93 17.789 ;
     RECT  40.215 3.029 40.497 17.851 ;
     RECT  21.24 17.761 21.474 17.879 ;
     RECT  21.24 17.879 21.258 17.951 ;
     RECT  45.396 17.077 45.897 18.031 ;
     RECT  38.772 17.995 38.79 18.149 ;
     RECT  40.215 17.851 41.13 18.149 ;
     RECT  0.108 18.043 0.126 18.185 ;
     RECT  13.215 13.469 13.497 18.283 ;
     RECT  18.615 2.759 18.897 18.283 ;
     RECT  2.415 13.517 2.697 18.301 ;
     RECT  42.12 17.789 42.93 18.301 ;
     RECT  10.368 18.157 10.386 18.329 ;
     RECT  13.104 18.283 13.497 18.329 ;
     RECT  2.304 18.301 2.697 18.365 ;
     RECT  42.12 18.301 43.578 18.419 ;
     RECT  86.292 18.331 86.31 18.419 ;
     RECT  18.504 18.283 18.897 18.455 ;
     RECT  42.12 18.419 43.434 18.535 ;
     RECT  40.215 18.149 40.986 18.563 ;
     RECT  42.084 18.535 43.434 18.605 ;
     RECT  42.084 18.605 43.29 18.661 ;
     RECT  7.815 17.645 8.097 18.667 ;
     RECT  18.615 18.455 18.897 18.697 ;
     RECT  85.5 17.311 85.518 18.701 ;
     RECT  45.252 18.031 45.897 18.805 ;
     RECT  41.868 18.661 43.29 18.931 ;
     RECT  83.415 10.319 83.697 18.931 ;
     RECT  7.416 18.667 8.097 18.955 ;
     RECT  18.615 18.697 19.422 18.959 ;
     RECT  41.616 18.931 43.29 18.959 ;
     RECT  47.124 18.841 47.142 18.959 ;
     RECT  83.415 18.931 84.402 18.989 ;
     RECT  41.616 18.959 42.966 19.103 ;
     RECT  45.108 18.805 45.897 19.103 ;
     RECT  44.352 18.187 44.37 19.133 ;
     RECT  20.808 19.075 20.826 19.229 ;
     RECT  41.76 19.103 42.966 19.229 ;
     RECT  45.324 19.103 45.897 19.243 ;
     RECT  38.772 19.201 38.79 19.373 ;
     RECT  20.916 19.345 21.15 19.499 ;
     RECT  41.76 19.229 42.822 19.769 ;
     RECT  7.416 18.955 8.154 19.805 ;
     RECT  43.92 19.345 43.938 20.039 ;
     RECT  45.324 19.243 46.098 20.039 ;
     RECT  20.916 19.499 20.934 20.111 ;
     RECT  83.415 18.989 83.826 20.237 ;
     RECT  10.692 20.191 10.71 20.309 ;
     RECT  38.772 20.155 38.79 20.309 ;
     RECT  0.108 20.203 0.126 20.345 ;
     RECT  20.88 20.191 20.898 20.345 ;
     RECT  40.215 18.563 40.497 20.425 ;
     RECT  2.415 18.365 2.697 20.461 ;
     RECT  2.304 20.461 2.697 20.525 ;
     RECT  85.5 19.741 85.518 20.551 ;
     RECT  7.416 19.805 8.097 20.615 ;
     RECT  20.7 20.551 20.718 20.651 ;
     RECT  40.215 20.425 40.734 20.695 ;
     RECT  41.832 19.769 42.822 20.731 ;
     RECT  85.5 20.551 85.554 20.813 ;
     RECT  2.415 20.525 2.697 20.821 ;
     RECT  2.415 20.821 2.79 20.861 ;
     RECT  40.215 20.695 40.806 20.965 ;
     RECT  41.544 20.731 42.822 20.965 ;
     RECT  20.448 20.821 20.466 20.993 ;
     RECT  10.584 21.091 10.602 21.191 ;
     RECT  7.815 20.615 8.097 21.403 ;
     RECT  20.484 21.505 20.502 21.659 ;
     RECT  7.416 21.403 8.097 21.695 ;
     RECT  18.615 18.959 18.897 21.739 ;
     RECT  45.324 20.039 45.897 21.739 ;
     RECT  40.215 20.965 42.822 21.811 ;
     RECT  40.215 21.811 42.858 21.929 ;
     RECT  21.168 22.081 21.186 22.199 ;
     RECT  41.328 21.929 42.75 22.469 ;
     RECT  18.615 21.739 18.954 22.505 ;
     RECT  13.215 18.329 13.497 22.603 ;
     RECT  18.615 22.505 18.897 22.603 ;
     RECT  2.415 20.861 2.697 22.621 ;
     RECT  13.104 22.603 13.497 22.649 ;
     RECT  2.304 22.621 2.697 22.685 ;
     RECT  85.5 20.813 85.518 22.685 ;
     RECT  18.504 22.603 18.897 22.775 ;
     RECT  45.324 21.739 45.954 22.783 ;
     RECT  45.324 22.783 46.314 22.877 ;
     RECT  43.56 22.741 43.578 22.891 ;
     RECT  86.292 22.843 86.31 22.973 ;
     RECT  2.415 22.685 2.697 22.981 ;
     RECT  83.415 20.237 83.697 22.981 ;
     RECT  21.492 22.891 21.51 23.009 ;
     RECT  43.56 22.891 43.722 23.009 ;
     RECT  2.415 22.981 2.79 23.021 ;
     RECT  41.508 22.469 42.75 23.251 ;
     RECT  7.815 21.695 8.097 23.275 ;
     RECT  18.615 22.775 18.897 23.287 ;
     RECT  83.232 22.981 83.697 23.309 ;
     RECT  38.772 22.711 38.79 23.351 ;
     RECT  41.436 23.251 42.75 23.431 ;
     RECT  18.615 23.287 19.422 23.549 ;
     RECT  20.844 23.431 20.862 23.549 ;
     RECT  7.416 23.275 8.097 23.585 ;
     RECT  41.292 23.431 43.074 23.585 ;
     RECT  47.16 23.323 47.178 23.597 ;
     RECT  41.472 23.585 43.074 23.855 ;
     RECT  40.215 21.929 40.497 23.899 ;
     RECT  41.76 23.855 43.074 24.061 ;
     RECT  41.76 24.061 43.506 24.173 ;
     RECT  41.76 24.173 43.182 24.269 ;
     RECT  45.324 22.877 45.897 24.269 ;
     RECT  41.76 24.269 42.822 24.359 ;
     RECT  20.916 24.331 20.934 24.431 ;
     RECT  18.615 23.549 18.897 24.475 ;
     RECT  40.215 23.899 40.554 24.629 ;
     RECT  18.252 24.475 18.897 24.665 ;
     RECT  13.215 22.649 13.497 24.763 ;
     RECT  2.415 23.021 2.697 24.781 ;
     RECT  13.104 24.763 13.497 24.809 ;
     RECT  2.304 24.781 2.697 24.845 ;
     RECT  85.5 23.791 85.518 24.871 ;
     RECT  18.504 24.665 18.897 24.935 ;
     RECT  41.76 24.359 42.714 25.015 ;
     RECT  85.5 24.871 85.554 25.133 ;
     RECT  2.415 24.845 2.697 25.141 ;
     RECT  41.616 25.015 42.714 25.169 ;
     RECT  2.415 25.141 2.79 25.181 ;
     RECT  21.168 25.447 21.186 25.619 ;
     RECT  45.396 24.269 45.897 25.709 ;
     RECT  41.652 25.169 42.606 25.951 ;
     RECT  41.616 25.951 42.606 26.131 ;
     RECT  40.215 24.629 40.497 26.365 ;
     RECT  41.616 26.131 42.75 26.365 ;
     RECT  83.415 23.309 83.697 26.491 ;
     RECT  18.615 24.935 18.897 26.635 ;
     RECT  83.415 26.491 84.402 26.669 ;
     RECT  18.252 26.635 18.897 26.825 ;
     RECT  13.215 24.809 13.497 26.923 ;
     RECT  56.415 2.413 56.697 26.923 ;
     RECT  67.215 2.413 67.497 26.923 ;
     RECT  78.015 2.413 78.297 26.923 ;
     RECT  83.415 26.669 83.697 26.923 ;
     RECT  2.415 25.181 2.697 26.941 ;
     RECT  40.215 26.365 42.75 26.941 ;
     RECT  13.104 26.923 13.497 26.969 ;
     RECT  47.412 26.923 47.43 26.969 ;
     RECT  56.304 26.923 56.697 26.969 ;
     RECT  67.104 26.923 67.497 26.969 ;
     RECT  77.904 26.923 78.297 26.969 ;
     RECT  83.304 26.923 83.697 26.969 ;
     RECT  2.304 26.941 2.697 27.005 ;
     RECT  21.168 26.941 21.186 27.059 ;
     RECT  18.504 26.825 18.897 27.095 ;
     RECT  40.215 26.941 43.11 27.211 ;
     RECT  2.415 27.005 2.697 27.301 ;
     RECT  40.215 27.211 43.254 27.329 ;
     RECT  2.415 27.301 2.79 27.341 ;
     RECT  40.215 27.329 43.11 27.389 ;
     RECT  45.432 25.709 45.897 27.571 ;
     RECT  40.215 27.389 43.074 27.599 ;
     RECT  47.268 27.481 47.286 27.599 ;
     RECT  86.292 27.547 86.31 27.599 ;
     RECT  0.108 27.547 0.126 27.635 ;
     RECT  44.496 27.355 44.514 27.841 ;
     RECT  45.252 27.571 45.897 27.841 ;
     RECT  44.496 27.841 45.897 27.949 ;
     RECT  44.424 27.949 45.897 28.139 ;
     RECT  48.096 27.949 48.114 28.139 ;
     RECT  40.215 27.599 42.606 28.175 ;
     RECT  46.764 28.147 46.782 28.247 ;
     RECT  45.108 28.139 45.897 28.445 ;
     RECT  41.508 28.175 42.606 28.525 ;
     RECT  49.032 28.381 49.05 28.541 ;
     RECT  20.808 27.481 20.826 28.561 ;
     RECT  41.508 28.525 42.786 28.561 ;
     RECT  41.508 28.561 43.146 28.679 ;
     RECT  49.896 28.219 49.914 28.679 ;
     RECT  7.815 23.585 8.097 28.795 ;
     RECT  20.772 28.561 20.826 28.831 ;
     RECT  41.508 28.679 43.038 28.859 ;
     RECT  18.615 27.095 18.897 28.921 ;
     RECT  20.772 28.831 21.294 28.949 ;
     RECT  7.815 28.795 8.154 28.985 ;
     RECT  42.624 28.859 43.038 28.985 ;
     RECT  18.615 28.921 18.954 29.021 ;
     RECT  2.415 27.341 2.697 29.083 ;
     RECT  7.815 28.985 8.097 29.083 ;
     RECT  41.508 28.859 41.67 29.101 ;
     RECT  2.304 29.083 2.697 29.129 ;
     RECT  20.772 28.949 20.826 29.191 ;
     RECT  39.348 28.957 39.366 29.219 ;
     RECT  7.704 29.083 8.097 29.255 ;
     RECT  20.484 29.191 20.826 29.291 ;
     RECT  42.768 28.985 43.038 29.399 ;
     RECT  2.415 29.129 2.697 29.461 ;
     RECT  10.656 28.561 10.674 29.489 ;
     RECT  2.415 29.461 2.79 29.501 ;
     RECT  20.808 29.291 20.826 29.525 ;
     RECT  40.215 28.175 40.497 29.731 ;
     RECT  41.436 29.101 41.67 29.731 ;
     RECT  86.292 29.707 86.31 29.759 ;
     RECT  0.108 29.707 0.126 29.795 ;
     RECT  40.215 29.731 41.67 29.903 ;
     RECT  41.364 29.903 41.67 29.911 ;
     RECT  21.492 29.911 21.51 30.029 ;
     RECT  7.815 29.255 8.097 30.043 ;
     RECT  41.364 29.911 42.066 30.065 ;
     RECT  41.544 30.065 42.066 30.145 ;
     RECT  42.876 29.399 43.038 30.145 ;
     RECT  38.772 29.911 38.79 30.173 ;
     RECT  41.544 30.145 43.038 30.181 ;
     RECT  19.944 30.145 19.962 30.299 ;
     RECT  7.416 30.043 8.097 30.331 ;
     RECT  83.415 26.969 83.697 30.541 ;
     RECT  10.764 30.451 10.782 30.569 ;
     RECT  41.544 30.181 43.074 30.569 ;
     RECT  41.544 30.569 42.93 30.605 ;
     RECT  41.544 30.605 42.678 30.641 ;
     RECT  83.415 30.541 83.826 30.653 ;
     RECT  18.615 29.021 18.897 30.685 ;
     RECT  18.615 30.685 19.422 30.839 ;
     RECT  40.215 29.903 40.554 31.109 ;
     RECT  7.416 30.331 8.154 31.145 ;
     RECT  2.415 29.501 2.697 31.243 ;
     RECT  2.304 31.243 2.697 31.289 ;
     RECT  21.024 30.379 21.042 31.351 ;
     RECT  41.76 30.641 42.678 31.423 ;
     RECT  20.988 31.351 21.186 31.451 ;
     RECT  38.772 31.351 38.79 31.451 ;
     RECT  20.988 31.451 21.006 31.523 ;
     RECT  41.328 31.423 42.678 31.525 ;
     RECT  41.328 31.525 42.822 31.531 ;
     RECT  85.5 25.133 85.518 31.613 ;
     RECT  2.415 31.289 2.697 31.621 ;
     RECT  20.844 31.531 20.862 31.649 ;
     RECT  44.136 31.531 44.154 31.649 ;
     RECT  2.415 31.621 2.79 31.661 ;
     RECT  18.615 30.839 18.897 31.891 ;
     RECT  86.292 31.867 86.31 31.919 ;
     RECT  7.416 31.145 8.097 31.955 ;
     RECT  83.415 30.653 83.697 32.152 ;
     RECT  40.215 31.109 40.497 32.161 ;
     RECT  41.22 31.531 42.822 32.161 ;
     RECT  83.415 32.152 84.366 32.189 ;
     RECT  0.108 31.771 0.126 32.225 ;
     RECT  20.484 32.161 20.826 32.261 ;
     RECT  40.215 32.161 42.822 32.443 ;
     RECT  7.815 31.955 8.097 32.491 ;
     RECT  40.215 32.443 42.93 32.495 ;
     RECT  41.616 32.495 42.93 32.611 ;
     RECT  18.615 31.891 19.422 32.729 ;
     RECT  85.5 32.431 85.518 32.813 ;
     RECT  20.808 32.261 20.826 32.999 ;
     RECT  45.615 28.445 45.897 33.115 ;
     RECT  45.615 33.115 46.026 33.179 ;
     RECT  7.815 32.491 8.154 33.305 ;
     RECT  2.415 31.661 2.697 33.403 ;
     RECT  13.215 26.969 13.497 33.403 ;
     RECT  18.615 32.729 18.897 33.403 ;
     RECT  20.916 33.241 20.934 33.421 ;
     RECT  41.616 32.611 43.074 33.421 ;
     RECT  2.304 33.403 2.697 33.449 ;
     RECT  13.104 33.403 13.497 33.449 ;
     RECT  20.916 33.421 21.402 33.539 ;
     RECT  41.616 33.421 43.722 33.539 ;
     RECT  45.615 33.179 45.918 33.539 ;
     RECT  86.292 33.403 86.31 33.539 ;
     RECT  40.215 32.495 40.497 33.547 ;
     RECT  41.616 33.539 43.002 33.547 ;
     RECT  18.504 33.403 18.897 33.575 ;
     RECT  46.656 33.421 46.746 33.611 ;
     RECT  48.636 33.511 48.654 33.611 ;
     RECT  40.215 33.547 43.002 33.719 ;
     RECT  84.924 33.547 84.942 33.725 ;
     RECT  20.916 33.539 21.366 33.781 ;
     RECT  20.808 33.781 21.366 33.881 ;
     RECT  41.292 33.719 43.002 34.079 ;
     RECT  41.292 34.079 42.858 34.115 ;
     RECT  20.844 33.881 21.366 34.259 ;
     RECT  21.348 34.259 21.366 34.349 ;
     RECT  86.292 34.312 86.31 34.349 ;
     RECT  0.108 33.691 0.126 34.385 ;
     RECT  13.215 33.449 13.497 34.591 ;
     RECT  40.215 33.719 40.497 34.591 ;
     RECT  10.476 34.591 10.494 34.627 ;
     RECT  10.296 34.627 10.494 34.637 ;
     RECT  13.104 34.591 13.497 34.637 ;
     RECT  20.484 34.603 20.502 34.655 ;
     RECT  10.296 34.637 10.314 34.685 ;
     RECT  40.215 34.591 41.022 34.691 ;
     RECT  38.772 34.591 38.79 34.763 ;
     RECT  41.76 34.115 42.75 34.843 ;
     RECT  83.415 32.189 83.697 34.861 ;
     RECT  83.415 34.861 84.402 34.973 ;
     RECT  41.76 34.843 42.786 35.041 ;
     RECT  20.7 35.005 20.718 35.159 ;
     RECT  18.615 33.575 18.897 35.275 ;
     RECT  41.544 35.041 42.786 35.311 ;
     RECT  18.252 35.275 18.897 35.465 ;
     RECT  41.544 35.311 42.858 35.509 ;
     RECT  2.415 33.449 2.697 35.563 ;
     RECT  7.815 33.305 8.097 35.563 ;
     RECT  41.544 35.509 42.966 35.581 ;
     RECT  2.304 35.563 2.697 35.609 ;
     RECT  21.024 35.581 21.258 35.699 ;
     RECT  7.704 35.563 8.097 35.735 ;
     RECT  21.024 35.699 21.042 35.771 ;
     RECT  40.215 34.691 40.497 35.815 ;
     RECT  41.544 35.581 43.146 35.815 ;
     RECT  40.215 35.815 43.146 35.969 ;
     RECT  0.144 35.851 0.162 36.005 ;
     RECT  85.5 33.781 85.518 36.211 ;
     RECT  10.584 36.121 10.602 36.239 ;
     RECT  41.436 35.969 43.146 36.239 ;
     RECT  20.772 36.121 20.79 36.275 ;
     RECT  41.652 36.239 43.074 36.275 ;
     RECT  85.5 36.211 85.554 36.509 ;
     RECT  0.108 36.187 0.126 36.545 ;
     RECT  21.168 36.517 21.186 36.661 ;
     RECT  21.168 36.661 21.366 36.689 ;
     RECT  21.348 36.689 21.366 36.779 ;
     RECT  41.868 36.275 43.074 36.779 ;
     RECT  40.215 35.969 40.497 37.021 ;
     RECT  49.752 28.795 49.77 37.021 ;
     RECT  39.924 37.021 40.497 37.121 ;
     RECT  49.464 37.021 49.77 37.133 ;
     RECT  41.868 36.779 42.606 37.165 ;
     RECT  41.724 37.165 42.606 37.201 ;
     RECT  20.484 37.165 20.502 37.319 ;
     RECT  41.544 37.201 42.606 37.355 ;
     RECT  7.815 35.735 8.097 37.387 ;
     RECT  85.5 36.509 85.518 37.421 ;
     RECT  40.215 37.121 40.497 37.435 ;
     RECT  41.544 37.355 41.994 37.435 ;
     RECT  10.548 37.471 10.566 37.589 ;
     RECT  40.215 37.435 41.994 37.589 ;
     RECT  7.815 37.387 8.154 37.625 ;
     RECT  20.592 37.471 20.61 37.625 ;
     RECT  2.415 35.609 2.697 37.723 ;
     RECT  7.815 37.625 8.097 37.723 ;
     RECT  56.415 26.969 56.697 37.723 ;
     RECT  67.215 26.969 67.497 37.723 ;
     RECT  78.015 26.969 78.297 37.723 ;
     RECT  2.304 37.723 2.697 37.769 ;
     RECT  41.508 37.589 41.994 37.769 ;
     RECT  48.492 37.723 48.51 37.769 ;
     RECT  56.304 37.723 56.697 37.769 ;
     RECT  67.104 37.723 67.497 37.769 ;
     RECT  77.904 37.723 78.297 37.769 ;
     RECT  20.7 37.741 20.97 37.859 ;
     RECT  41.616 37.769 41.994 37.859 ;
     RECT  7.704 37.723 8.097 37.895 ;
     RECT  20.7 37.859 20.79 38.003 ;
     RECT  10.584 38.011 10.602 38.129 ;
     RECT  47.268 38.011 47.286 38.129 ;
     RECT  42.732 38.011 43.182 38.137 ;
     RECT  0.144 38.011 0.162 38.165 ;
     RECT  20.7 38.003 20.718 38.165 ;
     RECT  42.732 38.137 43.506 38.165 ;
     RECT  45.615 33.539 45.897 38.251 ;
     RECT  45.615 38.251 46.35 38.309 ;
     RECT  42.948 38.165 43.506 38.399 ;
     RECT  42.948 38.399 42.966 38.435 ;
     RECT  40.215 37.589 40.497 38.641 ;
     RECT  41.616 37.859 41.886 38.641 ;
     RECT  86.292 38.011 86.31 38.669 ;
     RECT  0.108 38.347 0.126 38.705 ;
     RECT  20.484 38.641 20.502 38.741 ;
     RECT  40.215 38.641 41.886 38.741 ;
     RECT  20.7 38.971 20.718 39.011 ;
     RECT  41.328 38.741 41.886 39.091 ;
     RECT  10.584 38.971 10.602 39.208 ;
     RECT  21.024 39.208 21.042 39.245 ;
     RECT  10.584 39.208 10.782 39.253 ;
     RECT  41.328 39.091 42.174 39.325 ;
     RECT  10.548 39.253 10.782 39.487 ;
     RECT  41.328 39.325 42.714 39.631 ;
     RECT  10.404 39.487 10.782 39.739 ;
     RECT  21.204 39.631 21.402 39.749 ;
     RECT  10.404 39.739 10.89 39.785 ;
     RECT  21.204 39.749 21.222 39.785 ;
     RECT  2.415 37.769 2.697 39.883 ;
     RECT  7.815 37.895 8.097 39.883 ;
     RECT  56.415 37.769 56.697 39.883 ;
     RECT  61.815 2.413 62.097 39.883 ;
     RECT  78.015 37.769 78.297 39.883 ;
     RECT  56.304 39.883 56.697 39.929 ;
     RECT  77.904 39.883 78.678 39.929 ;
     RECT  38.772 39.217 38.79 40.019 ;
     RECT  10.404 39.785 10.71 40.027 ;
     RECT  7.704 39.883 8.097 40.055 ;
     RECT  2.415 39.883 2.862 40.061 ;
     RECT  48.924 39.901 48.942 40.061 ;
     RECT  61.815 39.883 62.73 40.061 ;
     RECT  78.015 39.929 78.678 40.061 ;
     RECT  10.368 40.027 10.71 40.199 ;
     RECT  10.584 40.199 10.71 40.301 ;
     RECT  41.328 39.631 42.858 40.441 ;
     RECT  20.916 40.267 20.934 40.531 ;
     RECT  48.168 40.441 48.186 40.589 ;
     RECT  86.292 39.883 86.31 40.589 ;
     RECT  20.916 40.531 21.294 40.631 ;
     RECT  41.328 40.441 43.398 40.631 ;
     RECT  41.4 40.631 43.398 40.829 ;
     RECT  0.108 39.883 0.126 40.865 ;
     RECT  20.7 40.711 20.79 40.865 ;
     RECT  2.415 40.061 2.697 41.071 ;
     RECT  10.584 40.301 10.602 41.071 ;
     RECT  13.215 34.637 13.497 41.071 ;
     RECT  41.508 40.829 43.398 41.099 ;
     RECT  2.304 41.071 2.697 41.117 ;
     RECT  10.584 41.071 10.674 41.117 ;
     RECT  13.104 41.071 13.497 41.117 ;
     RECT  20.772 40.865 20.79 41.135 ;
     RECT  6.84 41.083 6.858 41.213 ;
     RECT  41.508 41.099 42.858 41.675 ;
     RECT  10.44 41.179 10.458 41.707 ;
     RECT  40.215 38.741 40.497 41.755 ;
     RECT  10.296 41.707 10.458 41.881 ;
     RECT  10.296 41.881 10.494 41.933 ;
     RECT  10.296 41.933 10.314 41.945 ;
     RECT  20.484 41.899 20.502 41.945 ;
     RECT  40.215 41.755 41.166 41.945 ;
     RECT  18.615 35.465 18.897 41.995 ;
     RECT  85.5 38.911 85.518 42.029 ;
     RECT  41.94 41.675 42.858 42.061 ;
     RECT  21.456 42.061 21.474 42.179 ;
     RECT  18.252 41.995 18.897 42.215 ;
     RECT  83.415 34.973 83.697 42.325 ;
     RECT  41.94 42.061 42.966 42.449 ;
     RECT  40.215 41.945 40.497 42.691 ;
     RECT  86.292 42.619 86.31 42.719 ;
     RECT  40.176 42.691 40.77 42.749 ;
     RECT  38.772 42.763 38.79 42.899 ;
     RECT  40.215 42.749 40.77 42.955 ;
     RECT  83.415 42.325 83.79 42.955 ;
     RECT  20.952 42.871 20.97 42.989 ;
     RECT  43.812 42.871 43.83 42.989 ;
     RECT  0.144 42.331 0.162 43.025 ;
     RECT  83.415 42.955 84.366 43.025 ;
     RECT  40.215 42.955 40.842 43.141 ;
     RECT  2.415 41.117 2.697 43.231 ;
     RECT  13.215 41.117 13.497 43.231 ;
     RECT  18.615 42.215 18.897 43.243 ;
     RECT  40.215 43.141 40.986 43.259 ;
     RECT  42.048 42.449 42.93 43.259 ;
     RECT  2.304 43.231 2.697 43.277 ;
     RECT  13.104 43.231 13.497 43.277 ;
     RECT  40.215 43.259 40.77 43.295 ;
     RECT  42.048 43.259 42.678 43.501 ;
     RECT  41.652 43.501 42.678 43.601 ;
     RECT  18.504 43.243 18.897 43.867 ;
     RECT  18.252 43.867 18.897 44.105 ;
     RECT  41.868 43.601 42.678 44.221 ;
     RECT  41.868 44.221 42.75 44.299 ;
     RECT  21.276 44.221 21.294 44.339 ;
     RECT  41.868 44.299 43.002 44.491 ;
     RECT  43.956 44.383 43.974 44.491 ;
     RECT  85.5 42.961 85.518 44.525 ;
     RECT  21.024 44.491 21.078 44.609 ;
     RECT  43.956 44.491 44.19 44.609 ;
     RECT  41.616 44.491 43.002 44.645 ;
     RECT  41.652 44.645 43.002 44.761 ;
     RECT  0.108 44.491 0.126 44.915 ;
     RECT  41.652 44.761 43.038 44.923 ;
     RECT  21.06 44.609 21.078 45.149 ;
     RECT  41.652 44.923 43.182 45.149 ;
     RECT  86.292 44.779 86.31 45.149 ;
     RECT  0.144 45.115 0.162 45.185 ;
     RECT  41.652 45.149 43.038 45.329 ;
     RECT  2.415 43.277 2.697 45.391 ;
     RECT  13.215 43.277 13.497 45.391 ;
     RECT  41.652 45.329 42.678 45.391 ;
     RECT  83.415 43.025 83.697 45.391 ;
     RECT  18.615 44.105 18.897 45.403 ;
     RECT  2.304 45.391 2.697 45.437 ;
     RECT  13.104 45.391 13.497 45.437 ;
     RECT  83.415 45.391 84.402 45.437 ;
     RECT  41.4 45.391 42.678 45.563 ;
     RECT  43.956 44.609 43.974 45.689 ;
     RECT  18.504 45.403 18.897 46.027 ;
     RECT  38.772 45.733 38.79 46.031 ;
     RECT  49.752 37.133 49.77 46.237 ;
     RECT  83.415 45.437 83.697 46.237 ;
     RECT  18.252 46.027 18.897 46.265 ;
     RECT  41.58 45.563 42.678 46.345 ;
     RECT  83.415 46.237 84.402 46.349 ;
     RECT  41.436 46.345 42.678 46.381 ;
     RECT  49.752 46.237 50.022 46.409 ;
     RECT  41.436 46.381 43.182 46.643 ;
     RECT  41.76 46.643 43.182 46.769 ;
     RECT  41.76 46.769 43.038 46.805 ;
     RECT  21.384 46.741 21.402 46.841 ;
     RECT  21.456 46.921 21.474 47.039 ;
     RECT  0.108 46.651 0.126 47.075 ;
     RECT  40.215 43.295 40.497 47.155 ;
     RECT  2.415 45.437 2.697 47.179 ;
     RECT  18.615 46.265 18.897 47.179 ;
     RECT  2.415 47.179 2.79 47.219 ;
     RECT  40.215 47.155 40.986 47.309 ;
     RECT  18.252 47.179 18.897 47.345 ;
     RECT  2.415 47.219 2.697 47.551 ;
     RECT  13.215 45.437 13.497 47.551 ;
     RECT  2.304 47.551 2.697 47.597 ;
     RECT  10.764 47.551 10.782 47.597 ;
     RECT  13.104 47.551 13.497 47.597 ;
     RECT  85.5 45.661 85.518 47.597 ;
     RECT  21.024 47.563 21.042 47.615 ;
     RECT  6.84 47.563 6.858 47.693 ;
     RECT  10.548 47.659 10.566 47.696 ;
     RECT  41.76 46.805 42.966 47.821 ;
     RECT  84.924 47.821 84.942 47.885 ;
     RECT  83.415 46.349 83.697 48.091 ;
     RECT  41.544 47.821 42.966 48.119 ;
     RECT  40.215 47.309 40.497 48.235 ;
     RECT  40.215 48.235 40.77 48.271 ;
     RECT  41.544 48.119 42.318 48.271 ;
     RECT  46.728 48.091 46.746 48.299 ;
     RECT  10.224 48.187 10.458 48.425 ;
     RECT  20.376 48.379 20.394 48.425 ;
     RECT  40.215 48.271 42.318 48.425 ;
     RECT  48.348 48.433 48.366 48.509 ;
     RECT  38.772 48.541 38.79 48.659 ;
     RECT  18.615 47.345 18.897 48.763 ;
     RECT  83.415 48.091 84.402 48.797 ;
     RECT  41.292 48.425 42.318 48.859 ;
     RECT  18.615 48.763 18.954 48.965 ;
     RECT  41.292 48.859 42.462 48.965 ;
     RECT  45.615 38.309 45.897 48.973 ;
     RECT  45.615 48.973 46.206 49.085 ;
     RECT  86.292 48.955 86.31 49.133 ;
     RECT  0.108 49.099 0.126 49.235 ;
     RECT  2.415 47.597 2.697 49.339 ;
     RECT  2.415 49.339 2.79 49.379 ;
     RECT  43.272 49.351 43.29 49.469 ;
     RECT  84.888 49.387 84.906 49.469 ;
     RECT  40.215 48.425 40.497 49.549 ;
     RECT  42.228 48.965 42.462 49.579 ;
     RECT  2.415 49.379 2.697 49.711 ;
     RECT  56.415 39.929 56.697 49.711 ;
     RECT  67.215 37.769 67.497 49.711 ;
     RECT  78.015 40.061 78.297 49.711 ;
     RECT  21.384 49.621 21.402 49.739 ;
     RECT  44.352 49.549 44.37 49.739 ;
     RECT  2.304 49.711 2.697 49.757 ;
     RECT  45.615 49.085 45.918 49.757 ;
     RECT  56.304 49.711 56.697 49.757 ;
     RECT  67.104 49.711 67.497 49.757 ;
     RECT  77.904 49.711 78.297 49.757 ;
     RECT  40.215 49.549 41.058 49.775 ;
     RECT  7.815 40.055 8.097 49.819 ;
     RECT  6.84 49.723 6.858 49.853 ;
     RECT  21.204 49.747 21.222 49.919 ;
     RECT  10.8 49.891 10.818 50.009 ;
     RECT  7.815 49.819 8.154 50.011 ;
     RECT  7.416 50.011 8.154 50.045 ;
     RECT  42.228 49.579 42.966 50.153 ;
     RECT  19.944 50.125 19.962 50.279 ;
     RECT  7.416 50.045 8.097 50.315 ;
     RECT  42.804 50.153 42.966 50.315 ;
     RECT  42.876 50.315 42.966 50.323 ;
     RECT  85.5 49.981 85.518 50.333 ;
     RECT  42.876 50.323 43.002 50.351 ;
     RECT  38.772 50.323 38.79 50.423 ;
     RECT  42.912 50.351 43.002 50.431 ;
     RECT  42.048 50.155 42.066 50.521 ;
     RECT  42.912 50.431 43.362 50.549 ;
     RECT  46.728 50.521 46.746 50.621 ;
     RECT  18.615 48.965 18.897 50.635 ;
     RECT  40.215 49.775 40.497 50.665 ;
     RECT  41.652 50.521 42.066 50.701 ;
     RECT  48.636 50.521 48.654 50.819 ;
     RECT  86.292 50.635 86.31 50.819 ;
     RECT  51.015 2.413 51.297 50.827 ;
     RECT  83.415 48.797 83.697 50.827 ;
     RECT  18.252 50.635 18.897 50.923 ;
     RECT  50.724 50.827 51.297 50.927 ;
     RECT  40.215 50.665 40.59 50.935 ;
     RECT  41.436 50.701 42.066 50.935 ;
     RECT  83.415 50.827 84.402 50.957 ;
     RECT  40.215 50.935 42.066 51.089 ;
     RECT  18.252 50.923 18.954 51.125 ;
     RECT  83.415 50.957 83.826 51.293 ;
     RECT  41.508 51.089 42.066 51.359 ;
     RECT  18.252 51.125 18.897 51.395 ;
     RECT  41.688 51.359 41.706 51.395 ;
     RECT  2.415 49.757 2.697 51.499 ;
     RECT  42.912 50.549 43.11 51.511 ;
     RECT  2.415 51.499 2.79 51.539 ;
     RECT  42.912 51.511 43.146 51.601 ;
     RECT  42.588 51.601 43.146 51.629 ;
     RECT  7.815 50.315 8.097 51.739 ;
     RECT  45.615 49.757 45.897 51.739 ;
     RECT  10.908 51.637 10.926 51.809 ;
     RECT  0.108 51.241 0.126 51.869 ;
     RECT  86.292 51.547 86.31 51.869 ;
     RECT  7.416 51.739 8.097 51.935 ;
     RECT  83.415 51.293 83.697 52.141 ;
     RECT  10.692 52.141 10.71 52.168 ;
     RECT  20.844 51.907 20.862 52.168 ;
     RECT  10.512 52.168 10.71 52.205 ;
     RECT  20.844 52.168 20.934 52.205 ;
     RECT  41.832 52.141 41.85 52.285 ;
     RECT  42.588 51.629 43.002 52.285 ;
     RECT  40.215 51.089 40.497 52.411 ;
     RECT  41.832 52.285 43.002 52.411 ;
     RECT  45.615 51.739 45.99 52.411 ;
     RECT  7.815 51.935 8.097 52.459 ;
     RECT  41.616 52.411 43.002 52.475 ;
     RECT  45.615 52.411 46.422 52.493 ;
     RECT  39.924 52.411 40.497 52.583 ;
     RECT  20.484 52.555 20.61 52.709 ;
     RECT  83.415 52.141 83.826 52.795 ;
     RECT  40.215 52.583 40.497 52.951 ;
     RECT  41.616 52.475 41.742 52.951 ;
     RECT  10.548 52.205 10.566 52.979 ;
     RECT  83.415 52.795 84.366 52.979 ;
     RECT  20.592 52.709 20.61 53.015 ;
     RECT  42.588 52.475 43.002 53.131 ;
     RECT  45.615 52.493 46.242 53.159 ;
     RECT  42.588 53.131 43.074 53.221 ;
     RECT  38.772 53.131 38.79 53.249 ;
     RECT  7.815 52.459 8.154 53.285 ;
     RECT  42.588 53.221 43.362 53.393 ;
     RECT  40.215 52.951 41.742 53.401 ;
     RECT  85.5 53.221 85.518 53.405 ;
     RECT  45.615 53.159 46.206 53.429 ;
     RECT  20.844 53.401 21.15 53.519 ;
     RECT  40.215 53.401 41.85 53.527 ;
     RECT  20.844 53.519 20.934 53.591 ;
     RECT  40.215 53.527 42.498 53.597 ;
     RECT  2.415 51.539 2.697 53.659 ;
     RECT  2.415 53.659 2.79 53.699 ;
     RECT  48.384 53.659 48.402 53.699 ;
     RECT  10.584 53.761 10.602 53.797 ;
     RECT  20.844 53.591 20.898 53.797 ;
     RECT  10.404 53.797 10.602 53.837 ;
     RECT  20.664 53.797 20.898 53.837 ;
     RECT  39.348 53.851 39.366 53.969 ;
     RECT  2.415 53.699 2.697 53.995 ;
     RECT  10.512 53.837 10.602 54.031 ;
     RECT  13.215 47.597 13.497 54.031 ;
     RECT  2.304 53.995 2.697 54.059 ;
     RECT  43.344 53.393 43.362 54.059 ;
     RECT  6.84 53.659 6.858 54.077 ;
     RECT  10.512 54.031 10.71 54.077 ;
     RECT  13.104 54.031 13.497 54.077 ;
     RECT  40.215 53.597 42.282 54.077 ;
     RECT  10.512 54.077 10.53 54.095 ;
     RECT  43.596 54.211 43.614 54.329 ;
     RECT  47.376 54.211 47.394 54.329 ;
     RECT  48.852 54.301 48.87 54.337 ;
     RECT  83.415 52.979 83.79 54.365 ;
     RECT  41.508 54.077 42.282 54.473 ;
     RECT  20.772 53.837 20.898 54.481 ;
     RECT  45.615 53.429 45.897 54.481 ;
     RECT  48.852 54.337 48.942 54.509 ;
     RECT  20.772 54.481 21.042 54.599 ;
     RECT  45.324 54.481 45.897 54.599 ;
     RECT  41.58 54.473 42.282 54.751 ;
     RECT  43.884 54.571 43.902 54.779 ;
     RECT  41.58 54.751 42.426 55.111 ;
     RECT  10.584 55.021 10.602 55.139 ;
     RECT  20.7 55.021 20.718 55.175 ;
     RECT  38.772 54.481 38.79 55.211 ;
     RECT  18.615 51.395 18.897 55.243 ;
     RECT  83.415 54.365 83.697 55.381 ;
     RECT  39.348 55.255 39.366 55.409 ;
     RECT  41.58 55.111 42.534 55.409 ;
     RECT  18.252 55.243 18.897 55.445 ;
     RECT  41.58 55.409 42.498 55.489 ;
     RECT  83.232 55.381 83.697 55.565 ;
     RECT  20.952 55.561 20.97 55.679 ;
     RECT  40.215 54.077 40.497 55.795 ;
     RECT  41.436 55.489 42.498 55.795 ;
     RECT  0.108 55.867 0.126 55.997 ;
     RECT  48.024 55.831 48.042 55.997 ;
     RECT  86.292 55.867 86.31 55.997 ;
     RECT  2.415 54.059 2.697 56.155 ;
     RECT  13.215 54.077 13.497 56.191 ;
     RECT  18.615 55.445 18.897 56.203 ;
     RECT  2.304 56.155 2.697 56.219 ;
     RECT  13.104 56.191 13.497 56.237 ;
     RECT  18.504 56.203 18.897 56.255 ;
     RECT  40.215 55.795 42.498 56.395 ;
     RECT  20.844 55.921 20.862 56.461 ;
     RECT  40.215 56.395 42.75 56.461 ;
     RECT  20.844 56.461 21.402 56.561 ;
     RECT  40.215 56.461 43.074 56.641 ;
     RECT  20.808 56.641 20.826 56.759 ;
     RECT  40.215 56.641 43.254 56.759 ;
     RECT  40.215 56.759 43.074 56.795 ;
     RECT  38.772 57.001 38.79 57.173 ;
     RECT  41.652 56.795 43.074 57.209 ;
     RECT  18.615 56.255 18.897 57.403 ;
     RECT  21.06 57.451 21.078 57.569 ;
     RECT  18.252 57.403 18.897 57.605 ;
     RECT  40.215 56.795 40.497 57.685 ;
     RECT  41.652 57.209 42.822 57.685 ;
     RECT  47.952 57.691 47.97 57.749 ;
     RECT  40.215 57.685 42.822 57.839 ;
     RECT  2.415 56.219 2.697 57.979 ;
     RECT  41.436 57.839 42.822 57.991 ;
     RECT  2.415 57.979 2.79 58.019 ;
     RECT  85.5 54.301 85.518 58.061 ;
     RECT  45.615 54.599 45.897 58.219 ;
     RECT  45.615 58.219 46.458 58.289 ;
     RECT  2.415 58.019 2.697 58.315 ;
     RECT  13.215 56.237 13.497 58.351 ;
     RECT  18.615 57.605 18.897 58.363 ;
     RECT  2.304 58.315 2.697 58.379 ;
     RECT  41.436 57.991 42.93 58.379 ;
     RECT  13.104 58.351 13.497 58.397 ;
     RECT  18.504 58.363 18.897 58.415 ;
     RECT  86.292 58.219 86.31 58.649 ;
     RECT  0.108 58.603 0.126 58.685 ;
     RECT  40.215 57.839 40.497 58.801 ;
     RECT  83.415 55.565 83.697 58.891 ;
     RECT  20.52 58.801 20.538 58.919 ;
     RECT  83.415 58.891 84.402 58.973 ;
     RECT  40.215 58.801 40.59 59.071 ;
     RECT  40.215 59.071 40.806 59.225 ;
     RECT  38.772 57.955 38.79 59.261 ;
     RECT  41.652 58.379 42.822 59.305 ;
     RECT  41.652 59.305 43.146 59.341 ;
     RECT  41.652 59.341 43.506 59.459 ;
     RECT  18.615 58.415 18.897 59.563 ;
     RECT  85.5 59.161 85.518 59.597 ;
     RECT  18.615 59.563 18.954 59.765 ;
     RECT  41.652 59.459 43.29 59.809 ;
     RECT  41.616 59.809 43.29 60.035 ;
     RECT  44.028 59.809 44.046 60.269 ;
     RECT  86.292 59.851 86.31 60.269 ;
     RECT  2.415 58.379 2.697 60.475 ;
     RECT  83.415 58.973 83.697 60.475 ;
     RECT  13.215 58.397 13.497 60.511 ;
     RECT  18.615 59.765 18.897 60.523 ;
     RECT  2.304 60.475 2.697 60.539 ;
     RECT  43.056 60.035 43.29 60.547 ;
     RECT  51.015 50.927 51.297 60.547 ;
     RECT  13.104 60.511 13.497 60.557 ;
     RECT  18.504 60.523 18.897 60.575 ;
     RECT  83.415 60.475 83.79 60.575 ;
     RECT  50.652 60.547 51.297 60.647 ;
     RECT  40.215 59.225 40.497 60.655 ;
     RECT  41.616 60.035 42.21 60.655 ;
     RECT  43.056 60.547 43.578 60.719 ;
     RECT  46.764 60.511 46.782 60.719 ;
     RECT  43.056 60.719 43.29 60.809 ;
     RECT  0.108 60.763 0.126 60.845 ;
     RECT  43.056 60.809 43.254 60.917 ;
     RECT  40.215 60.655 42.21 60.955 ;
     RECT  43.056 60.917 43.146 60.955 ;
     RECT  85.5 60.511 85.518 61.321 ;
     RECT  84.924 61.321 85.518 61.421 ;
     RECT  40.215 60.955 43.146 61.493 ;
     RECT  41.436 61.493 43.146 61.619 ;
     RECT  18.615 60.575 18.897 62.011 ;
     RECT  83.415 60.575 83.697 62.131 ;
     RECT  41.436 61.619 42.966 62.159 ;
     RECT  41.436 62.159 42.858 62.429 ;
     RECT  41.652 62.429 42.858 62.465 ;
     RECT  83.415 62.131 83.826 62.669 ;
     RECT  18.252 62.011 18.897 62.735 ;
     RECT  41.832 62.465 42.858 62.735 ;
     RECT  85.5 61.421 85.518 62.941 ;
     RECT  85.5 62.941 85.554 62.957 ;
     RECT  0.108 62.539 0.126 63.005 ;
     RECT  2.415 60.539 2.697 63.211 ;
     RECT  13.215 60.557 13.497 63.211 ;
     RECT  38.772 63.085 38.79 63.239 ;
     RECT  85.536 62.957 85.554 63.245 ;
     RECT  2.304 63.211 2.697 63.248 ;
     RECT  13.104 63.211 13.497 63.248 ;
     RECT  18.504 62.735 18.897 63.275 ;
     RECT  41.976 62.735 42.858 63.307 ;
     RECT  40.215 61.493 40.497 63.391 ;
     RECT  83.415 62.669 83.697 63.481 ;
     RECT  20.736 63.391 20.754 63.509 ;
     RECT  40.215 63.391 41.094 63.545 ;
     RECT  41.976 63.307 43.11 63.725 ;
     RECT  41.976 63.725 42.858 63.751 ;
     RECT  47.808 63.823 47.826 63.869 ;
     RECT  41.4 63.751 42.858 64.049 ;
     RECT  85.5 64.021 85.518 64.205 ;
     RECT  41.4 64.049 42.714 64.319 ;
     RECT  83.415 63.481 84.402 64.493 ;
     RECT  41.436 64.319 42.714 64.589 ;
     RECT  2.415 63.248 2.697 64.795 ;
     RECT  83.415 64.493 83.826 64.829 ;
     RECT  13.215 63.248 13.497 64.831 ;
     RECT  18.615 63.275 18.897 64.843 ;
     RECT  41.616 64.589 42.714 65.011 ;
     RECT  47.484 64.939 47.502 65.021 ;
     RECT  86.292 64.987 86.31 65.117 ;
     RECT  0.108 65.083 0.126 65.165 ;
     RECT  41.616 65.011 43.29 65.201 ;
     RECT  20.628 65.137 20.646 65.309 ;
     RECT  2.304 64.795 2.697 65.408 ;
     RECT  13.104 64.831 13.497 65.408 ;
     RECT  18.504 64.843 18.897 65.435 ;
     RECT  45.615 58.289 45.897 65.515 ;
     RECT  44.64 65.551 44.658 65.669 ;
     RECT  45.615 65.515 46.206 65.741 ;
     RECT  83.415 64.829 83.697 65.911 ;
     RECT  83.232 65.911 83.697 66.365 ;
     RECT  38.772 66.325 38.79 66.479 ;
     RECT  41.616 65.201 43.074 66.487 ;
     RECT  18.615 65.435 18.897 66.619 ;
     RECT  85.5 66.451 85.518 66.653 ;
     RECT  83.415 66.365 83.697 66.721 ;
     RECT  18.252 66.619 18.897 66.785 ;
     RECT  41.4 66.487 43.074 66.821 ;
     RECT  40.215 63.545 40.497 66.865 ;
     RECT  83.415 66.721 83.826 66.941 ;
     RECT  41.76 66.821 43.074 66.991 ;
     RECT  41.76 66.991 43.29 67.019 ;
     RECT  40.215 66.865 41.022 67.055 ;
     RECT  45.615 65.741 45.897 67.171 ;
     RECT  41.832 67.019 43.29 67.289 ;
     RECT  44.064 67.171 44.082 67.289 ;
     RECT  45.615 67.171 46.458 67.289 ;
     RECT  86.292 67.243 86.31 67.289 ;
     RECT  0.108 66.907 0.126 67.325 ;
     RECT  41.832 67.289 42.858 67.433 ;
     RECT  2.415 65.408 2.697 67.531 ;
     RECT  13.215 65.408 13.497 67.531 ;
     RECT  18.615 66.785 18.897 67.531 ;
     RECT  2.304 67.531 2.697 67.568 ;
     RECT  13.104 67.531 13.497 67.568 ;
     RECT  18.504 67.531 18.897 67.595 ;
     RECT  21.168 67.567 21.186 67.739 ;
     RECT  42.192 67.433 42.858 67.829 ;
     RECT  41.436 68.071 41.454 68.171 ;
     RECT  49.752 46.409 49.77 68.179 ;
     RECT  51.015 60.647 51.297 68.179 ;
     RECT  42.192 67.829 42.822 68.215 ;
     RECT  45.615 67.289 45.897 68.251 ;
     RECT  46.764 68.179 46.782 68.251 ;
     RECT  45.615 68.251 46.782 68.279 ;
     RECT  49.752 68.179 51.297 68.279 ;
     RECT  45.615 68.279 46.098 68.369 ;
     RECT  50.256 68.279 51.297 68.369 ;
     RECT  83.415 66.941 83.697 68.611 ;
     RECT  83.415 68.611 83.826 68.813 ;
     RECT  21.24 69.061 21.258 69.179 ;
     RECT  41.616 68.215 42.822 69.187 ;
     RECT  41.292 69.187 42.822 69.359 ;
     RECT  20.844 69.331 20.862 69.449 ;
     RECT  0.108 69.067 0.126 69.485 ;
     RECT  2.415 67.568 2.697 69.691 ;
     RECT  13.215 67.568 13.497 69.691 ;
     RECT  18.615 67.595 18.897 69.691 ;
     RECT  56.415 49.757 56.697 69.691 ;
     RECT  67.215 49.757 67.497 69.691 ;
     RECT  78.015 49.757 78.297 69.691 ;
     RECT  39.348 69.457 39.366 69.719 ;
     RECT  48.924 69.601 48.942 69.725 ;
     RECT  2.304 69.691 2.697 69.728 ;
     RECT  13.104 69.691 13.497 69.728 ;
     RECT  56.304 69.691 56.697 69.728 ;
     RECT  67.104 69.691 67.497 69.728 ;
     RECT  77.904 69.691 78.297 69.728 ;
     RECT  18.504 69.691 18.897 69.755 ;
     RECT  41.868 69.359 42.822 69.755 ;
     RECT  42.084 69.755 42.822 69.863 ;
     RECT  38.772 69.961 38.79 70.061 ;
     RECT  42.372 69.863 42.822 70.123 ;
     RECT  20.916 70.141 20.934 70.259 ;
     RECT  85.5 67.525 85.518 70.349 ;
     RECT  18.615 69.755 18.897 70.603 ;
     RECT  84.924 70.501 84.942 70.637 ;
     RECT  42.372 70.123 43.11 70.645 ;
     RECT  42.156 70.645 43.11 70.681 ;
     RECT  83.415 68.813 83.697 70.771 ;
     RECT  42.156 70.681 43.146 70.799 ;
     RECT  18.252 70.603 18.897 70.835 ;
     RECT  41.328 70.141 41.346 70.879 ;
     RECT  42.156 70.799 42.822 70.879 ;
     RECT  83.415 70.771 83.79 71.041 ;
     RECT  21.168 70.951 21.186 71.069 ;
     RECT  40.215 67.055 40.497 71.185 ;
     RECT  41.328 70.879 42.822 71.185 ;
     RECT  83.415 71.041 83.826 71.261 ;
     RECT  0.108 71.227 0.126 71.375 ;
     RECT  83.415 71.261 83.79 71.549 ;
     RECT  10.656 71.491 10.674 71.609 ;
     RECT  0.144 71.515 0.162 71.645 ;
     RECT  20.88 71.491 20.898 71.645 ;
     RECT  40.215 71.185 42.822 71.645 ;
     RECT  2.415 69.728 2.697 71.851 ;
     RECT  13.215 69.728 13.497 71.851 ;
     RECT  18.615 70.835 18.897 71.851 ;
     RECT  85.5 71.845 85.518 71.885 ;
     RECT  2.304 71.851 2.697 71.888 ;
     RECT  13.104 71.851 13.497 71.888 ;
     RECT  18.504 71.851 18.897 71.915 ;
     RECT  21.6 71.851 21.618 71.951 ;
     RECT  38.808 71.923 38.826 72.023 ;
     RECT  43.056 71.851 43.182 72.031 ;
     RECT  20.808 72.031 20.826 72.149 ;
     RECT  43.056 72.031 43.362 72.149 ;
     RECT  84.924 72.121 84.942 72.173 ;
     RECT  40.215 71.645 42.174 72.185 ;
     RECT  83.415 71.549 83.697 72.391 ;
     RECT  46.764 72.301 46.782 72.427 ;
     RECT  46.656 72.427 46.782 72.455 ;
     RECT  83.232 72.391 83.697 72.509 ;
     RECT  46.656 72.455 46.674 72.563 ;
     RECT  40.215 72.185 40.626 72.725 ;
     RECT  18.615 71.915 18.897 72.763 ;
     RECT  43.056 72.149 43.182 72.769 ;
     RECT  42.948 72.769 43.182 72.797 ;
     RECT  85.5 72.661 85.518 72.797 ;
     RECT  41.58 72.185 42.174 72.841 ;
     RECT  42.948 72.797 42.966 72.841 ;
     RECT  41.58 72.841 42.966 72.869 ;
     RECT  41.58 72.869 42.714 72.931 ;
     RECT  18.252 72.763 18.897 72.995 ;
     RECT  7.815 53.285 8.097 73.051 ;
     RECT  84.924 72.931 84.942 73.085 ;
     RECT  83.415 72.509 83.697 73.201 ;
     RECT  43.704 73.111 43.722 73.229 ;
     RECT  47.484 73.111 47.502 73.229 ;
     RECT  7.815 73.051 8.154 73.265 ;
     RECT  38.772 73.003 38.79 73.265 ;
     RECT  20.916 73.201 20.934 73.301 ;
     RECT  20.844 73.345 20.862 73.381 ;
     RECT  10.548 73.381 10.566 73.499 ;
     RECT  20.664 73.381 20.862 73.499 ;
     RECT  20.664 73.499 20.682 73.535 ;
     RECT  41.508 72.931 42.714 73.535 ;
     RECT  41.508 73.535 42.102 73.615 ;
     RECT  83.415 73.201 83.754 73.651 ;
     RECT  83.415 73.651 83.79 73.709 ;
     RECT  41.328 73.615 42.102 73.769 ;
     RECT  42.84 73.651 42.858 73.769 ;
     RECT  0.108 73.387 0.126 73.805 ;
     RECT  41.616 73.769 42.102 73.805 ;
     RECT  43.848 73.885 44.37 73.921 ;
     RECT  2.415 71.888 2.697 74.011 ;
     RECT  13.215 71.888 13.497 74.011 ;
     RECT  18.615 72.995 18.897 74.011 ;
     RECT  43.848 73.921 44.442 74.039 ;
     RECT  85.5 73.741 85.518 74.045 ;
     RECT  43.848 74.039 43.866 74.047 ;
     RECT  2.304 74.011 2.697 74.048 ;
     RECT  13.104 74.011 13.497 74.048 ;
     RECT  18.504 74.011 18.897 74.075 ;
     RECT  47.484 74.083 47.502 74.333 ;
     RECT  43.344 74.047 43.866 74.417 ;
     RECT  41.976 73.805 42.102 74.461 ;
     RECT  21.024 74.389 21.042 74.489 ;
     RECT  41.976 74.461 42.498 74.551 ;
     RECT  83.415 73.709 83.697 74.551 ;
     RECT  10.764 74.461 10.782 74.579 ;
     RECT  18.615 74.075 18.897 74.587 ;
     RECT  7.815 73.265 8.097 74.635 ;
     RECT  83.232 74.551 83.697 74.669 ;
     RECT  83.415 74.669 83.697 74.821 ;
     RECT  18.615 74.587 19.422 74.849 ;
     RECT  40.215 72.725 40.497 74.857 ;
     RECT  41.652 74.551 42.498 74.857 ;
     RECT  7.416 74.635 8.097 74.885 ;
     RECT  40.215 74.857 42.498 75.001 ;
     RECT  20.484 75.091 20.502 75.191 ;
     RECT  18.615 74.849 18.897 75.211 ;
     RECT  83.415 74.821 83.826 75.361 ;
     RECT  20.592 75.271 21.078 75.389 ;
     RECT  47.016 74.857 47.034 75.389 ;
     RECT  18.252 75.211 18.897 75.425 ;
     RECT  40.215 75.001 43.182 75.533 ;
     RECT  83.415 75.361 84.402 75.581 ;
     RECT  10.548 75.541 10.566 75.659 ;
     RECT  40.215 75.533 42.858 75.659 ;
     RECT  43.596 75.541 43.614 75.659 ;
     RECT  20.592 75.389 21.042 75.695 ;
     RECT  45.615 68.369 45.897 75.811 ;
     RECT  41.436 75.659 42.858 75.929 ;
     RECT  0.108 75.547 0.126 75.965 ;
     RECT  45.615 75.811 45.954 75.965 ;
     RECT  86.292 75.835 86.31 75.965 ;
     RECT  2.415 74.048 2.697 76.171 ;
     RECT  13.215 74.048 13.497 76.171 ;
     RECT  18.615 75.425 18.897 76.171 ;
     RECT  21.024 75.695 21.042 76.199 ;
     RECT  2.304 76.171 2.697 76.208 ;
     RECT  13.104 76.171 13.497 76.208 ;
     RECT  18.504 76.171 18.897 76.235 ;
     RECT  41.544 75.929 42.858 76.235 ;
     RECT  41.76 76.235 42.858 76.621 ;
     RECT  40.215 75.659 40.497 76.711 ;
     RECT  83.415 75.581 83.697 76.711 ;
     RECT  83.415 76.711 83.826 76.781 ;
     RECT  40.215 76.711 40.914 76.811 ;
     RECT  21.384 76.441 21.402 77.279 ;
     RECT  18.615 76.235 18.897 77.371 ;
     RECT  41.76 76.621 43.11 77.395 ;
     RECT  41.616 77.395 43.11 77.549 ;
     RECT  41.76 77.549 43.11 77.855 ;
     RECT  85.5 75.091 85.518 78.029 ;
     RECT  0.108 77.707 0.126 78.089 ;
     RECT  41.796 77.855 43.11 78.089 ;
     RECT  18.252 77.371 18.897 78.125 ;
     RECT  13.215 76.208 13.497 78.232 ;
     RECT  2.415 76.208 2.697 78.241 ;
     RECT  13.104 78.232 13.497 78.269 ;
     RECT  2.304 78.241 2.697 78.317 ;
     RECT  41.796 78.089 42.822 78.359 ;
     RECT  86.292 78.283 86.31 78.359 ;
     RECT  18.504 78.125 18.897 78.395 ;
     RECT  38.772 78.331 38.79 78.503 ;
     RECT  41.796 78.359 42.174 78.601 ;
     RECT  83.415 76.781 83.697 78.601 ;
     RECT  41.616 78.601 42.174 78.781 ;
     RECT  20.916 78.781 20.934 78.899 ;
     RECT  41.328 78.781 42.174 78.935 ;
     RECT  83.232 78.601 83.697 78.941 ;
     RECT  41.508 78.935 42.174 79.141 ;
     RECT  47.916 79.213 47.934 79.277 ;
     RECT  41.508 79.141 42.246 79.321 ;
     RECT  41.508 79.321 42.39 79.447 ;
     RECT  18.615 78.395 18.897 79.531 ;
     RECT  85.5 79.411 85.518 79.565 ;
     RECT  41.508 79.447 42.606 79.591 ;
     RECT  21.24 79.591 21.258 79.709 ;
     RECT  18.615 79.531 18.954 79.745 ;
     RECT  45.615 75.965 45.897 79.819 ;
     RECT  41.508 79.591 42.642 79.825 ;
     RECT  41.4 79.825 42.642 79.861 ;
     RECT  45.615 79.819 46.026 79.889 ;
     RECT  83.415 78.941 83.697 79.951 ;
     RECT  41.4 79.861 42.822 79.979 ;
     RECT  83.415 79.951 83.79 80.189 ;
     RECT  21.132 80.131 21.15 80.249 ;
     RECT  0.108 80.155 0.126 80.285 ;
     RECT  13.215 78.269 13.497 80.392 ;
     RECT  18.615 79.745 18.897 80.395 ;
     RECT  2.415 78.317 2.697 80.401 ;
     RECT  13.104 80.392 13.497 80.429 ;
     RECT  2.304 80.401 2.697 80.477 ;
     RECT  84.924 80.221 84.942 80.477 ;
     RECT  39.348 80.257 39.366 80.519 ;
     RECT  18.504 80.395 18.897 80.555 ;
     RECT  85.5 80.761 85.518 80.813 ;
     RECT  40.215 76.811 40.497 80.941 ;
     RECT  41.724 79.979 42.75 80.941 ;
     RECT  83.415 80.189 83.697 81.031 ;
     RECT  83.232 81.031 83.697 81.101 ;
     RECT  83.415 81.101 83.697 81.301 ;
     RECT  20.808 80.941 20.826 81.337 ;
     RECT  83.415 81.301 83.826 81.389 ;
     RECT  20.628 81.337 20.826 81.509 ;
     RECT  40.215 80.941 42.75 81.635 ;
     RECT  43.524 80.671 43.542 81.671 ;
     RECT  18.615 80.555 18.897 81.691 ;
     RECT  41.652 81.635 42.75 81.751 ;
     RECT  85.5 81.571 85.518 81.841 ;
     RECT  21.168 81.751 21.186 81.869 ;
     RECT  18.615 81.691 18.954 81.905 ;
     RECT  18.615 81.905 18.897 81.979 ;
     RECT  84.924 81.841 85.518 82.013 ;
     RECT  39.348 81.985 39.366 82.139 ;
     RECT  83.415 81.389 83.697 82.381 ;
     RECT  21.132 82.291 21.15 82.409 ;
     RECT  0.108 82.315 0.126 82.445 ;
     RECT  13.215 80.429 13.497 82.552 ;
     RECT  2.415 80.477 2.697 82.561 ;
     RECT  41.652 81.751 42.786 82.561 ;
     RECT  13.104 82.552 13.497 82.589 ;
     RECT  2.304 82.561 2.697 82.637 ;
     RECT  83.415 82.381 84.402 82.637 ;
     RECT  18.252 81.979 18.897 82.715 ;
     RECT  41.436 82.561 42.786 82.831 ;
     RECT  20.844 82.831 20.862 82.949 ;
     RECT  0.144 82.891 0.162 82.985 ;
     RECT  41.292 82.831 42.786 82.985 ;
     RECT  41.724 82.985 42.786 83.101 ;
     RECT  45.615 79.889 45.897 83.191 ;
     RECT  45.615 83.191 46.026 83.261 ;
     RECT  41.724 83.101 42.858 83.363 ;
     RECT  21.384 83.371 21.402 83.489 ;
     RECT  41.904 83.363 42.858 83.489 ;
     RECT  40.215 81.635 40.497 83.767 ;
     RECT  7.815 74.885 8.097 83.851 ;
     RECT  85.5 82.013 85.518 83.885 ;
     RECT  40.215 83.767 41.058 83.939 ;
     RECT  21.024 83.911 21.042 84.001 ;
     RECT  83.415 82.637 83.697 84.001 ;
     RECT  7.815 83.851 8.154 84.065 ;
     RECT  41.904 83.489 42.714 84.145 ;
     RECT  83.415 84.001 84.402 84.173 ;
     RECT  20.808 84.001 21.042 84.181 ;
     RECT  10.548 84.181 10.566 84.299 ;
     RECT  20.664 84.181 21.042 84.335 ;
     RECT  41.22 84.145 42.714 84.335 ;
     RECT  41.508 84.335 42.714 84.343 ;
     RECT  21.276 84.451 21.294 84.569 ;
     RECT  40.215 83.939 40.497 84.685 ;
     RECT  7.815 84.065 8.097 84.715 ;
     RECT  2.415 82.637 2.697 84.721 ;
     RECT  2.304 84.721 2.697 84.797 ;
     RECT  84.888 84.763 84.906 84.811 ;
     RECT  40.215 84.685 40.77 84.839 ;
     RECT  43.92 84.721 43.938 84.839 ;
     RECT  50.256 68.369 50.274 84.847 ;
     RECT  7.704 84.715 8.097 84.875 ;
     RECT  41.508 84.343 42.858 84.875 ;
     RECT  84.888 84.811 85.518 84.875 ;
     RECT  20.376 84.811 20.394 84.911 ;
     RECT  49.896 84.847 50.274 85.019 ;
     RECT  83.415 84.173 83.79 85.081 ;
     RECT  85.5 84.875 85.518 85.085 ;
     RECT  39.348 84.883 39.366 85.109 ;
     RECT  0.108 84.475 0.126 85.145 ;
     RECT  41.652 84.875 42.858 85.379 ;
     RECT  83.415 85.081 84.402 85.421 ;
     RECT  45.615 83.261 45.897 85.531 ;
     RECT  43.884 85.531 43.902 85.649 ;
     RECT  45.615 85.531 46.026 85.709 ;
     RECT  41.652 85.379 42.678 85.927 ;
     RECT  7.815 84.875 8.097 86.011 ;
     RECT  84.924 85.891 84.942 86.045 ;
     RECT  20.952 86.071 20.97 86.161 ;
     RECT  40.215 84.839 40.497 86.161 ;
     RECT  41.508 85.927 42.678 86.161 ;
     RECT  83.415 85.421 83.697 86.161 ;
     RECT  83.232 86.161 83.697 86.333 ;
     RECT  20.772 86.161 20.97 86.431 ;
     RECT  40.215 86.161 42.678 86.459 ;
     RECT  20.448 86.431 20.97 86.603 ;
     RECT  85.5 86.431 85.518 86.621 ;
     RECT  39.348 86.575 39.366 86.729 ;
     RECT  7.416 86.011 8.097 86.765 ;
     RECT  10.476 86.701 10.494 86.801 ;
     RECT  13.215 82.589 13.497 86.872 ;
     RECT  18.615 82.715 18.897 86.875 ;
     RECT  2.415 84.797 2.697 86.881 ;
     RECT  13.104 86.872 13.497 86.909 ;
     RECT  2.304 86.881 2.697 86.957 ;
     RECT  41.544 86.459 42.678 87.007 ;
     RECT  18.504 86.875 18.897 87.035 ;
     RECT  41.544 87.007 42.786 87.043 ;
     RECT  41.544 87.043 42.858 87.151 ;
     RECT  86.292 86.923 86.31 87.269 ;
     RECT  0.108 87.211 0.126 87.305 ;
     RECT  21.06 86.881 21.078 87.421 ;
     RECT  41.544 87.151 42.93 87.421 ;
     RECT  7.815 86.765 8.097 87.547 ;
     RECT  41.22 87.421 43.11 87.575 ;
     RECT  84.924 87.511 84.942 87.581 ;
     RECT  18.615 87.035 18.897 87.655 ;
     RECT  41.76 87.575 43.11 87.691 ;
     RECT  18.615 87.655 19.422 87.809 ;
     RECT  41.76 87.691 43.362 87.809 ;
     RECT  41.76 87.809 43.254 87.845 ;
     RECT  46.836 87.655 46.854 87.869 ;
     RECT  41.868 87.845 43.254 87.917 ;
     RECT  20.844 87.421 21.078 87.925 ;
     RECT  83.415 86.333 83.697 88.051 ;
     RECT  20.664 87.925 21.078 88.079 ;
     RECT  83.415 88.051 84.402 88.157 ;
     RECT  20.772 88.079 21.078 88.259 ;
     RECT  20.772 88.259 20.898 88.349 ;
     RECT  7.416 87.547 8.097 88.385 ;
     RECT  49.032 88.459 49.05 88.529 ;
     RECT  38.772 88.465 38.79 88.619 ;
     RECT  41.94 87.917 43.254 88.735 ;
     RECT  7.704 88.385 8.097 88.747 ;
     RECT  10.656 88.771 10.674 88.889 ;
     RECT  7.704 88.747 8.154 88.925 ;
     RECT  2.415 86.957 2.697 89.041 ;
     RECT  20.772 88.349 20.79 89.041 ;
     RECT  40.215 86.459 40.497 89.041 ;
     RECT  83.415 88.157 83.697 89.083 ;
     RECT  2.304 89.041 2.697 89.117 ;
     RECT  41.508 88.735 43.254 89.131 ;
     RECT  20.52 89.041 20.79 89.159 ;
     RECT  41.436 89.131 43.254 89.167 ;
     RECT  7.704 88.925 8.097 89.195 ;
     RECT  83.415 89.083 84.366 89.195 ;
     RECT  40.215 89.041 40.662 89.311 ;
     RECT  41.436 89.167 43.434 89.311 ;
     RECT  40.215 89.311 43.434 89.339 ;
     RECT  49.356 89.167 49.374 89.339 ;
     RECT  85.5 88.591 85.518 89.405 ;
     RECT  40.215 89.339 43.182 89.429 ;
     RECT  40.215 89.429 43.038 89.501 ;
     RECT  86.292 89.659 86.31 89.699 ;
     RECT  0.108 89.371 0.126 89.735 ;
     RECT  83.415 89.195 83.697 89.941 ;
     RECT  20.808 89.311 20.826 89.969 ;
     RECT  40.215 89.501 42.714 90.005 ;
     RECT  83.415 89.941 83.826 90.029 ;
     RECT  41.328 90.005 42.714 90.275 ;
     RECT  85.5 90.211 85.518 90.317 ;
     RECT  49.356 90.619 49.374 90.689 ;
     RECT  20.916 90.661 20.934 90.779 ;
     RECT  83.415 90.029 83.697 90.787 ;
     RECT  41.328 90.275 42.678 90.895 ;
     RECT  18.615 87.809 18.897 90.907 ;
     RECT  83.232 90.787 83.697 90.941 ;
     RECT  48.924 90.787 48.942 90.959 ;
     RECT  41.22 90.895 42.678 91.049 ;
     RECT  18.615 90.907 18.954 91.085 ;
     RECT  2.415 89.117 2.697 91.192 ;
     RECT  13.215 86.909 13.497 91.192 ;
     RECT  45.615 85.709 45.897 91.192 ;
     RECT  56.415 69.728 56.697 91.192 ;
     RECT  67.215 69.728 67.497 91.192 ;
     RECT  78.015 69.728 78.297 91.192 ;
     RECT  18.615 91.085 18.897 91.195 ;
     RECT  2.304 91.192 2.697 91.229 ;
     RECT  13.104 91.192 13.497 91.229 ;
     RECT  45.615 91.192 46.026 91.229 ;
     RECT  56.304 91.192 56.697 91.229 ;
     RECT  67.104 91.192 67.497 91.229 ;
     RECT  77.904 91.192 78.297 91.229 ;
     RECT  18.504 91.195 18.897 91.355 ;
     RECT  41.544 91.049 42.678 91.463 ;
     RECT  21.348 91.471 21.366 91.589 ;
     RECT  38.772 91.471 38.79 91.625 ;
     RECT  41.832 91.463 42.678 91.741 ;
     RECT  86.292 91.531 86.31 91.859 ;
     RECT  0.108 91.531 0.126 91.895 ;
     RECT  21.06 91.831 21.078 91.931 ;
     RECT  41.832 91.741 42.822 92.011 ;
     RECT  41.832 92.011 43.074 92.129 ;
     RECT  20.844 92.371 20.862 92.471 ;
     RECT  41.832 92.129 42.822 92.551 ;
     RECT  83.415 90.941 83.697 92.641 ;
     RECT  7.815 89.195 8.097 92.731 ;
     RECT  83.415 92.641 83.826 92.765 ;
     RECT  40.215 90.005 40.497 92.785 ;
     RECT  41.724 92.551 42.822 92.785 ;
     RECT  7.416 92.731 8.097 92.975 ;
     RECT  40.215 92.785 42.822 93.055 ;
     RECT  18.615 91.355 18.897 93.067 ;
     RECT  40.215 93.055 42.93 93.091 ;
     RECT  85.5 92.101 85.518 93.101 ;
     RECT  21.024 93.091 21.042 93.209 ;
     RECT  40.215 93.091 43.722 93.209 ;
     RECT  47.376 93.091 47.394 93.209 ;
     RECT  18.615 93.067 18.954 93.245 ;
     RECT  40.215 93.209 43.074 93.245 ;
     RECT  2.415 91.229 2.697 93.352 ;
     RECT  13.215 91.229 13.497 93.352 ;
     RECT  41.796 93.245 43.074 93.353 ;
     RECT  18.615 93.245 18.897 93.355 ;
     RECT  2.304 93.352 2.697 93.389 ;
     RECT  13.104 93.352 13.497 93.389 ;
     RECT  83.415 92.765 83.754 93.389 ;
     RECT  41.796 93.353 42.858 93.479 ;
     RECT  18.252 93.355 18.897 93.515 ;
     RECT  40.215 93.245 41.058 93.515 ;
     RECT  21.168 93.757 21.186 93.991 ;
     RECT  86.292 93.691 86.31 94.019 ;
     RECT  20.916 93.991 21.186 94.091 ;
     RECT  41.832 93.479 42.858 94.163 ;
     RECT  42.084 94.163 42.858 94.325 ;
     RECT  18.615 93.515 18.897 94.567 ;
     RECT  67.215 91.229 67.497 94.597 ;
     RECT  2.415 93.389 2.697 94.603 ;
     RECT  50.256 85.019 50.274 94.603 ;
     RECT  51.015 68.369 51.297 94.603 ;
     RECT  61.815 40.061 62.097 94.603 ;
     RECT  66.78 94.597 67.497 94.603 ;
     RECT  78.015 91.229 78.297 94.603 ;
     RECT  85.5 94.261 85.518 94.603 ;
     RECT  0.108 93.691 0.126 94.733 ;
     RECT  2.415 94.603 2.862 94.733 ;
     RECT  47.844 94.531 47.862 94.733 ;
     RECT  61.815 94.603 62.73 94.733 ;
     RECT  78.015 94.603 78.678 94.733 ;
     RECT  82.62 94.603 82.638 94.733 ;
     RECT  21.168 94.091 21.186 94.739 ;
     RECT  18.615 94.567 19.422 94.829 ;
     RECT  6.84 94.603 6.858 94.877 ;
     RECT  50.256 94.603 51.297 94.877 ;
     RECT  58.68 94.603 58.698 94.877 ;
     RECT  66.708 94.603 67.497 94.877 ;
     RECT  74.664 94.603 74.682 94.877 ;
     RECT  85.5 94.603 86.238 94.877 ;
     RECT  85.5 94.877 85.518 95.071 ;
     RECT  42.192 94.325 42.858 95.083 ;
     RECT  38.772 94.261 38.79 95.107 ;
     RECT  21.132 95.071 21.15 95.171 ;
     RECT  38.772 95.107 39.366 95.171 ;
     RECT  7.815 92.975 8.097 95.227 ;
     RECT  40.215 93.515 40.497 95.251 ;
     RECT  84.924 95.071 85.518 95.261 ;
     RECT  39.348 95.171 39.366 95.369 ;
     RECT  7.815 95.227 8.154 95.405 ;
     RECT  40.215 95.251 41.058 95.405 ;
     RECT  42.048 95.083 42.858 95.405 ;
     RECT  42.624 95.405 42.858 95.485 ;
     RECT  2.415 94.733 2.697 95.512 ;
     RECT  13.215 93.389 13.497 95.512 ;
     RECT  20.448 95.341 21.042 95.513 ;
     RECT  18.615 94.829 18.897 95.515 ;
     RECT  42.624 95.485 43.038 95.521 ;
     RECT  2.304 95.512 2.697 95.549 ;
     RECT  13.104 95.512 13.497 95.549 ;
     RECT  85.5 95.261 85.518 95.549 ;
     RECT  18.504 95.515 18.897 95.675 ;
     RECT  86.292 95.851 86.31 95.909 ;
     RECT  20.592 95.513 21.042 95.917 ;
     RECT  42.624 95.521 43.182 96.061 ;
     RECT  20.592 95.917 21.186 96.089 ;
     RECT  41.616 95.521 41.814 96.139 ;
     RECT  42.624 96.061 43.254 96.139 ;
     RECT  83.415 93.389 83.697 96.139 ;
     RECT  10.548 96.061 10.566 96.179 ;
     RECT  0.108 95.851 0.126 96.215 ;
     RECT  20.592 96.089 21.078 96.215 ;
     RECT  41.616 96.139 43.254 96.331 ;
     RECT  85.5 96.421 85.518 96.461 ;
     RECT  41.616 96.331 43.398 96.485 ;
     RECT  41.616 96.485 43.146 96.601 ;
     RECT  41.472 96.601 43.146 96.691 ;
     RECT  83.415 96.139 83.79 96.691 ;
     RECT  41.292 96.691 43.146 96.719 ;
     RECT  41.292 96.719 42.39 96.755 ;
     RECT  43.128 96.719 43.146 96.755 ;
     RECT  7.815 95.405 8.097 96.763 ;
     RECT  83.415 96.691 84.402 96.797 ;
     RECT  18.615 95.675 18.897 96.835 ;
     RECT  18.615 96.835 19.422 96.989 ;
     RECT  84.924 96.961 84.942 97.085 ;
     RECT  21.06 96.215 21.078 97.231 ;
     RECT  20.88 97.231 21.078 97.259 ;
     RECT  20.88 97.259 20.898 97.403 ;
     RECT  41.292 96.755 42.318 97.529 ;
     RECT  7.416 96.763 8.097 97.565 ;
     RECT  41.292 97.529 41.886 97.565 ;
     RECT  10.584 97.501 10.602 97.601 ;
     RECT  2.415 95.549 2.697 97.672 ;
     RECT  2.304 97.672 2.697 97.709 ;
     RECT  40.215 95.405 40.497 97.771 ;
     RECT  41.292 97.565 41.778 97.771 ;
     RECT  7.704 97.565 8.097 97.835 ;
     RECT  86.292 97.675 86.31 97.835 ;
     RECT  44.316 97.879 44.334 97.979 ;
     RECT  48.924 97.807 48.942 97.979 ;
     RECT  85.5 97.231 85.518 97.997 ;
     RECT  83.415 96.797 83.697 98.041 ;
     RECT  42.696 97.843 42.786 98.069 ;
     RECT  0.144 97.963 0.162 98.105 ;
     RECT  38.772 98.077 38.79 98.177 ;
     RECT  20.664 98.041 20.862 98.213 ;
     RECT  40.215 97.771 41.778 98.213 ;
     RECT  43.344 98.221 43.362 98.339 ;
     RECT  0.108 98.299 0.126 98.375 ;
     RECT  40.215 98.213 40.59 98.375 ;
     RECT  18.615 96.989 18.897 98.587 ;
     RECT  83.415 98.041 83.826 98.621 ;
     RECT  41.328 98.213 41.778 98.635 ;
     RECT  18.252 98.587 18.897 98.645 ;
     RECT  41.328 98.635 42.426 98.669 ;
     RECT  20.7 98.213 20.862 98.761 ;
     RECT  20.7 98.761 20.934 98.879 ;
     RECT  10.584 98.851 10.602 98.887 ;
     RECT  10.404 98.887 10.602 98.909 ;
     RECT  41.328 98.669 41.418 98.951 ;
     RECT  10.404 98.909 10.422 98.957 ;
     RECT  47.592 99.157 47.61 99.245 ;
     RECT  42.156 98.669 42.426 99.301 ;
     RECT  38.772 99.265 38.79 99.419 ;
     RECT  20.7 98.879 20.898 99.455 ;
     RECT  20.7 99.455 20.718 99.499 ;
     RECT  40.215 98.375 40.497 99.535 ;
     RECT  42.156 99.301 42.498 99.571 ;
     RECT  41.94 99.571 42.75 99.629 ;
     RECT  20.592 99.499 20.718 99.725 ;
     RECT  40.215 99.535 41.13 99.725 ;
     RECT  41.94 99.629 42.498 99.805 ;
     RECT  2.415 97.709 2.697 99.832 ;
     RECT  13.215 95.549 13.497 99.832 ;
     RECT  2.304 99.832 2.697 99.869 ;
     RECT  13.104 99.832 13.497 99.869 ;
     RECT  41.4 99.805 42.498 99.959 ;
     RECT  20.7 99.725 20.718 99.995 ;
     RECT  85.5 98.851 85.518 100.157 ;
     RECT  43.524 100.111 43.542 100.201 ;
     RECT  43.308 100.201 43.542 100.229 ;
     RECT  43.308 100.229 43.434 100.499 ;
     RECT  46.944 100.381 46.962 100.499 ;
     RECT  0.108 100.123 0.126 100.535 ;
     RECT  20.772 100.507 20.79 100.544 ;
     RECT  41.508 99.959 42.498 100.643 ;
     RECT  38.772 100.651 38.79 100.805 ;
     RECT  80.964 100.741 80.982 100.877 ;
     RECT  86.292 100.459 86.31 100.877 ;
     RECT  41.616 100.643 42.498 100.921 ;
     RECT  43.308 100.499 43.326 100.921 ;
     RECT  10.656 100.507 10.674 101.035 ;
     RECT  44.46 100.849 44.478 101.039 ;
     RECT  47.052 100.849 47.07 101.069 ;
     RECT  10.44 101.035 10.674 101.075 ;
     RECT  20.808 100.651 21.042 101.075 ;
     RECT  21.456 101.371 21.474 101.461 ;
     RECT  41.616 100.921 43.326 101.461 ;
     RECT  21.456 101.461 21.69 101.579 ;
     RECT  41.616 101.461 43.362 101.615 ;
     RECT  41.616 101.615 42.966 101.695 ;
     RECT  9.684 101.659 9.702 101.885 ;
     RECT  20.7 101.731 20.718 101.885 ;
     RECT  47.376 101.731 47.394 101.885 ;
     RECT  10.584 101.075 10.602 101.899 ;
     RECT  41.328 101.695 42.966 101.921 ;
     RECT  2.415 99.869 2.697 101.992 ;
     RECT  6.84 101.899 6.858 102.029 ;
     RECT  43.776 102.001 43.794 102.119 ;
     RECT  10.332 101.899 10.602 102.155 ;
     RECT  46.656 102.127 46.674 102.227 ;
     RECT  21.456 101.579 21.474 102.379 ;
     RECT  21.24 102.379 21.474 102.389 ;
     RECT  0.144 102.283 0.162 102.425 ;
     RECT  10.872 102.379 10.89 102.425 ;
     RECT  21.24 102.389 21.258 102.425 ;
     RECT  41.58 101.921 42.966 102.425 ;
     RECT  40.215 99.725 40.497 102.505 ;
     RECT  13.215 99.869 13.497 102.523 ;
     RECT  13.104 102.523 13.497 102.569 ;
     RECT  2.304 101.992 2.697 102.605 ;
     RECT  86.292 101.995 86.31 102.605 ;
     RECT  39.924 102.505 40.497 102.659 ;
     RECT  43.92 102.541 43.938 102.659 ;
     RECT  19.944 102.523 19.962 102.695 ;
     RECT  82.044 102.427 82.062 102.695 ;
     RECT  41.58 102.425 41.814 102.775 ;
     RECT  41.22 102.775 41.814 102.929 ;
     RECT  41.436 102.929 41.814 102.965 ;
     RECT  10.332 103 10.35 103.037 ;
     RECT  42.552 102.425 42.966 103.171 ;
     RECT  21.204 103.315 21.222 103.469 ;
     RECT  6.84 102.907 6.858 103.505 ;
     RECT  7.815 97.835 8.097 103.531 ;
     RECT  42.372 103.171 42.966 103.711 ;
     RECT  7.416 103.531 8.097 103.775 ;
     RECT  19.944 103.711 19.962 103.811 ;
     RECT  45.615 91.229 45.897 103.819 ;
     RECT  41.4 103.711 41.418 103.883 ;
     RECT  45.615 103.819 46.026 103.919 ;
     RECT  2.415 102.605 2.697 104.152 ;
     RECT  85.5 101.281 85.518 104.189 ;
     RECT  21.456 104.161 21.474 104.251 ;
     RECT  42.156 103.711 43.182 104.287 ;
     RECT  3.996 103.819 4.014 104.315 ;
     RECT  83.415 98.621 83.697 104.323 ;
     RECT  21.24 104.251 21.474 104.351 ;
     RECT  46.944 104.287 46.962 104.351 ;
     RECT  83.415 104.323 83.79 104.477 ;
     RECT  39.348 104.287 39.366 104.549 ;
     RECT  0.108 104.443 0.126 104.585 ;
     RECT  41.508 104.287 43.182 104.585 ;
     RECT  20.448 104.521 20.466 104.693 ;
     RECT  2.304 104.152 2.697 104.765 ;
     RECT  41.508 104.585 42.246 104.791 ;
     RECT  10.548 104.701 10.566 104.819 ;
     RECT  85.464 104.731 85.482 104.819 ;
     RECT  20.664 104.701 20.682 104.855 ;
     RECT  9.144 104.827 9.162 104.864 ;
     RECT  40.215 102.659 40.497 104.875 ;
     RECT  41.22 104.791 42.246 104.875 ;
     RECT  21.42 104.351 21.474 104.971 ;
     RECT  50.256 94.877 50.274 105.061 ;
     RECT  51.015 94.877 51.297 105.061 ;
     RECT  21.42 104.971 21.618 105.089 ;
     RECT  85.5 105.061 85.518 105.097 ;
     RECT  85.5 105.097 85.59 105.101 ;
     RECT  21.42 105.089 21.438 105.125 ;
     RECT  6.84 104.683 6.858 105.197 ;
     RECT  10.764 105.16 10.998 105.197 ;
     RECT  14.796 105.067 14.814 105.197 ;
     RECT  40.215 104.875 42.246 105.233 ;
     RECT  50.256 105.061 51.297 105.233 ;
     RECT  45.615 103.919 45.897 105.241 ;
     RECT  48.816 105.097 48.834 105.269 ;
     RECT  40.215 105.233 42.174 105.293 ;
     RECT  83.415 104.477 83.697 105.331 ;
     RECT  20.952 105.241 20.97 105.359 ;
     RECT  44.784 105.241 45.897 105.359 ;
     RECT  85.572 105.101 85.59 105.389 ;
     RECT  44.784 105.359 44.802 105.395 ;
     RECT  42.984 104.585 43.182 105.511 ;
     RECT  2.415 104.765 2.697 105.587 ;
     RECT  7.815 103.775 8.097 105.587 ;
     RECT  13.215 102.569 13.497 105.587 ;
     RECT  18.615 98.645 18.897 105.587 ;
     RECT  24.015 2.413 24.297 105.587 ;
     RECT  29.415 13.703 29.697 105.587 ;
     RECT  34.815 7.088 35.097 105.587 ;
     RECT  45.615 105.359 45.897 105.587 ;
     RECT  51.015 105.233 51.297 105.587 ;
     RECT  56.415 91.229 56.697 105.587 ;
     RECT  61.815 94.733 62.097 105.587 ;
     RECT  67.215 94.877 67.497 105.587 ;
     RECT  72.615 2.413 72.897 105.587 ;
     RECT  78.015 94.733 78.297 105.587 ;
     RECT  40.215 105.293 42.102 105.629 ;
     RECT  42.984 105.511 43.362 105.629 ;
     RECT  40.215 105.629 41.49 105.665 ;
     RECT  42.984 105.629 43.002 105.665 ;
     RECT  10.368 105.637 10.386 105.691 ;
     RECT  83.415 105.331 83.826 105.725 ;
     RECT  10.188 105.691 10.386 105.773 ;
     RECT  10.368 105.773 10.386 105.809 ;
     RECT  2.415 105.587 2.505 105.857 ;
     RECT  7.815 105.587 7.905 105.857 ;
     RECT  13.215 105.587 13.305 105.857 ;
     RECT  18.615 105.587 18.705 105.857 ;
     RECT  24.015 105.587 24.105 105.857 ;
     RECT  29.415 105.587 29.505 105.857 ;
     RECT  34.815 105.587 34.905 105.857 ;
     RECT  40.215 105.665 40.305 105.857 ;
     RECT  45.615 105.587 45.705 105.857 ;
     RECT  51.015 105.587 51.105 105.857 ;
     RECT  56.415 105.587 56.505 105.857 ;
     RECT  61.815 105.587 61.905 105.857 ;
     RECT  67.215 105.587 67.305 105.857 ;
     RECT  72.615 105.587 72.705 105.857 ;
     RECT  78.015 105.587 78.105 105.857 ;
     RECT  83.415 105.725 83.505 105.857 ;
     RECT  50.256 105.233 50.274 107.213 ;
    LAYER M4 ;
     RECT  0.097 4.848 0.137 4.968 ;
     RECT  0.084 17.424 0.137 17.448 ;
     RECT  0.06 17.448 0.137 17.712 ;
     RECT  0.084 17.712 0.137 17.736 ;
     RECT  0.06 17.736 0.137 18.048 ;
     RECT  0.084 18.048 0.137 18.072 ;
     RECT  0.06 18.072 0.137 18.336 ;
     RECT  0.084 18.336 0.137 18.36 ;
     RECT  0.06 18.36 0.137 18.672 ;
     RECT  0.084 18.672 0.137 18.696 ;
     RECT  0.06 18.696 0.137 18.96 ;
     RECT  0.084 18.96 0.137 18.984 ;
     RECT  0.06 18.984 0.137 19.248 ;
     RECT  0.084 19.248 0.137 19.272 ;
     RECT  0.06 19.272 0.137 19.584 ;
     RECT  0.084 19.584 0.137 19.608 ;
     RECT  0.06 19.608 0.137 19.872 ;
     RECT  0.084 19.872 0.137 19.896 ;
     RECT  0.06 19.896 0.137 20.208 ;
     RECT  0.084 20.208 0.137 20.232 ;
     RECT  0.06 20.232 0.137 20.496 ;
     RECT  0.084 20.496 0.137 20.52 ;
     RECT  0.06 20.52 0.137 20.784 ;
     RECT  0.084 20.784 0.137 20.808 ;
     RECT  0.06 20.808 0.137 21.12 ;
     RECT  0.084 21.12 0.137 21.144 ;
     RECT  0.06 21.144 0.137 21.408 ;
     RECT  0.084 21.408 0.137 21.432 ;
     RECT  0.06 21.432 0.137 21.744 ;
     RECT  0.084 21.744 0.137 21.768 ;
     RECT  0.06 21.768 0.137 22.032 ;
     RECT  0.084 22.032 0.137 22.056 ;
     RECT  0.06 22.056 0.137 22.32 ;
     RECT  0.084 22.32 0.137 22.344 ;
     RECT  0.06 22.344 0.137 22.656 ;
     RECT  0.084 22.656 0.137 22.68 ;
     RECT  0.06 22.68 0.137 22.944 ;
     RECT  0.084 22.944 0.137 22.968 ;
     RECT  0.06 22.968 0.137 23.28 ;
     RECT  0.084 23.28 0.137 23.304 ;
     RECT  0.06 23.304 0.137 23.568 ;
     RECT  0.084 23.568 0.137 23.592 ;
     RECT  0.06 23.592 0.137 23.856 ;
     RECT  0.084 23.856 0.137 23.88 ;
     RECT  0.06 23.88 0.137 24.192 ;
     RECT  0.084 24.192 0.137 24.216 ;
     RECT  0.06 24.216 0.137 24.48 ;
     RECT  0.084 24.48 0.137 24.504 ;
     RECT  0.06 24.504 0.137 24.816 ;
     RECT  0.084 24.816 0.137 24.84 ;
     RECT  0.06 24.84 0.137 25.104 ;
     RECT  0.084 25.104 0.137 25.128 ;
     RECT  0.06 25.128 0.137 25.44 ;
     RECT  0.084 25.44 0.137 25.464 ;
     RECT  0.06 25.464 0.137 25.728 ;
     RECT  0.084 25.728 0.137 25.752 ;
     RECT  0.06 25.752 0.137 26.016 ;
     RECT  0.084 26.016 0.137 26.04 ;
     RECT  0.06 26.04 0.137 26.352 ;
     RECT  0.084 26.352 0.137 26.376 ;
     RECT  0.06 26.376 0.137 26.64 ;
     RECT  0.084 26.64 0.137 26.664 ;
     RECT  0.06 26.664 0.137 26.976 ;
     RECT  0.084 26.976 0.137 27 ;
     RECT  0.06 27 0.137 27.264 ;
     RECT  0.084 27.264 0.137 27.288 ;
     RECT  0.06 27.288 0.137 27.552 ;
     RECT  0.084 27.552 0.137 27.576 ;
     RECT  0.06 27.576 0.137 27.888 ;
     RECT  0.084 27.888 0.137 27.912 ;
     RECT  0.06 27.912 0.137 28.176 ;
     RECT  0.084 28.176 0.137 28.2 ;
     RECT  0.06 28.2 0.137 28.512 ;
     RECT  0.084 28.512 0.137 28.536 ;
     RECT  0.06 28.536 0.137 28.8 ;
     RECT  0.084 28.8 0.137 28.824 ;
     RECT  0.06 28.824 0.137 29.088 ;
     RECT  0.084 29.088 0.137 29.112 ;
     RECT  0.06 29.112 0.137 29.424 ;
     RECT  0.084 29.424 0.137 29.448 ;
     RECT  0.06 29.448 0.137 29.712 ;
     RECT  0.084 29.712 0.137 29.736 ;
     RECT  0.06 29.736 0.137 30.048 ;
     RECT  0.084 30.048 0.137 30.072 ;
     RECT  0.06 30.072 0.137 30.336 ;
     RECT  0.084 30.336 0.137 30.36 ;
     RECT  0.06 30.36 0.137 30.624 ;
     RECT  0.084 30.624 0.137 30.648 ;
     RECT  0.06 30.648 0.137 30.96 ;
     RECT  0.084 30.96 0.137 30.984 ;
     RECT  0.06 30.984 0.137 31.248 ;
     RECT  0.084 31.248 0.137 31.272 ;
     RECT  0.06 31.272 0.137 31.584 ;
     RECT  0.084 31.584 0.137 31.608 ;
     RECT  0.06 31.608 0.137 31.872 ;
     RECT  0.084 31.872 0.137 31.896 ;
     RECT  0.06 31.896 0.137 32.16 ;
     RECT  0.084 32.16 0.137 32.184 ;
     RECT  0.06 32.184 0.137 32.496 ;
     RECT  0.084 32.496 0.137 32.52 ;
     RECT  0.06 32.52 0.137 32.784 ;
     RECT  0.084 32.784 0.137 32.808 ;
     RECT  0.06 32.808 0.137 33.12 ;
     RECT  0.084 33.12 0.137 33.144 ;
     RECT  0.06 33.144 0.137 33.408 ;
     RECT  0.084 33.408 0.137 33.432 ;
     RECT  0.06 33.432 0.137 33.696 ;
     RECT  0.084 33.696 0.137 33.72 ;
     RECT  0.06 33.72 0.137 34.032 ;
     RECT  0.084 34.032 0.137 34.056 ;
     RECT  0.06 34.056 0.137 34.32 ;
     RECT  0.084 34.32 0.137 34.344 ;
     RECT  0.06 34.344 0.137 34.656 ;
     RECT  0.084 34.656 0.137 34.68 ;
     RECT  0.06 34.68 0.137 34.944 ;
     RECT  0.084 34.944 0.137 34.968 ;
     RECT  0.06 34.968 0.137 35.28 ;
     RECT  0.084 35.28 0.137 35.304 ;
     RECT  0.06 35.304 0.137 35.568 ;
     RECT  0.084 35.568 0.137 35.592 ;
     RECT  0.06 35.592 0.137 35.856 ;
     RECT  0.084 35.856 0.137 35.88 ;
     RECT  0.06 35.88 0.137 36.192 ;
     RECT  0.084 36.192 0.137 36.216 ;
     RECT  0.06 36.216 0.137 36.48 ;
     RECT  0.084 36.48 0.137 36.504 ;
     RECT  0.06 36.504 0.137 36.816 ;
     RECT  0.084 36.816 0.137 36.84 ;
     RECT  0.06 36.84 0.137 37.104 ;
     RECT  0.084 37.104 0.137 37.128 ;
     RECT  0.06 37.128 0.137 37.392 ;
     RECT  0.084 37.392 0.137 37.416 ;
     RECT  0.06 37.416 0.137 37.728 ;
     RECT  0.084 37.728 0.137 37.752 ;
     RECT  0.06 37.752 0.137 38.016 ;
     RECT  0.084 38.016 0.137 38.04 ;
     RECT  0.06 38.04 0.137 38.352 ;
     RECT  0.084 38.352 0.137 38.376 ;
     RECT  0.06 38.376 0.137 38.64 ;
     RECT  0.084 38.64 0.137 38.664 ;
     RECT  0.06 38.664 0.137 38.928 ;
     RECT  0.084 38.928 0.137 38.952 ;
     RECT  0.06 38.952 0.137 39.264 ;
     RECT  0.084 39.264 0.137 39.288 ;
     RECT  0.06 39.288 0.137 39.552 ;
     RECT  0.084 39.552 0.137 39.576 ;
     RECT  0.06 39.576 0.137 39.888 ;
     RECT  0.084 39.888 0.137 39.912 ;
     RECT  0.06 39.912 0.137 40.176 ;
     RECT  0.084 40.176 0.137 40.2 ;
     RECT  0.06 40.2 0.137 40.464 ;
     RECT  0.084 40.464 0.137 40.488 ;
     RECT  0.06 40.488 0.137 40.8 ;
     RECT  0.084 40.8 0.137 40.824 ;
     RECT  0.06 40.824 0.137 41.088 ;
     RECT  0.084 41.088 0.137 41.112 ;
     RECT  0.06 41.112 0.137 41.424 ;
     RECT  0.084 41.424 0.137 41.448 ;
     RECT  0.06 41.448 0.137 41.712 ;
     RECT  0.084 41.712 0.137 41.736 ;
     RECT  0.06 41.736 0.137 42 ;
     RECT  0.084 42 0.137 42.024 ;
     RECT  0.06 42.024 0.137 42.336 ;
     RECT  0.084 42.336 0.137 42.36 ;
     RECT  0.06 42.36 0.137 42.624 ;
     RECT  0.084 42.624 0.137 42.648 ;
     RECT  0.06 42.648 0.137 42.96 ;
     RECT  0.084 42.96 0.137 42.984 ;
     RECT  0.06 42.984 0.137 43.248 ;
     RECT  0.084 43.248 0.137 43.272 ;
     RECT  0.06 43.272 0.137 43.536 ;
     RECT  0.084 43.536 0.137 43.56 ;
     RECT  0.06 43.56 0.137 43.872 ;
     RECT  0.084 43.872 0.137 43.896 ;
     RECT  0.06 43.896 0.137 44.16 ;
     RECT  0.084 44.16 0.137 44.184 ;
     RECT  0.06 44.184 0.137 44.496 ;
     RECT  0.084 44.496 0.137 44.52 ;
     RECT  0.06 44.52 0.137 44.784 ;
     RECT  0.084 44.784 0.137 44.808 ;
     RECT  0.06 44.808 0.137 45.12 ;
     RECT  0.084 45.12 0.137 45.144 ;
     RECT  0.06 45.144 0.137 45.408 ;
     RECT  0.084 45.408 0.137 45.432 ;
     RECT  0.06 45.432 0.137 45.696 ;
     RECT  0.084 45.696 0.137 45.72 ;
     RECT  0.06 45.72 0.137 46.032 ;
     RECT  0.084 46.032 0.137 46.056 ;
     RECT  0.06 46.056 0.137 46.32 ;
     RECT  0.084 46.32 0.137 46.344 ;
     RECT  0.06 46.344 0.137 46.656 ;
     RECT  0.084 46.656 0.137 46.68 ;
     RECT  0.06 46.68 0.137 46.944 ;
     RECT  0.084 46.944 0.137 46.968 ;
     RECT  0.06 46.968 0.137 47.232 ;
     RECT  0.084 47.232 0.137 47.256 ;
     RECT  0.06 47.256 0.137 47.568 ;
     RECT  0.084 47.568 0.137 47.592 ;
     RECT  0.06 47.592 0.137 47.856 ;
     RECT  0.084 47.856 0.137 47.88 ;
     RECT  0.06 47.88 0.137 48.192 ;
     RECT  0.084 48.192 0.137 48.216 ;
     RECT  0.06 48.216 0.137 48.48 ;
     RECT  0.084 48.48 0.137 48.504 ;
     RECT  0.06 48.504 0.137 48.768 ;
     RECT  0.084 48.768 0.137 48.792 ;
     RECT  0.06 48.792 0.137 49.104 ;
     RECT  0.084 49.104 0.137 49.128 ;
     RECT  0.06 49.128 0.137 49.392 ;
     RECT  0.084 49.392 0.137 49.416 ;
     RECT  0.06 49.416 0.137 49.728 ;
     RECT  0.084 49.728 0.137 49.752 ;
     RECT  0.06 49.752 0.137 50.016 ;
     RECT  0.084 50.016 0.137 50.04 ;
     RECT  0.06 50.04 0.137 50.304 ;
     RECT  0.084 50.304 0.137 50.328 ;
     RECT  0.06 50.328 0.137 50.64 ;
     RECT  0.084 50.64 0.137 50.664 ;
     RECT  0.06 50.664 0.137 50.928 ;
     RECT  0.084 50.928 0.137 50.952 ;
     RECT  0.06 50.952 0.137 51.264 ;
     RECT  0.084 51.264 0.137 51.288 ;
     RECT  0.06 51.288 0.137 51.552 ;
     RECT  0.084 51.552 0.137 51.576 ;
     RECT  0.06 51.576 0.137 51.84 ;
     RECT  0.084 51.84 0.137 51.864 ;
     RECT  0.06 51.864 0.137 52.176 ;
     RECT  0.084 52.176 0.137 52.2 ;
     RECT  0.06 52.2 0.137 52.464 ;
     RECT  0.084 52.464 0.137 52.488 ;
     RECT  0.06 52.488 0.137 52.8 ;
     RECT  0.084 52.8 0.137 52.824 ;
     RECT  0.06 52.824 0.137 53.088 ;
     RECT  0.084 53.088 0.137 53.112 ;
     RECT  0.06 53.112 0.137 53.376 ;
     RECT  0.084 53.376 0.137 53.4 ;
     RECT  0.06 53.4 0.137 53.712 ;
     RECT  0.084 53.712 0.137 53.736 ;
     RECT  0.06 53.736 0.137 54 ;
     RECT  0.084 54 0.137 54.024 ;
     RECT  0.06 54.024 0.137 54.336 ;
     RECT  0.084 54.336 0.137 54.36 ;
     RECT  0.06 54.36 0.137 54.624 ;
     RECT  0.084 54.624 0.137 54.648 ;
     RECT  0.06 54.648 0.137 54.96 ;
     RECT  0.084 54.96 0.137 54.984 ;
     RECT  0.06 54.984 0.137 55.248 ;
     RECT  0.084 55.248 0.137 55.272 ;
     RECT  0.06 55.272 0.137 55.536 ;
     RECT  0.084 55.536 0.137 55.56 ;
     RECT  0.06 55.56 0.137 55.872 ;
     RECT  0.084 55.872 0.137 55.896 ;
     RECT  0.06 55.896 0.137 56.16 ;
     RECT  0.084 56.16 0.137 56.184 ;
     RECT  0.06 56.184 0.137 56.496 ;
     RECT  0.084 56.496 0.137 56.52 ;
     RECT  0.06 56.52 0.137 56.784 ;
     RECT  0.084 56.784 0.137 56.808 ;
     RECT  0.06 56.808 0.137 57.072 ;
     RECT  0.084 57.072 0.137 57.096 ;
     RECT  0.06 57.096 0.137 57.408 ;
     RECT  0.084 57.408 0.137 57.432 ;
     RECT  0.06 57.432 0.137 57.696 ;
     RECT  0.084 57.696 0.137 57.72 ;
     RECT  0.06 57.72 0.137 58.032 ;
     RECT  0.084 58.032 0.137 58.056 ;
     RECT  0.06 58.056 0.137 58.32 ;
     RECT  0.084 58.32 0.137 58.344 ;
     RECT  0.06 58.344 0.137 58.608 ;
     RECT  0.084 58.608 0.137 58.632 ;
     RECT  0.06 58.632 0.137 58.944 ;
     RECT  0.084 58.944 0.137 58.968 ;
     RECT  0.06 58.968 0.137 59.232 ;
     RECT  0.084 59.232 0.137 59.256 ;
     RECT  0.06 59.256 0.137 59.568 ;
     RECT  0.084 59.568 0.137 59.592 ;
     RECT  0.06 59.592 0.137 59.856 ;
     RECT  0.084 59.856 0.137 59.88 ;
     RECT  0.06 59.88 0.137 60.144 ;
     RECT  0.084 60.144 0.137 60.168 ;
     RECT  0.06 60.168 0.137 60.48 ;
     RECT  0.084 60.48 0.137 60.504 ;
     RECT  0.06 60.504 0.137 60.768 ;
     RECT  0.084 60.768 0.137 60.792 ;
     RECT  0.06 60.792 0.137 61.104 ;
     RECT  0.084 61.104 0.137 61.128 ;
     RECT  0.06 61.128 0.137 61.392 ;
     RECT  0.084 61.392 0.137 61.416 ;
     RECT  0.06 61.416 0.137 61.68 ;
     RECT  0.084 61.68 0.137 61.704 ;
     RECT  0.06 61.704 0.137 62.016 ;
     RECT  0.084 62.016 0.137 62.04 ;
     RECT  0.06 62.04 0.137 62.304 ;
     RECT  0.084 62.304 0.137 62.328 ;
     RECT  0.06 62.328 0.137 62.64 ;
     RECT  0.084 62.64 0.137 62.664 ;
     RECT  0.06 62.664 0.137 62.928 ;
     RECT  0.084 62.928 0.137 62.952 ;
     RECT  0.06 62.952 0.137 63.216 ;
     RECT  0.084 63.216 0.137 63.24 ;
     RECT  0.06 63.24 0.137 63.552 ;
     RECT  0.084 63.552 0.137 63.576 ;
     RECT  0.06 63.576 0.137 63.84 ;
     RECT  0.084 63.84 0.137 63.864 ;
     RECT  0.06 63.864 0.137 64.176 ;
     RECT  0.084 64.176 0.137 64.2 ;
     RECT  0.06 64.2 0.137 64.464 ;
     RECT  0.084 64.464 0.137 64.488 ;
     RECT  0.06 64.488 0.137 64.8 ;
     RECT  0.084 64.8 0.137 64.824 ;
     RECT  0.06 64.824 0.137 65.088 ;
     RECT  0.084 65.088 0.137 65.112 ;
     RECT  0.06 65.112 0.137 65.376 ;
     RECT  0.084 65.376 0.137 65.4 ;
     RECT  0.06 65.4 0.137 65.712 ;
     RECT  0.084 65.712 0.137 65.736 ;
     RECT  0.06 65.736 0.137 66 ;
     RECT  0.084 66 0.137 66.024 ;
     RECT  0.06 66.024 0.137 66.336 ;
     RECT  0.084 66.336 0.137 66.36 ;
     RECT  0.06 66.36 0.137 66.624 ;
     RECT  0.084 66.624 0.137 66.648 ;
     RECT  0.06 66.648 0.137 66.912 ;
     RECT  0.084 66.912 0.137 66.936 ;
     RECT  0.06 66.936 0.137 67.248 ;
     RECT  0.084 67.248 0.137 67.272 ;
     RECT  0.06 67.272 0.137 67.536 ;
     RECT  0.084 67.536 0.137 67.56 ;
     RECT  0.06 67.56 0.137 67.872 ;
     RECT  0.084 67.872 0.137 67.896 ;
     RECT  0.06 67.896 0.137 68.16 ;
     RECT  0.084 68.16 0.137 68.184 ;
     RECT  0.06 68.184 0.137 68.448 ;
     RECT  0.084 68.448 0.137 68.472 ;
     RECT  0.06 68.472 0.137 68.784 ;
     RECT  0.084 68.784 0.137 68.808 ;
     RECT  0.06 68.808 0.137 69.072 ;
     RECT  0.084 69.072 0.137 69.096 ;
     RECT  0.06 69.096 0.137 69.408 ;
     RECT  0.084 69.408 0.137 69.432 ;
     RECT  0.06 69.432 0.137 69.696 ;
     RECT  0.084 69.696 0.137 69.72 ;
     RECT  0.06 69.72 0.137 69.984 ;
     RECT  0.084 69.984 0.137 70.008 ;
     RECT  0.06 70.008 0.137 70.32 ;
     RECT  0.084 70.32 0.137 70.344 ;
     RECT  0.06 70.344 0.137 70.608 ;
     RECT  0.084 70.608 0.137 70.632 ;
     RECT  0.06 70.632 0.137 70.944 ;
     RECT  0.084 70.944 0.137 70.968 ;
     RECT  0.06 70.968 0.137 71.232 ;
     RECT  0.084 71.232 0.137 71.256 ;
     RECT  0.06 71.256 0.137 71.52 ;
     RECT  0.084 71.52 0.137 71.544 ;
     RECT  0.06 71.544 0.137 71.856 ;
     RECT  0.084 71.856 0.137 71.88 ;
     RECT  0.06 71.88 0.137 72.144 ;
     RECT  0.084 72.144 0.137 72.168 ;
     RECT  0.06 72.168 0.137 72.48 ;
     RECT  0.084 72.48 0.137 72.504 ;
     RECT  0.06 72.504 0.137 72.768 ;
     RECT  0.084 72.768 0.137 72.792 ;
     RECT  0.06 72.792 0.137 73.056 ;
     RECT  0.084 73.056 0.137 73.08 ;
     RECT  0.06 73.08 0.137 73.392 ;
     RECT  0.084 73.392 0.137 73.416 ;
     RECT  0.06 73.416 0.137 73.68 ;
     RECT  0.084 73.68 0.137 73.704 ;
     RECT  0.06 73.704 0.137 74.016 ;
     RECT  0.084 74.016 0.137 74.04 ;
     RECT  0.06 74.04 0.137 74.304 ;
     RECT  0.084 74.304 0.137 74.328 ;
     RECT  0.06 74.328 0.137 74.64 ;
     RECT  0.084 74.64 0.137 74.664 ;
     RECT  0.06 74.664 0.137 74.928 ;
     RECT  0.084 74.928 0.137 74.952 ;
     RECT  0.06 74.952 0.137 75.216 ;
     RECT  0.084 75.216 0.137 75.24 ;
     RECT  0.06 75.24 0.137 75.552 ;
     RECT  0.084 75.552 0.137 75.576 ;
     RECT  0.06 75.576 0.137 75.84 ;
     RECT  0.084 75.84 0.137 75.864 ;
     RECT  0.06 75.864 0.137 76.176 ;
     RECT  0.084 76.176 0.137 76.2 ;
     RECT  0.06 76.2 0.137 76.464 ;
     RECT  0.084 76.464 0.137 76.488 ;
     RECT  0.06 76.488 0.137 76.752 ;
     RECT  0.084 76.752 0.137 76.776 ;
     RECT  0.06 76.776 0.137 77.088 ;
     RECT  0.084 77.088 0.137 77.112 ;
     RECT  0.06 77.112 0.137 77.376 ;
     RECT  0.084 77.376 0.137 77.4 ;
     RECT  0.06 77.4 0.137 77.712 ;
     RECT  0.084 77.712 0.137 77.736 ;
     RECT  0.06 77.736 0.137 78 ;
     RECT  0.084 78 0.137 78.024 ;
     RECT  0.06 78.024 0.137 78.288 ;
     RECT  0.084 78.288 0.137 78.312 ;
     RECT  0.06 78.312 0.137 78.624 ;
     RECT  0.084 78.624 0.137 78.648 ;
     RECT  0.06 78.648 0.137 78.912 ;
     RECT  0.084 78.912 0.137 78.936 ;
     RECT  0.06 78.936 0.137 79.248 ;
     RECT  0.084 79.248 0.137 79.272 ;
     RECT  0.06 79.272 0.137 79.536 ;
     RECT  0.084 79.536 0.137 79.56 ;
     RECT  0.06 79.56 0.137 79.824 ;
     RECT  0.084 79.824 0.137 79.848 ;
     RECT  0.06 79.848 0.137 80.16 ;
     RECT  0.084 80.16 0.137 80.184 ;
     RECT  0.06 80.184 0.137 80.448 ;
     RECT  0.084 80.448 0.137 80.472 ;
     RECT  0.06 80.472 0.137 80.784 ;
     RECT  0.084 80.784 0.137 80.808 ;
     RECT  0.06 80.808 0.137 81.072 ;
     RECT  0.084 81.072 0.137 81.096 ;
     RECT  0.06 81.096 0.137 81.36 ;
     RECT  0.084 81.36 0.137 81.384 ;
     RECT  0.06 81.384 0.137 81.696 ;
     RECT  0.084 81.696 0.137 81.72 ;
     RECT  0.06 81.72 0.137 81.984 ;
     RECT  0.084 81.984 0.137 82.008 ;
     RECT  0.06 82.008 0.137 82.32 ;
     RECT  0.084 82.32 0.137 82.344 ;
     RECT  0.06 82.344 0.137 82.608 ;
     RECT  0.084 82.608 0.137 82.632 ;
     RECT  0.06 82.632 0.137 82.896 ;
     RECT  0.084 82.896 0.137 82.92 ;
     RECT  0.06 82.92 0.137 83.232 ;
     RECT  0.084 83.232 0.137 83.256 ;
     RECT  0.06 83.256 0.137 83.52 ;
     RECT  0.084 83.52 0.137 83.544 ;
     RECT  0.06 83.544 0.137 83.856 ;
     RECT  0.084 83.856 0.137 83.88 ;
     RECT  0.06 83.88 0.137 84.144 ;
     RECT  0.084 84.144 0.137 84.168 ;
     RECT  0.06 84.168 0.137 84.48 ;
     RECT  0.084 84.48 0.137 84.504 ;
     RECT  0.06 84.504 0.137 84.768 ;
     RECT  0.084 84.768 0.137 84.792 ;
     RECT  0.06 84.792 0.137 85.056 ;
     RECT  0.084 85.056 0.137 85.08 ;
     RECT  0.06 85.08 0.137 85.392 ;
     RECT  0.084 85.392 0.137 85.416 ;
     RECT  0.06 85.416 0.137 85.68 ;
     RECT  0.084 85.68 0.137 85.704 ;
     RECT  0.06 85.704 0.137 86.016 ;
     RECT  0.084 86.016 0.137 86.04 ;
     RECT  0.06 86.04 0.137 86.304 ;
     RECT  0.084 86.304 0.137 86.328 ;
     RECT  0.06 86.328 0.137 86.592 ;
     RECT  0.084 86.592 0.137 86.616 ;
     RECT  0.06 86.616 0.137 86.928 ;
     RECT  0.084 86.928 0.137 86.952 ;
     RECT  0.06 86.952 0.137 87.216 ;
     RECT  0.084 87.216 0.137 87.24 ;
     RECT  0.06 87.24 0.137 87.552 ;
     RECT  0.084 87.552 0.137 87.576 ;
     RECT  0.06 87.576 0.137 87.84 ;
     RECT  0.084 87.84 0.137 87.864 ;
     RECT  0.06 87.864 0.137 88.128 ;
     RECT  0.084 88.128 0.137 88.152 ;
     RECT  0.06 88.152 0.137 88.464 ;
     RECT  0.084 88.464 0.137 88.488 ;
     RECT  0.06 88.488 0.137 88.752 ;
     RECT  0.084 88.752 0.137 88.776 ;
     RECT  0.06 88.776 0.137 89.088 ;
     RECT  0.084 89.088 0.137 89.112 ;
     RECT  0.06 89.112 0.137 89.376 ;
     RECT  0.084 89.376 0.137 89.4 ;
     RECT  0.06 89.4 0.137 89.664 ;
     RECT  0.084 89.664 0.137 89.688 ;
     RECT  0.06 89.688 0.137 90 ;
     RECT  0.084 90 0.137 90.024 ;
     RECT  0.06 90.024 0.137 90.288 ;
     RECT  0.084 90.288 0.137 90.312 ;
     RECT  0.06 90.312 0.137 90.624 ;
     RECT  0.084 90.624 0.137 90.648 ;
     RECT  0.06 90.648 0.137 90.912 ;
     RECT  0.084 90.912 0.137 90.936 ;
     RECT  0.06 90.936 0.137 91.2 ;
     RECT  0.084 91.2 0.137 91.224 ;
     RECT  0.06 91.224 0.137 91.536 ;
     RECT  0.084 91.536 0.137 91.56 ;
     RECT  0.06 91.56 0.137 91.824 ;
     RECT  0.084 91.824 0.137 91.848 ;
     RECT  0.06 91.848 0.137 92.16 ;
     RECT  0.084 92.16 0.137 92.184 ;
     RECT  0.06 92.184 0.137 92.448 ;
     RECT  0.084 92.448 0.137 92.472 ;
     RECT  0.06 92.472 0.137 92.736 ;
     RECT  0.084 92.736 0.137 92.76 ;
     RECT  0.06 92.76 0.137 93.072 ;
     RECT  0.084 93.072 0.137 93.096 ;
     RECT  0.06 93.096 0.137 93.36 ;
     RECT  0.084 93.36 0.137 93.384 ;
     RECT  0.06 93.384 0.137 93.696 ;
     RECT  0.084 93.696 0.137 93.72 ;
     RECT  0.06 93.72 0.137 93.984 ;
     RECT  0.084 93.984 0.137 94.008 ;
     RECT  0.06 94.008 0.137 94.32 ;
     RECT  0.084 94.32 0.137 94.344 ;
     RECT  0.06 94.344 0.137 94.608 ;
     RECT  0.084 94.608 0.137 94.632 ;
     RECT  0.06 94.632 0.137 94.896 ;
     RECT  0.084 94.896 0.137 94.92 ;
     RECT  0.06 94.92 0.137 95.232 ;
     RECT  0.084 95.232 0.137 95.256 ;
     RECT  0.06 95.256 0.137 95.52 ;
     RECT  0.084 95.52 0.137 95.544 ;
     RECT  0.06 95.544 0.137 95.856 ;
     RECT  0.084 95.856 0.137 95.88 ;
     RECT  0.06 95.88 0.137 96.144 ;
     RECT  0.084 96.144 0.137 96.168 ;
     RECT  0.06 96.168 0.137 96.432 ;
     RECT  0.084 96.432 0.137 96.456 ;
     RECT  0.06 96.456 0.137 96.768 ;
     RECT  0.084 96.768 0.137 96.792 ;
     RECT  0.06 96.792 0.137 97.056 ;
     RECT  0.084 97.056 0.137 97.08 ;
     RECT  0.06 97.08 0.137 97.392 ;
     RECT  0.084 97.392 0.137 97.416 ;
     RECT  0.06 97.416 0.137 97.68 ;
     RECT  0.084 97.68 0.137 97.704 ;
     RECT  0.06 97.704 0.137 97.968 ;
     RECT  0.084 97.968 0.137 97.992 ;
     RECT  0.06 97.992 0.137 98.304 ;
     RECT  0.084 98.304 0.137 98.328 ;
     RECT  0.06 98.328 0.137 98.592 ;
     RECT  0.084 98.592 0.137 98.616 ;
     RECT  0.06 98.616 0.137 98.928 ;
     RECT  0.084 98.928 0.137 98.952 ;
     RECT  0.06 98.952 0.137 99.216 ;
     RECT  0.084 99.216 0.137 99.24 ;
     RECT  0.06 99.24 0.137 99.504 ;
     RECT  0.084 99.504 0.137 99.528 ;
     RECT  0.06 99.528 0.137 99.84 ;
     RECT  0.084 99.84 0.137 99.864 ;
     RECT  0.06 99.864 0.137 100.128 ;
     RECT  0.084 100.128 0.137 100.152 ;
     RECT  0.06 100.152 0.137 100.464 ;
     RECT  0.084 100.464 0.137 100.488 ;
     RECT  0.06 100.488 0.137 100.752 ;
     RECT  0.084 100.752 0.137 100.776 ;
     RECT  0.06 100.776 0.137 101.04 ;
     RECT  0.084 101.04 0.137 101.064 ;
     RECT  0.06 101.064 0.137 101.376 ;
     RECT  0.084 101.376 0.137 101.4 ;
     RECT  0.06 101.4 0.137 101.664 ;
     RECT  0.084 101.664 0.137 101.688 ;
     RECT  0.06 101.688 0.137 102 ;
     RECT  0.084 102 0.137 102.024 ;
     RECT  0.06 102.024 0.137 102.288 ;
     RECT  0.084 102.288 0.137 102.312 ;
     RECT  0.06 102.312 0.137 102.576 ;
     RECT  0.084 102.576 0.137 102.6 ;
     RECT  0.06 102.6 0.137 102.912 ;
     RECT  0.084 102.912 0.137 102.936 ;
     RECT  0.06 102.936 0.137 103.2 ;
     RECT  0.084 103.2 0.137 103.224 ;
     RECT  0.06 103.224 0.137 103.536 ;
     RECT  0.084 103.536 0.137 103.56 ;
     RECT  0.06 103.56 0.137 103.824 ;
     RECT  0.084 103.824 0.137 103.848 ;
     RECT  0.06 103.848 0.137 104.16 ;
     RECT  0.084 104.16 0.137 104.184 ;
     RECT  0.06 104.184 0.137 104.448 ;
     RECT  0.084 104.448 0.137 104.472 ;
     RECT  0.06 104.472 0.137 104.736 ;
     RECT  0.084 104.736 0.137 104.76 ;
     RECT  0.06 104.76 0.137 105.072 ;
     RECT  0.084 105.072 0.137 105.096 ;
     RECT  0.06 105.096 0.137 105.36 ;
     RECT  0.084 105.36 0.137 105.384 ;
     RECT  0.06 105.384 0.137 105.696 ;
     RECT  0.084 105.696 0.137 105.72 ;
     RECT  0.137 34.656 0.173 105.72 ;
     RECT  0.173 38.928 0.179 42.024 ;
     RECT  0.137 4.944 2.408 4.968 ;
     RECT  0.137 17.424 2.408 33.432 ;
     RECT  0.173 34.656 2.408 35.592 ;
     RECT  0.173 36.816 2.408 37.752 ;
     RECT  0.179 39.264 2.408 42.024 ;
     RECT  0.173 43.248 2.408 44.184 ;
     RECT  0.173 45.408 2.408 105.72 ;
     RECT  2.408 2.148 2.512 105.852 ;
     RECT  2.512 2.418 2.704 105.72 ;
     RECT  2.704 45.408 4.025 105.72 ;
     RECT  2.704 2.64 7.808 2.664 ;
     RECT  2.704 4.8 7.808 4.824 ;
     RECT  2.704 9.12 7.808 9.144 ;
     RECT  2.704 11.376 7.808 11.4 ;
     RECT  2.704 13.44 7.808 13.464 ;
     RECT  2.704 17.424 7.808 33.432 ;
     RECT  2.704 34.656 7.808 35.592 ;
     RECT  2.704 36.816 7.808 37.752 ;
     RECT  2.704 39.264 7.808 42.024 ;
     RECT  2.704 43.248 7.808 44.184 ;
     RECT  4.025 45.408 7.808 103.56 ;
     RECT  4.025 104.688 7.808 105.72 ;
     RECT  7.808 2.148 7.912 105.852 ;
     RECT  7.912 2.418 8.104 105.72 ;
     RECT  8.104 17.424 8.165 19.608 ;
     RECT  8.104 21.744 8.165 28.824 ;
     RECT  8.104 30.336 8.165 33.432 ;
     RECT  8.104 36.816 8.165 37.416 ;
     RECT  8.104 52.176 8.165 74.04 ;
     RECT  8.104 75.216 8.165 83.88 ;
     RECT  8.104 88.464 8.165 88.776 ;
     RECT  8.104 90 8.165 96.456 ;
     RECT  8.104 104.832 9.173 105.72 ;
     RECT  9.173 105.168 10.217 105.72 ;
     RECT  8.104 98.592 10.361 103.032 ;
     RECT  8.104 34.656 10.465 35.304 ;
     RECT  8.104 39.264 10.573 39.576 ;
     RECT  10.573 38.976 10.681 39.576 ;
     RECT  8.104 40.56 10.681 42.024 ;
     RECT  8.104 4.8 10.825 4.824 ;
     RECT  10.825 4.704 10.865 4.824 ;
     RECT  10.865 4.704 13.208 4.728 ;
     RECT  8.104 13.44 13.208 13.464 ;
     RECT  8.165 18.288 13.208 18.312 ;
     RECT  8.165 21.744 13.208 28.2 ;
     RECT  8.165 31.632 13.208 31.656 ;
     RECT  8.165 33.408 13.208 33.432 ;
     RECT  10.465 34.608 13.208 35.304 ;
     RECT  8.165 36.816 13.208 36.84 ;
     RECT  10.681 38.976 13.208 42.024 ;
     RECT  8.104 43.248 13.208 44.184 ;
     RECT  8.104 45.408 13.208 50.952 ;
     RECT  8.165 52.176 13.208 52.2 ;
     RECT  8.165 53.808 13.208 72.792 ;
     RECT  8.165 74.016 13.208 74.04 ;
     RECT  8.165 75.216 13.208 83.544 ;
     RECT  8.104 85.392 13.208 85.704 ;
     RECT  8.104 86.88 13.208 86.904 ;
     RECT  8.165 88.464 13.208 88.488 ;
     RECT  8.165 90 13.208 94.344 ;
     RECT  8.165 95.52 13.208 96.456 ;
     RECT  10.361 98.592 13.208 101.4 ;
     RECT  10.361 102.384 13.208 102.552 ;
     RECT  10.217 105.168 13.208 105.192 ;
     RECT  13.208 2.148 13.312 105.852 ;
     RECT  13.312 2.418 13.504 105.582 ;
     RECT  13.504 105.168 14.785 105.192 ;
     RECT  14.785 105.072 14.825 105.192 ;
     RECT  13.504 4.8 18.608 4.824 ;
     RECT  13.504 13.44 18.608 13.464 ;
     RECT  13.504 18.288 18.608 18.312 ;
     RECT  13.504 21.744 18.608 28.2 ;
     RECT  13.504 31.632 18.608 31.656 ;
     RECT  13.504 33.408 18.608 33.432 ;
     RECT  13.504 34.608 18.608 35.304 ;
     RECT  13.504 36.816 18.608 36.84 ;
     RECT  13.504 38.976 18.608 42.024 ;
     RECT  13.504 43.248 18.608 44.184 ;
     RECT  13.504 45.408 18.608 50.952 ;
     RECT  13.504 52.176 18.608 52.2 ;
     RECT  13.504 53.808 18.608 72.792 ;
     RECT  13.504 74.016 18.608 74.04 ;
     RECT  13.504 75.216 18.608 83.544 ;
     RECT  13.504 85.392 18.608 85.704 ;
     RECT  13.504 86.88 18.608 86.904 ;
     RECT  13.504 88.464 18.608 88.488 ;
     RECT  13.504 90 18.608 94.344 ;
     RECT  13.504 95.52 18.608 96.456 ;
     RECT  13.504 98.592 18.608 101.4 ;
     RECT  13.504 102.384 18.608 102.552 ;
     RECT  14.825 105.072 18.608 105.096 ;
     RECT  18.608 2.148 18.712 105.852 ;
     RECT  18.712 2.418 18.904 105.582 ;
     RECT  18.904 21.744 18.965 22.344 ;
     RECT  18.904 47.568 18.965 48.792 ;
     RECT  18.904 50.928 18.965 50.952 ;
     RECT  18.904 59.568 18.965 59.592 ;
     RECT  18.904 79.536 18.965 79.56 ;
     RECT  18.904 81.696 18.965 81.72 ;
     RECT  18.904 90.912 18.965 90.936 ;
     RECT  18.904 93.072 18.965 93.096 ;
     RECT  18.904 102.384 19.973 102.552 ;
     RECT  18.965 47.568 20.405 48.408 ;
     RECT  18.904 34.608 20.513 34.632 ;
     RECT  18.904 38.976 20.513 41.928 ;
     RECT  18.904 53.808 20.693 54.072 ;
     RECT  20.513 38.976 20.729 41.112 ;
     RECT  18.904 98.88 20.729 101.4 ;
     RECT  20.729 39.216 20.801 41.112 ;
     RECT  20.729 100.512 20.801 101.4 ;
     RECT  20.801 101.04 20.837 101.4 ;
     RECT  20.693 54.048 20.909 54.072 ;
     RECT  20.729 99.216 20.909 99.24 ;
     RECT  20.801 39.216 20.945 40.296 ;
     RECT  18.904 52.176 20.945 52.2 ;
     RECT  20.945 39.216 21.053 39.768 ;
     RECT  20.405 47.568 21.053 47.592 ;
     RECT  21.053 39.744 21.233 39.768 ;
     RECT  19.973 102.384 21.269 102.408 ;
     RECT  18.904 105.072 21.449 105.096 ;
     RECT  20.837 101.376 21.485 101.4 ;
     RECT  18.904 4.8 21.557 4.824 ;
     RECT  18.904 13.44 22.853 13.464 ;
     RECT  24.008 2.148 24.112 105.852 ;
     RECT  24.112 2.418 24.304 105.582 ;
     RECT  28.853 0.576 28.937 0.6 ;
     RECT  29.077 2.784 29.408 2.808 ;
     RECT  29.005 13.632 29.408 13.656 ;
     RECT  29.408 2.148 29.512 105.852 ;
     RECT  29.512 2.418 29.704 105.582 ;
     RECT  30.437 0.096 30.521 0.12 ;
     RECT  32.101 0.096 32.185 0.12 ;
     RECT  33.577 0.096 33.779 0.12 ;
     RECT  29.704 2.784 34.808 2.808 ;
     RECT  29.704 13.632 34.808 13.656 ;
     RECT  34.808 2.148 34.912 105.852 ;
     RECT  34.912 2.418 35.104 105.582 ;
     RECT  35.104 7.056 36.469 7.08 ;
     RECT  35.104 13.632 36.469 13.656 ;
     RECT  36.469 13.344 36.707 13.656 ;
     RECT  36.469 7.056 36.755 7.272 ;
     RECT  37.493 1.728 37.577 1.752 ;
     RECT  36.755 7.056 38.761 7.08 ;
     RECT  38.761 7.056 38.801 7.176 ;
     RECT  39.077 0.096 39.161 0.12 ;
     RECT  35.104 2.784 40.208 2.808 ;
     RECT  38.801 7.152 40.208 7.176 ;
     RECT  36.707 13.344 40.208 13.368 ;
     RECT  40.165 42.72 40.208 42.744 ;
     RECT  39.337 53.856 40.208 53.88 ;
     RECT  40.208 2.148 40.312 105.852 ;
     RECT  40.312 2.148 40.504 105.582 ;
     RECT  40.504 2.784 40.565 2.808 ;
     RECT  40.741 1.728 40.825 1.752 ;
     RECT  40.504 13.344 41.027 13.368 ;
     RECT  40.504 17.856 41.027 17.88 ;
     RECT  40.504 53.568 41.315 54.072 ;
     RECT  41.315 53.568 41.497 53.88 ;
     RECT  40.504 22.8 41.537 22.824 ;
     RECT  41.497 52.992 41.605 53.88 ;
     RECT  41.605 52.32 41.651 53.88 ;
     RECT  41.708 86.592 41.749 86.616 ;
     RECT  40.504 75.264 41.753 75.288 ;
     RECT  41.749 86.592 41.795 87.528 ;
     RECT  40.504 31.44 41.821 31.464 ;
     RECT  41.821 31.44 41.845 32.184 ;
     RECT  41.641 39.888 41.845 39.912 ;
     RECT  41.533 29.04 41.88 29.064 ;
     RECT  41.88 28.272 41.891 29.064 ;
     RECT  41.845 39.888 41.891 40.728 ;
     RECT  41.845 30.576 41.893 32.184 ;
     RECT  41.569 102.624 41.893 102.648 ;
     RECT  41.845 47.904 41.929 47.928 ;
     RECT  41.852 51.264 41.939 51.288 ;
     RECT  41.893 29.952 41.941 32.184 ;
     RECT  41.929 46.752 41.941 46.776 ;
     RECT  40.504 104.88 41.965 104.904 ;
     RECT  41.795 87.504 41.969 87.528 ;
     RECT  41.941 29.952 41.987 29.976 ;
     RECT  41.821 93.072 41.996 93.096 ;
     RECT  41.9 71.04 42.001 71.064 ;
     RECT  41.941 45.888 42.013 46.776 ;
     RECT  41.891 28.272 42.077 28.296 ;
     RECT  41.989 50.16 42.077 50.184 ;
     RECT  41.996 96.144 42.083 96.984 ;
     RECT  41.941 31.344 42.113 32.184 ;
     RECT  42.001 71.04 42.133 71.832 ;
     RECT  41.965 104.832 42.145 104.904 ;
     RECT  41.605 98.64 42.181 98.664 ;
     RECT  41.893 100.656 42.181 100.68 ;
     RECT  42.101 23.952 42.185 23.976 ;
     RECT  41.651 52.32 42.185 52.344 ;
     RECT  42.001 19.344 42.188 19.368 ;
     RECT  42.133 21.552 42.22 21.576 ;
     RECT  42.188 18.72 42.257 19.368 ;
     RECT  42.257 18.72 42.275 18.84 ;
     RECT  42.181 98.64 42.293 100.68 ;
     RECT  42.001 78.096 42.325 78.12 ;
     RECT  42.013 45.888 42.361 46.488 ;
     RECT  41.929 47.904 42.428 48.84 ;
     RECT  42.001 81.888 42.428 81.912 ;
     RECT  42.361 0.096 42.445 0.12 ;
     RECT  41.857 76.32 42.461 76.344 ;
     RECT  42.428 47.904 42.469 48.888 ;
     RECT  41.651 53.568 42.509 53.88 ;
     RECT  42.293 99.6 42.509 100.68 ;
     RECT  42.469 47.856 42.515 49.608 ;
     RECT  42.428 81.552 42.515 81.912 ;
     RECT  42.236 91.488 42.515 91.512 ;
     RECT  41.929 35.52 42.577 35.544 ;
     RECT  42.229 17.616 42.613 17.64 ;
     RECT  42.461 75.552 42.62 76.344 ;
     RECT  42.325 77.472 42.62 78.12 ;
     RECT  41.996 92.832 42.62 93.096 ;
     RECT  42.001 58.896 42.653 58.92 ;
     RECT  41.605 60.96 42.653 60.984 ;
     RECT  42.133 70.944 42.653 71.832 ;
     RECT  41.996 95.088 42.668 95.112 ;
     RECT  42.62 75.552 42.707 78.12 ;
     RECT  42.62 92.304 42.707 93.096 ;
     RECT  42.668 94.992 42.709 95.112 ;
     RECT  42.083 96.144 42.709 96.168 ;
     RECT  42.515 47.856 42.725 47.928 ;
     RECT  42.145 83.184 42.725 83.208 ;
     RECT  42.661 73.488 42.748 74.088 ;
     RECT  42.707 75.552 42.755 76.392 ;
     RECT  42.707 77.472 42.755 78.12 ;
     RECT  42.709 94.992 42.755 96.168 ;
     RECT  42.668 97.92 42.755 97.944 ;
     RECT  42.145 104.208 42.755 105.288 ;
     RECT  42.577 27.6 42.757 27.624 ;
     RECT  42.113 31.536 42.757 32.184 ;
     RECT  41.893 102 42.757 102.648 ;
     RECT  42.515 49.584 42.761 49.608 ;
     RECT  41.785 56.4 42.761 56.424 ;
     RECT  42.755 77.472 42.761 77.592 ;
     RECT  42.509 99.6 42.761 99.624 ;
     RECT  41.891 40.32 42.764 40.728 ;
     RECT  42.613 17.28 42.797 17.64 ;
     RECT  40.504 42.96 42.797 42.984 ;
     RECT  42.761 77.472 42.797 77.496 ;
     RECT  42.515 81.888 42.797 81.912 ;
     RECT  42.757 102 42.797 103.224 ;
     RECT  42.755 104.208 42.797 104.232 ;
     RECT  42.757 27.36 42.803 27.624 ;
     RECT  42.577 34.752 42.803 35.544 ;
     RECT  42.275 18.816 42.833 18.84 ;
     RECT  42.757 33.456 42.841 33.48 ;
     RECT  42.803 34.848 42.841 35.544 ;
     RECT  42.797 102.624 42.841 103.224 ;
     RECT  42.361 45.648 42.851 46.488 ;
     RECT  42.397 67.104 42.851 67.128 ;
     RECT  42.755 75.792 42.851 75.96 ;
     RECT  42.793 63.216 42.853 63.24 ;
     RECT  42.851 75.936 42.869 75.96 ;
     RECT  42.853 63.216 42.877 63.336 ;
     RECT  42.793 62.016 42.899 62.04 ;
     RECT  42.757 31.536 42.941 32.472 ;
     RECT  42.853 36.672 42.941 36.696 ;
     RECT  42.707 93.072 42.941 93.096 ;
     RECT  42.841 35.52 42.977 35.544 ;
     RECT  42.725 47.904 42.977 47.928 ;
     RECT  42.577 51.984 42.977 52.008 ;
     RECT  42.764 40.32 42.997 40.824 ;
     RECT  40.504 7.152 43.043 7.176 ;
     RECT  42.997 40.32 43.043 41.016 ;
     RECT  42.956 44.304 43.043 44.328 ;
     RECT  42.685 89.472 43.049 89.496 ;
     RECT  42.755 95.52 43.049 96.168 ;
     RECT  42.877 63.312 43.081 63.336 ;
     RECT  43.049 96.144 43.093 96.168 ;
     RECT  42.851 46.464 43.104 46.488 ;
     RECT  43.043 40.992 43.121 41.016 ;
     RECT  43.081 63.312 43.121 63.72 ;
     RECT  43.052 88.32 43.139 88.344 ;
     RECT  42.577 24.144 43.148 24.168 ;
     RECT  43.093 96.144 43.157 96.36 ;
     RECT  42.997 14.256 43.189 14.28 ;
     RECT  43.093 71.856 43.193 71.88 ;
     RECT  42.755 105.264 43.193 105.288 ;
     RECT  43.189 14.256 43.235 14.808 ;
     RECT  43.148 24.144 43.235 24.264 ;
     RECT  42.941 31.536 43.235 31.56 ;
     RECT  42.509 53.856 43.235 53.88 ;
     RECT  43.121 63.696 43.331 63.72 ;
     RECT  43.032 70.128 43.331 70.152 ;
     RECT  42.509 100.656 43.337 100.68 ;
     RECT  42.748 74.064 43.409 74.088 ;
     RECT  43.157 96.336 43.409 96.36 ;
     RECT  43.235 24.144 43.517 24.168 ;
     RECT  42.853 38.16 43.517 38.184 ;
     RECT  43.235 14.736 43.532 14.808 ;
     RECT  43.532 14.736 43.619 14.904 ;
     RECT  42.797 17.28 43.619 17.304 ;
     RECT  43.619 14.736 43.913 14.76 ;
     RECT  43.405 18.576 44.293 18.6 ;
     RECT  44.293 18.576 44.3 19.128 ;
     RECT  42.577 22.752 44.339 22.776 ;
     RECT  44.3 18.192 44.381 19.128 ;
     RECT  44.381 18.192 44.387 18.84 ;
     RECT  44.387 18.816 44.425 18.84 ;
     RECT  42.803 27.36 44.525 27.384 ;
     RECT  44.089 12.528 44.725 12.552 ;
     RECT  44.737 4.656 44.809 4.68 ;
     RECT  44.917 6.048 45.097 6.072 ;
     RECT  44.989 7.392 45.097 7.416 ;
     RECT  44.809 4.656 45.457 4.968 ;
     RECT  45.097 6.048 45.457 7.416 ;
     RECT  45.457 4.656 45.608 7.416 ;
     RECT  45.445 10.032 45.608 10.056 ;
     RECT  44.725 11.232 45.608 12.552 ;
     RECT  45.608 2.148 45.712 105.852 ;
     RECT  45.712 2.418 45.904 105.582 ;
     RECT  45.904 4.944 46.073 4.968 ;
     RECT  45.904 6.576 46.109 7.416 ;
     RECT  46.109 7.392 46.181 7.416 ;
     RECT  45.904 21.744 47.149 22.872 ;
     RECT  45.904 65.712 47.473 65.736 ;
     RECT  45.904 79.824 47.905 79.848 ;
     RECT  45.904 58.224 47.941 58.248 ;
     RECT  45.904 49.056 48.337 49.752 ;
     RECT  45.904 51.744 48.373 53.112 ;
     RECT  45.904 38.256 48.481 38.28 ;
     RECT  48.157 40.56 48.913 40.584 ;
     RECT  45.904 87.84 49.021 87.864 ;
     RECT  45.904 91.2 49.345 91.224 ;
     RECT  48.481 37.728 49.453 38.28 ;
     RECT  47.833 94.704 50.677 94.728 ;
     RECT  50.677 94.608 50.713 94.728 ;
     RECT  50.245 107.184 50.771 107.208 ;
     RECT  45.904 17.712 51.008 17.736 ;
     RECT  45.904 19.248 51.008 19.272 ;
     RECT  47.149 21.744 51.008 23.592 ;
     RECT  47.401 26.928 51.008 26.952 ;
     RECT  49.021 28.512 51.008 28.536 ;
     RECT  45.904 33.12 51.008 33.144 ;
     RECT  49.453 37.104 51.008 38.28 ;
     RECT  48.913 40.032 51.008 40.584 ;
     RECT  48.337 48.48 51.008 49.752 ;
     RECT  48.373 51.744 51.008 53.688 ;
     RECT  48.013 55.968 51.008 55.992 ;
     RECT  47.941 57.696 51.008 58.248 ;
     RECT  47.797 63.84 51.008 63.864 ;
     RECT  47.473 64.992 51.008 65.736 ;
     RECT  48.913 69.696 51.008 69.72 ;
     RECT  47.473 74.304 51.008 74.328 ;
     RECT  45.904 75.936 51.008 75.96 ;
     RECT  47.905 79.248 51.008 79.848 ;
     RECT  45.904 83.232 51.008 83.256 ;
     RECT  45.904 85.68 51.008 85.704 ;
     RECT  49.021 87.84 51.008 88.488 ;
     RECT  49.345 90.624 51.008 91.224 ;
     RECT  50.713 94.608 51.008 94.872 ;
     RECT  47.581 99.216 51.008 99.24 ;
     RECT  47.041 101.04 51.008 101.064 ;
     RECT  45.904 103.824 51.008 103.848 ;
     RECT  51.008 2.148 51.112 105.852 ;
     RECT  51.112 2.418 51.304 105.582 ;
     RECT  54.476 2.256 54.563 2.28 ;
     RECT  51.304 17.712 56.408 17.736 ;
     RECT  51.304 19.248 56.408 19.272 ;
     RECT  51.304 21.744 56.408 23.592 ;
     RECT  51.304 26.928 56.408 26.952 ;
     RECT  51.304 28.512 56.408 28.536 ;
     RECT  51.304 33.12 56.408 33.144 ;
     RECT  51.304 37.104 56.408 38.28 ;
     RECT  51.304 39.888 56.408 40.584 ;
     RECT  51.304 48.48 56.408 49.752 ;
     RECT  51.304 51.744 56.408 53.688 ;
     RECT  51.304 55.968 56.408 55.992 ;
     RECT  51.304 57.696 56.408 58.248 ;
     RECT  51.304 63.84 56.408 63.864 ;
     RECT  51.304 64.992 56.408 65.736 ;
     RECT  51.304 69.696 56.408 69.72 ;
     RECT  51.304 74.304 56.408 74.328 ;
     RECT  51.304 75.936 56.408 75.96 ;
     RECT  51.304 79.248 56.408 79.848 ;
     RECT  51.304 83.232 56.408 83.256 ;
     RECT  51.304 85.68 56.408 85.704 ;
     RECT  51.304 87.84 56.408 88.488 ;
     RECT  51.304 90.624 56.408 91.224 ;
     RECT  51.304 94.848 56.408 94.872 ;
     RECT  51.304 99.216 56.408 99.24 ;
     RECT  51.304 101.04 56.408 101.064 ;
     RECT  51.304 103.824 56.408 103.848 ;
     RECT  56.408 2.148 56.512 105.852 ;
     RECT  56.512 2.418 56.704 105.582 ;
     RECT  56.704 94.848 58.669 94.872 ;
     RECT  58.669 94.608 58.773 94.872 ;
     RECT  56.704 17.712 61.808 17.736 ;
     RECT  56.704 19.248 61.808 19.272 ;
     RECT  56.704 21.744 61.808 23.592 ;
     RECT  56.704 26.928 61.808 26.952 ;
     RECT  56.704 28.512 61.808 28.536 ;
     RECT  56.704 33.12 61.808 33.144 ;
     RECT  56.704 37.104 61.808 38.28 ;
     RECT  56.704 39.888 61.808 40.584 ;
     RECT  56.704 48.48 61.808 49.752 ;
     RECT  56.704 51.744 61.808 53.688 ;
     RECT  56.704 55.968 61.808 55.992 ;
     RECT  56.704 57.696 61.808 58.248 ;
     RECT  56.704 63.84 61.808 63.864 ;
     RECT  56.704 64.992 61.808 65.736 ;
     RECT  56.704 69.696 61.808 69.72 ;
     RECT  56.704 74.304 61.808 74.328 ;
     RECT  56.704 75.936 61.808 75.96 ;
     RECT  56.704 79.248 61.808 79.848 ;
     RECT  56.704 83.232 61.808 83.256 ;
     RECT  56.704 85.68 61.808 85.704 ;
     RECT  56.704 87.84 61.808 88.488 ;
     RECT  56.704 90.624 61.808 91.224 ;
     RECT  58.773 94.848 61.808 94.872 ;
     RECT  56.704 99.216 61.808 99.24 ;
     RECT  56.704 101.04 61.808 101.064 ;
     RECT  56.704 103.824 61.808 103.848 ;
     RECT  61.808 2.148 61.912 105.852 ;
     RECT  61.912 2.418 62.104 105.582 ;
     RECT  62.104 94.608 62.675 94.872 ;
     RECT  62.104 39.888 62.741 40.584 ;
     RECT  62.675 94.608 62.741 94.728 ;
     RECT  62.741 94.704 66.661 94.728 ;
     RECT  66.661 94.608 66.697 94.728 ;
     RECT  62.104 17.712 67.208 17.736 ;
     RECT  62.104 19.248 67.208 19.272 ;
     RECT  62.104 21.744 67.208 23.592 ;
     RECT  62.104 26.928 67.208 26.952 ;
     RECT  62.104 28.512 67.208 28.536 ;
     RECT  62.104 33.12 67.208 33.144 ;
     RECT  62.104 37.104 67.208 38.28 ;
     RECT  62.741 40.032 67.208 40.584 ;
     RECT  62.104 48.48 67.208 49.752 ;
     RECT  62.104 51.744 67.208 53.688 ;
     RECT  62.104 55.968 67.208 55.992 ;
     RECT  62.104 57.696 67.208 58.248 ;
     RECT  62.104 63.84 67.208 63.864 ;
     RECT  62.104 64.992 67.208 65.736 ;
     RECT  62.104 69.696 67.208 69.72 ;
     RECT  62.104 74.304 67.208 74.328 ;
     RECT  62.104 75.936 67.208 75.96 ;
     RECT  62.104 79.248 67.208 79.848 ;
     RECT  62.104 83.232 67.208 83.256 ;
     RECT  62.104 85.68 67.208 85.704 ;
     RECT  62.104 87.84 67.208 88.488 ;
     RECT  62.104 90.624 67.208 91.224 ;
     RECT  66.697 94.608 67.208 94.872 ;
     RECT  62.104 99.216 67.208 99.24 ;
     RECT  62.104 101.04 67.208 101.064 ;
     RECT  62.104 103.824 67.208 103.848 ;
     RECT  67.208 2.148 67.312 105.852 ;
     RECT  67.312 2.418 67.504 105.582 ;
     RECT  67.504 17.712 72.608 17.736 ;
     RECT  67.504 19.248 72.608 19.272 ;
     RECT  67.504 21.744 72.608 23.592 ;
     RECT  67.504 26.928 72.608 26.952 ;
     RECT  67.504 28.512 72.608 28.536 ;
     RECT  67.504 33.12 72.608 33.144 ;
     RECT  67.504 37.104 72.608 38.28 ;
     RECT  67.504 39.888 72.608 40.584 ;
     RECT  67.504 48.48 72.608 49.752 ;
     RECT  67.504 51.744 72.608 53.688 ;
     RECT  67.504 55.968 72.608 55.992 ;
     RECT  67.504 57.696 72.608 58.248 ;
     RECT  67.504 63.84 72.608 63.864 ;
     RECT  67.504 64.992 72.608 65.736 ;
     RECT  67.504 69.696 72.608 69.72 ;
     RECT  67.504 74.304 72.608 74.328 ;
     RECT  67.504 75.936 72.608 75.96 ;
     RECT  67.504 79.248 72.608 79.848 ;
     RECT  67.504 83.232 72.608 83.256 ;
     RECT  67.504 85.68 72.608 85.704 ;
     RECT  67.504 87.84 72.608 88.488 ;
     RECT  67.504 90.624 72.608 91.224 ;
     RECT  67.504 94.848 72.608 94.872 ;
     RECT  67.504 99.216 72.608 99.24 ;
     RECT  67.504 101.04 72.608 101.064 ;
     RECT  67.504 103.824 72.608 103.848 ;
     RECT  72.608 2.148 72.712 105.852 ;
     RECT  72.712 2.418 72.904 105.582 ;
     RECT  72.904 94.848 74.629 94.872 ;
     RECT  74.629 94.608 74.713 94.872 ;
     RECT  72.904 17.712 78.008 17.736 ;
     RECT  72.904 19.248 78.008 19.272 ;
     RECT  72.904 21.744 78.008 23.592 ;
     RECT  72.904 26.928 78.008 26.952 ;
     RECT  72.904 28.512 78.008 28.536 ;
     RECT  72.904 33.12 78.008 33.144 ;
     RECT  72.904 37.104 78.008 38.28 ;
     RECT  72.904 39.888 78.008 40.584 ;
     RECT  72.904 48.48 78.008 49.752 ;
     RECT  72.904 51.744 78.008 53.688 ;
     RECT  72.904 55.968 78.008 55.992 ;
     RECT  72.904 57.696 78.008 58.248 ;
     RECT  72.904 63.84 78.008 63.864 ;
     RECT  72.904 64.992 78.008 65.736 ;
     RECT  72.904 69.696 78.008 69.72 ;
     RECT  72.904 74.304 78.008 74.328 ;
     RECT  72.904 75.936 78.008 75.96 ;
     RECT  72.904 79.248 78.008 79.848 ;
     RECT  72.904 83.232 78.008 83.256 ;
     RECT  72.904 85.68 78.008 85.704 ;
     RECT  72.904 87.84 78.008 88.488 ;
     RECT  72.904 90.624 78.008 91.224 ;
     RECT  74.713 94.848 78.008 94.872 ;
     RECT  72.904 99.216 78.008 99.24 ;
     RECT  72.904 101.04 78.008 101.064 ;
     RECT  72.904 103.824 78.008 103.848 ;
     RECT  78.008 2.148 78.112 105.852 ;
     RECT  78.112 2.418 78.304 105.582 ;
     RECT  78.304 94.608 78.659 94.872 ;
     RECT  78.304 39.888 78.689 40.584 ;
     RECT  78.659 94.608 78.689 94.728 ;
     RECT  78.304 101.04 80.953 101.064 ;
     RECT  78.689 94.704 82.609 94.728 ;
     RECT  82.609 94.608 82.645 94.728 ;
     RECT  78.304 55.968 83.221 55.992 ;
     RECT  78.304 64.992 83.221 65.736 ;
     RECT  78.304 74.304 83.221 74.328 ;
     RECT  78.304 79.248 83.221 79.848 ;
     RECT  78.304 85.68 83.221 85.704 ;
     RECT  82.609 11.184 83.408 11.208 ;
     RECT  82.645 12.336 83.408 12.36 ;
     RECT  78.304 17.712 83.408 17.736 ;
     RECT  78.304 19.248 83.408 19.272 ;
     RECT  78.304 21.744 83.408 23.592 ;
     RECT  78.304 26.928 83.408 26.952 ;
     RECT  78.304 28.512 83.408 28.536 ;
     RECT  78.304 33.12 83.408 33.144 ;
     RECT  78.304 37.104 83.408 38.28 ;
     RECT  78.689 40.032 83.408 40.584 ;
     RECT  78.304 48.48 83.408 49.752 ;
     RECT  78.304 51.744 83.408 53.688 ;
     RECT  83.221 55.536 83.408 55.992 ;
     RECT  78.304 57.696 83.408 58.248 ;
     RECT  78.304 63.84 83.408 63.864 ;
     RECT  83.221 64.992 83.408 66.36 ;
     RECT  78.304 69.696 83.408 69.72 ;
     RECT  83.221 72.48 83.408 72.504 ;
     RECT  83.221 74.304 83.408 74.664 ;
     RECT  78.304 75.936 83.408 75.96 ;
     RECT  83.221 78.624 83.408 79.848 ;
     RECT  83.221 81.072 83.408 81.096 ;
     RECT  78.304 83.232 83.408 83.256 ;
     RECT  83.221 85.68 83.408 86.328 ;
     RECT  78.304 87.84 83.408 88.488 ;
     RECT  78.304 90.624 83.408 91.224 ;
     RECT  82.645 94.608 83.408 94.872 ;
     RECT  78.304 99.216 83.408 99.24 ;
     RECT  80.953 100.848 83.408 101.064 ;
     RECT  82.033 102.432 83.408 102.456 ;
     RECT  78.304 103.824 83.408 103.848 ;
     RECT  83.408 2.148 83.512 105.852 ;
     RECT  83.512 2.418 83.704 105.72 ;
     RECT  83.704 32.16 84.913 33.144 ;
     RECT  83.704 48.192 84.913 49.752 ;
     RECT  83.704 60.48 84.913 60.504 ;
     RECT  83.704 62.304 84.913 66.936 ;
     RECT  83.704 68.784 84.913 69.72 ;
     RECT  83.704 70.944 84.913 76.776 ;
     RECT  83.704 78.624 84.913 81.384 ;
     RECT  83.704 82.608 84.913 86.328 ;
     RECT  83.704 87.84 84.913 91.224 ;
     RECT  83.704 94.848 84.913 94.872 ;
     RECT  83.704 96.144 84.913 96.792 ;
     RECT  83.704 103.824 85.453 104.472 ;
     RECT  83.704 105.696 85.453 105.72 ;
     RECT  83.704 17.712 85.489 17.736 ;
     RECT  83.704 18.96 85.489 20.232 ;
     RECT  83.704 21.744 85.489 23.592 ;
     RECT  83.704 26.64 85.489 27 ;
     RECT  83.704 28.512 85.489 28.536 ;
     RECT  83.704 30.624 85.489 30.648 ;
     RECT  84.913 32.16 85.489 33.72 ;
     RECT  83.704 34.944 85.489 34.968 ;
     RECT  83.704 37.104 85.489 38.28 ;
     RECT  83.704 40.032 85.489 40.584 ;
     RECT  83.704 42.336 85.489 42.984 ;
     RECT  83.704 45.408 85.489 46.344 ;
     RECT  84.913 47.856 85.489 49.752 ;
     RECT  83.704 50.928 85.489 54.36 ;
     RECT  83.704 55.536 85.489 55.992 ;
     RECT  83.704 57.696 85.489 58.968 ;
     RECT  84.913 60.48 85.489 66.936 ;
     RECT  84.913 68.784 85.489 76.776 ;
     RECT  84.913 78.624 85.489 86.328 ;
     RECT  84.913 87.552 85.489 91.224 ;
     RECT  83.704 92.736 85.489 93.384 ;
     RECT  84.913 94.848 85.489 97.08 ;
     RECT  83.704 98.304 85.489 99.24 ;
     RECT  83.704 100.848 85.489 101.064 ;
     RECT  83.704 102.432 85.489 102.456 ;
     RECT  85.453 103.824 85.489 105.72 ;
     RECT  83.704 10.272 86.281 11.208 ;
     RECT  86.281 10.272 86.316 10.296 ;
     RECT  86.281 10.296 86.321 11.328 ;
     RECT  86.281 11.328 86.316 11.352 ;
     RECT  85.489 17.424 86.316 17.448 ;
     RECT  85.489 17.448 86.364 17.712 ;
     RECT  85.489 17.712 86.316 17.736 ;
     RECT  85.489 17.736 86.364 18.048 ;
     RECT  85.489 18.048 86.316 18.072 ;
     RECT  85.489 18.072 86.364 18.336 ;
     RECT  85.489 18.336 86.316 18.36 ;
     RECT  85.489 18.36 86.364 18.672 ;
     RECT  85.489 18.672 86.316 18.696 ;
     RECT  85.489 18.696 86.364 18.96 ;
     RECT  85.489 18.96 86.316 18.984 ;
     RECT  85.489 18.984 86.364 19.248 ;
     RECT  85.489 19.248 86.316 19.272 ;
     RECT  85.489 19.272 86.364 19.584 ;
     RECT  85.489 19.584 86.316 19.608 ;
     RECT  85.489 19.608 86.364 19.872 ;
     RECT  85.489 19.872 86.316 19.896 ;
     RECT  85.489 19.896 86.364 20.208 ;
     RECT  85.489 20.208 86.316 20.232 ;
     RECT  85.489 20.232 86.364 20.496 ;
     RECT  85.489 20.496 86.316 20.52 ;
     RECT  85.489 20.52 86.364 20.784 ;
     RECT  85.489 20.784 86.316 20.808 ;
     RECT  85.489 20.808 86.364 21.12 ;
     RECT  85.489 21.12 86.316 21.144 ;
     RECT  85.489 21.144 86.364 21.408 ;
     RECT  85.489 21.408 86.316 21.432 ;
     RECT  85.489 21.432 86.364 21.744 ;
     RECT  85.489 21.744 86.316 21.768 ;
     RECT  85.489 21.768 86.364 22.032 ;
     RECT  85.489 22.032 86.316 22.056 ;
     RECT  85.489 22.056 86.364 22.32 ;
     RECT  85.489 22.32 86.316 22.344 ;
     RECT  85.489 22.344 86.364 22.656 ;
     RECT  85.489 22.656 86.316 22.68 ;
     RECT  85.489 22.68 86.364 22.944 ;
     RECT  85.489 22.944 86.316 22.968 ;
     RECT  85.489 22.968 86.364 23.28 ;
     RECT  85.489 23.28 86.316 23.304 ;
     RECT  85.489 23.304 86.364 23.568 ;
     RECT  85.489 23.568 86.316 23.592 ;
     RECT  85.489 23.592 86.364 23.856 ;
     RECT  85.489 23.856 86.316 23.88 ;
     RECT  85.489 23.88 86.364 24.192 ;
     RECT  85.489 24.192 86.316 24.216 ;
     RECT  85.489 24.216 86.364 24.48 ;
     RECT  85.489 24.48 86.316 24.504 ;
     RECT  85.489 24.504 86.364 24.816 ;
     RECT  85.489 24.816 86.316 24.84 ;
     RECT  85.489 24.84 86.364 25.104 ;
     RECT  85.489 25.104 86.316 25.128 ;
     RECT  85.489 25.128 86.364 25.44 ;
     RECT  85.489 25.44 86.316 25.464 ;
     RECT  85.489 25.464 86.364 25.728 ;
     RECT  85.489 25.728 86.316 25.752 ;
     RECT  85.489 25.752 86.364 26.016 ;
     RECT  85.489 26.016 86.316 26.04 ;
     RECT  85.489 26.04 86.364 26.352 ;
     RECT  85.489 26.352 86.316 26.376 ;
     RECT  85.489 26.376 86.364 26.64 ;
     RECT  85.489 26.64 86.316 26.664 ;
     RECT  85.489 26.664 86.364 26.976 ;
     RECT  85.489 26.976 86.316 27 ;
     RECT  85.489 27 86.364 27.264 ;
     RECT  85.489 27.264 86.316 27.288 ;
     RECT  85.489 27.288 86.364 27.552 ;
     RECT  85.489 27.552 86.316 27.576 ;
     RECT  85.489 27.576 86.364 27.888 ;
     RECT  85.489 27.888 86.316 27.912 ;
     RECT  85.489 27.912 86.364 28.176 ;
     RECT  85.489 28.176 86.316 28.2 ;
     RECT  85.489 28.2 86.364 28.512 ;
     RECT  85.489 28.512 86.316 28.536 ;
     RECT  85.489 28.536 86.364 28.8 ;
     RECT  85.489 28.8 86.316 28.824 ;
     RECT  85.489 28.824 86.364 29.088 ;
     RECT  85.489 29.088 86.316 29.112 ;
     RECT  85.489 29.112 86.364 29.424 ;
     RECT  85.489 29.424 86.316 29.448 ;
     RECT  85.489 29.448 86.364 29.712 ;
     RECT  85.489 29.712 86.316 29.736 ;
     RECT  85.489 29.736 86.364 30.048 ;
     RECT  85.489 30.048 86.316 30.072 ;
     RECT  85.489 30.072 86.364 30.336 ;
     RECT  85.489 30.336 86.316 30.36 ;
     RECT  85.489 30.36 86.364 30.624 ;
     RECT  85.489 30.624 86.316 30.648 ;
     RECT  85.489 30.648 86.364 30.96 ;
     RECT  85.489 30.96 86.316 30.984 ;
     RECT  85.489 30.984 86.364 31.248 ;
     RECT  85.489 31.248 86.316 31.272 ;
     RECT  85.489 31.272 86.364 31.584 ;
     RECT  85.489 31.584 86.316 31.608 ;
     RECT  85.489 31.608 86.364 31.872 ;
     RECT  85.489 31.872 86.316 31.896 ;
     RECT  85.489 31.896 86.364 32.16 ;
     RECT  85.489 32.16 86.316 32.184 ;
     RECT  85.489 32.184 86.364 32.496 ;
     RECT  85.489 32.496 86.316 32.52 ;
     RECT  85.489 32.52 86.364 32.784 ;
     RECT  85.489 32.784 86.316 32.808 ;
     RECT  85.489 32.808 86.364 33.12 ;
     RECT  85.489 33.12 86.316 33.144 ;
     RECT  85.489 33.144 86.364 33.408 ;
     RECT  85.489 33.408 86.316 33.432 ;
     RECT  85.489 33.432 86.364 33.696 ;
     RECT  85.489 33.696 86.316 33.72 ;
     RECT  85.489 33.72 86.364 34.032 ;
     RECT  85.489 34.032 86.316 34.056 ;
     RECT  85.489 34.056 86.364 34.32 ;
     RECT  85.489 34.32 86.316 34.344 ;
     RECT  85.489 34.344 86.364 34.656 ;
     RECT  85.489 34.656 86.316 34.68 ;
     RECT  85.489 34.68 86.364 34.944 ;
     RECT  85.489 34.944 86.316 34.968 ;
     RECT  85.489 34.968 86.364 35.28 ;
     RECT  85.489 35.28 86.316 35.304 ;
     RECT  85.489 35.304 86.364 35.568 ;
     RECT  85.489 35.568 86.316 35.592 ;
     RECT  85.489 35.592 86.364 35.856 ;
     RECT  85.489 35.856 86.316 35.88 ;
     RECT  85.489 35.88 86.364 36.192 ;
     RECT  85.489 36.192 86.316 36.216 ;
     RECT  85.489 36.216 86.364 36.48 ;
     RECT  85.489 36.48 86.316 36.504 ;
     RECT  85.489 36.504 86.364 36.816 ;
     RECT  85.489 36.816 86.316 36.84 ;
     RECT  85.489 36.84 86.364 37.104 ;
     RECT  85.489 37.104 86.316 37.128 ;
     RECT  85.489 37.128 86.364 37.392 ;
     RECT  85.489 37.392 86.316 37.416 ;
     RECT  85.489 37.416 86.364 37.728 ;
     RECT  85.489 37.728 86.316 37.752 ;
     RECT  85.489 37.752 86.364 38.016 ;
     RECT  85.489 38.016 86.316 38.04 ;
     RECT  85.489 38.04 86.364 38.352 ;
     RECT  85.489 38.352 86.316 38.376 ;
     RECT  85.489 38.376 86.364 38.64 ;
     RECT  85.489 38.64 86.316 38.664 ;
     RECT  85.489 38.664 86.364 38.928 ;
     RECT  85.489 38.928 86.316 38.952 ;
     RECT  85.489 38.952 86.364 39.264 ;
     RECT  85.489 39.264 86.316 39.288 ;
     RECT  85.489 39.288 86.364 39.552 ;
     RECT  85.489 39.552 86.316 39.576 ;
     RECT  85.489 39.576 86.364 39.888 ;
     RECT  85.489 39.888 86.316 39.912 ;
     RECT  85.489 39.912 86.364 40.176 ;
     RECT  85.489 40.176 86.316 40.2 ;
     RECT  85.489 40.2 86.364 40.464 ;
     RECT  85.489 40.464 86.316 40.488 ;
     RECT  85.489 40.488 86.364 40.8 ;
     RECT  85.489 40.8 86.316 40.824 ;
     RECT  85.489 40.824 86.364 41.088 ;
     RECT  85.489 41.088 86.316 41.112 ;
     RECT  85.489 41.112 86.364 41.424 ;
     RECT  85.489 41.424 86.316 41.448 ;
     RECT  85.489 41.448 86.364 41.712 ;
     RECT  85.489 41.712 86.316 41.736 ;
     RECT  85.489 41.736 86.364 42 ;
     RECT  85.489 42 86.316 42.024 ;
     RECT  85.489 42.024 86.364 42.336 ;
     RECT  85.489 42.336 86.316 42.36 ;
     RECT  85.489 42.36 86.364 42.624 ;
     RECT  85.489 42.624 86.316 42.648 ;
     RECT  85.489 42.648 86.364 42.96 ;
     RECT  85.489 42.96 86.316 42.984 ;
     RECT  85.489 42.984 86.364 43.248 ;
     RECT  85.489 43.248 86.316 43.272 ;
     RECT  85.489 43.272 86.364 43.536 ;
     RECT  85.489 43.536 86.316 43.56 ;
     RECT  85.489 43.56 86.364 43.872 ;
     RECT  85.489 43.872 86.316 43.896 ;
     RECT  85.489 43.896 86.364 44.16 ;
     RECT  85.489 44.16 86.316 44.184 ;
     RECT  85.489 44.184 86.364 44.496 ;
     RECT  85.489 44.496 86.316 44.52 ;
     RECT  85.489 44.52 86.364 44.784 ;
     RECT  85.489 44.784 86.316 44.808 ;
     RECT  85.489 44.808 86.364 45.12 ;
     RECT  85.489 45.12 86.316 45.144 ;
     RECT  85.489 45.144 86.364 45.408 ;
     RECT  85.489 45.408 86.316 45.432 ;
     RECT  85.489 45.432 86.364 45.696 ;
     RECT  85.489 45.696 86.316 45.72 ;
     RECT  85.489 45.72 86.364 46.032 ;
     RECT  85.489 46.032 86.316 46.056 ;
     RECT  85.489 46.056 86.364 46.32 ;
     RECT  85.489 46.32 86.316 46.344 ;
     RECT  85.489 46.344 86.364 46.656 ;
     RECT  85.489 46.656 86.316 46.68 ;
     RECT  85.489 46.68 86.364 46.944 ;
     RECT  85.489 46.944 86.316 46.968 ;
     RECT  85.489 46.968 86.364 47.232 ;
     RECT  85.489 47.232 86.316 47.256 ;
     RECT  85.489 47.256 86.364 47.568 ;
     RECT  85.489 47.568 86.316 47.592 ;
     RECT  85.489 47.592 86.364 47.856 ;
     RECT  85.489 47.856 86.316 47.88 ;
     RECT  85.489 47.88 86.364 48.192 ;
     RECT  85.489 48.192 86.316 48.216 ;
     RECT  85.489 48.216 86.364 48.48 ;
     RECT  85.489 48.48 86.316 48.504 ;
     RECT  85.489 48.504 86.364 48.768 ;
     RECT  85.489 48.768 86.316 48.792 ;
     RECT  85.489 48.792 86.364 49.104 ;
     RECT  85.489 49.104 86.316 49.128 ;
     RECT  85.489 49.128 86.364 49.392 ;
     RECT  85.489 49.392 86.316 49.416 ;
     RECT  85.489 49.416 86.364 49.728 ;
     RECT  85.489 49.728 86.316 49.752 ;
     RECT  85.489 49.752 86.364 50.016 ;
     RECT  85.489 50.016 86.316 50.04 ;
     RECT  85.489 50.04 86.364 50.304 ;
     RECT  85.489 50.304 86.316 50.328 ;
     RECT  85.489 50.328 86.364 50.64 ;
     RECT  85.489 50.64 86.316 50.664 ;
     RECT  85.489 50.664 86.364 50.928 ;
     RECT  85.489 50.928 86.316 50.952 ;
     RECT  85.489 50.952 86.364 51.264 ;
     RECT  85.489 51.264 86.316 51.288 ;
     RECT  85.489 51.288 86.364 51.552 ;
     RECT  85.489 51.552 86.316 51.576 ;
     RECT  85.489 51.576 86.364 51.84 ;
     RECT  85.489 51.84 86.316 51.864 ;
     RECT  85.489 51.864 86.364 52.176 ;
     RECT  85.489 52.176 86.316 52.2 ;
     RECT  85.489 52.2 86.364 52.464 ;
     RECT  85.489 52.464 86.316 52.488 ;
     RECT  85.489 52.488 86.364 52.8 ;
     RECT  85.489 52.8 86.316 52.824 ;
     RECT  85.489 52.824 86.364 53.088 ;
     RECT  85.489 53.088 86.316 53.112 ;
     RECT  85.489 53.112 86.364 53.376 ;
     RECT  85.489 53.376 86.316 53.4 ;
     RECT  85.489 53.4 86.364 53.712 ;
     RECT  85.489 53.712 86.316 53.736 ;
     RECT  85.489 53.736 86.364 54 ;
     RECT  85.489 54 86.316 54.024 ;
     RECT  85.489 54.024 86.364 54.336 ;
     RECT  85.489 54.336 86.316 54.36 ;
     RECT  85.489 54.36 86.364 54.624 ;
     RECT  85.489 54.624 86.316 54.648 ;
     RECT  85.489 54.648 86.364 54.96 ;
     RECT  85.489 54.96 86.316 54.984 ;
     RECT  85.489 54.984 86.364 55.248 ;
     RECT  85.489 55.248 86.316 55.272 ;
     RECT  85.489 55.272 86.364 55.536 ;
     RECT  85.489 55.536 86.316 55.56 ;
     RECT  85.489 55.56 86.364 55.872 ;
     RECT  85.489 55.872 86.316 55.896 ;
     RECT  85.489 55.896 86.364 56.16 ;
     RECT  85.489 56.16 86.316 56.184 ;
     RECT  85.489 56.184 86.364 56.496 ;
     RECT  85.489 56.496 86.316 56.52 ;
     RECT  85.489 56.52 86.364 56.784 ;
     RECT  85.489 56.784 86.316 56.808 ;
     RECT  85.489 56.808 86.364 57.072 ;
     RECT  85.489 57.072 86.316 57.096 ;
     RECT  85.489 57.096 86.364 57.408 ;
     RECT  85.489 57.408 86.316 57.432 ;
     RECT  85.489 57.432 86.364 57.696 ;
     RECT  85.489 57.696 86.316 57.72 ;
     RECT  85.489 57.72 86.364 58.032 ;
     RECT  85.489 58.032 86.316 58.056 ;
     RECT  85.489 58.056 86.364 58.32 ;
     RECT  85.489 58.32 86.316 58.344 ;
     RECT  85.489 58.344 86.364 58.608 ;
     RECT  85.489 58.608 86.316 58.632 ;
     RECT  85.489 58.632 86.364 58.944 ;
     RECT  85.489 58.944 86.316 58.968 ;
     RECT  85.489 58.968 86.364 59.232 ;
     RECT  85.489 59.232 86.316 59.256 ;
     RECT  85.489 59.256 86.364 59.568 ;
     RECT  85.489 59.568 86.316 59.592 ;
     RECT  85.489 59.592 86.364 59.856 ;
     RECT  85.489 59.856 86.316 59.88 ;
     RECT  85.489 59.88 86.364 60.144 ;
     RECT  85.489 60.144 86.316 60.168 ;
     RECT  85.489 60.168 86.364 60.48 ;
     RECT  85.489 60.48 86.316 60.504 ;
     RECT  85.489 60.504 86.364 60.768 ;
     RECT  85.489 60.768 86.316 60.792 ;
     RECT  85.489 60.792 86.364 61.104 ;
     RECT  85.489 61.104 86.316 61.128 ;
     RECT  85.489 61.128 86.364 61.392 ;
     RECT  85.489 61.392 86.316 61.416 ;
     RECT  85.489 61.416 86.364 61.68 ;
     RECT  85.489 61.68 86.316 61.704 ;
     RECT  85.489 61.704 86.364 62.016 ;
     RECT  85.489 62.016 86.316 62.04 ;
     RECT  85.489 62.04 86.364 62.304 ;
     RECT  85.489 62.304 86.316 62.328 ;
     RECT  85.489 62.328 86.364 62.64 ;
     RECT  85.489 62.64 86.316 62.664 ;
     RECT  85.489 62.664 86.364 62.928 ;
     RECT  85.489 62.928 86.316 62.952 ;
     RECT  85.489 62.952 86.364 63.216 ;
     RECT  85.489 63.216 86.316 63.24 ;
     RECT  85.489 63.24 86.364 63.552 ;
     RECT  85.489 63.552 86.316 63.576 ;
     RECT  85.489 63.576 86.364 63.84 ;
     RECT  85.489 63.84 86.316 63.864 ;
     RECT  85.489 63.864 86.364 64.176 ;
     RECT  85.489 64.176 86.316 64.2 ;
     RECT  85.489 64.2 86.364 64.464 ;
     RECT  85.489 64.464 86.316 64.488 ;
     RECT  85.489 64.488 86.364 64.8 ;
     RECT  85.489 64.8 86.316 64.824 ;
     RECT  85.489 64.824 86.364 65.088 ;
     RECT  85.489 65.088 86.316 65.112 ;
     RECT  85.489 65.112 86.364 65.376 ;
     RECT  85.489 65.376 86.316 65.4 ;
     RECT  85.489 65.4 86.364 65.712 ;
     RECT  85.489 65.712 86.316 65.736 ;
     RECT  85.489 65.736 86.364 66 ;
     RECT  85.489 66 86.316 66.024 ;
     RECT  85.489 66.024 86.364 66.336 ;
     RECT  85.489 66.336 86.316 66.36 ;
     RECT  85.489 66.36 86.364 66.624 ;
     RECT  85.489 66.624 86.316 66.648 ;
     RECT  85.489 66.648 86.364 66.912 ;
     RECT  85.489 66.912 86.316 66.936 ;
     RECT  85.489 66.936 86.364 67.248 ;
     RECT  85.489 67.248 86.316 67.272 ;
     RECT  85.489 67.272 86.364 67.536 ;
     RECT  85.489 67.536 86.316 67.56 ;
     RECT  85.489 67.56 86.364 67.872 ;
     RECT  85.489 67.872 86.316 67.896 ;
     RECT  85.489 67.896 86.364 68.16 ;
     RECT  85.489 68.16 86.316 68.184 ;
     RECT  85.489 68.184 86.364 68.448 ;
     RECT  85.489 68.448 86.316 68.472 ;
     RECT  85.489 68.472 86.364 68.784 ;
     RECT  85.489 68.784 86.316 68.808 ;
     RECT  85.489 68.808 86.364 69.072 ;
     RECT  85.489 69.072 86.316 69.096 ;
     RECT  85.489 69.096 86.364 69.408 ;
     RECT  85.489 69.408 86.316 69.432 ;
     RECT  85.489 69.432 86.364 69.696 ;
     RECT  85.489 69.696 86.316 69.72 ;
     RECT  85.489 69.72 86.364 69.984 ;
     RECT  85.489 69.984 86.316 70.008 ;
     RECT  85.489 70.008 86.364 70.32 ;
     RECT  85.489 70.32 86.316 70.344 ;
     RECT  85.489 70.344 86.364 70.608 ;
     RECT  85.489 70.608 86.316 70.632 ;
     RECT  85.489 70.632 86.364 70.944 ;
     RECT  85.489 70.944 86.316 70.968 ;
     RECT  85.489 70.968 86.364 71.232 ;
     RECT  85.489 71.232 86.316 71.256 ;
     RECT  85.489 71.256 86.364 71.52 ;
     RECT  85.489 71.52 86.316 71.544 ;
     RECT  85.489 71.544 86.364 71.856 ;
     RECT  85.489 71.856 86.316 71.88 ;
     RECT  85.489 71.88 86.364 72.144 ;
     RECT  85.489 72.144 86.316 72.168 ;
     RECT  85.489 72.168 86.364 72.48 ;
     RECT  85.489 72.48 86.316 72.504 ;
     RECT  85.489 72.504 86.364 72.768 ;
     RECT  85.489 72.768 86.316 72.792 ;
     RECT  85.489 72.792 86.364 73.056 ;
     RECT  85.489 73.056 86.316 73.08 ;
     RECT  85.489 73.08 86.364 73.392 ;
     RECT  85.489 73.392 86.316 73.416 ;
     RECT  85.489 73.416 86.364 73.68 ;
     RECT  85.489 73.68 86.316 73.704 ;
     RECT  85.489 73.704 86.364 74.016 ;
     RECT  85.489 74.016 86.316 74.04 ;
     RECT  85.489 74.04 86.364 74.304 ;
     RECT  85.489 74.304 86.316 74.328 ;
     RECT  85.489 74.328 86.364 74.64 ;
     RECT  85.489 74.64 86.316 74.664 ;
     RECT  85.489 74.664 86.364 74.928 ;
     RECT  85.489 74.928 86.316 74.952 ;
     RECT  85.489 74.952 86.364 75.216 ;
     RECT  85.489 75.216 86.316 75.24 ;
     RECT  85.489 75.24 86.364 75.552 ;
     RECT  85.489 75.552 86.316 75.576 ;
     RECT  85.489 75.576 86.364 75.84 ;
     RECT  85.489 75.84 86.316 75.864 ;
     RECT  85.489 75.864 86.364 76.176 ;
     RECT  85.489 76.176 86.316 76.2 ;
     RECT  85.489 76.2 86.364 76.464 ;
     RECT  85.489 76.464 86.316 76.488 ;
     RECT  85.489 76.488 86.364 76.752 ;
     RECT  85.489 76.752 86.316 76.776 ;
     RECT  85.489 76.776 86.364 77.088 ;
     RECT  85.489 77.088 86.316 77.112 ;
     RECT  85.489 77.112 86.364 77.376 ;
     RECT  85.489 77.376 86.316 77.4 ;
     RECT  85.489 77.4 86.364 77.712 ;
     RECT  85.489 77.712 86.316 77.736 ;
     RECT  85.489 77.736 86.364 78 ;
     RECT  85.489 78 86.316 78.024 ;
     RECT  85.489 78.024 86.364 78.288 ;
     RECT  85.489 78.288 86.316 78.312 ;
     RECT  85.489 78.312 86.364 78.624 ;
     RECT  85.489 78.624 86.316 78.648 ;
     RECT  85.489 78.648 86.364 78.912 ;
     RECT  85.489 78.912 86.316 78.936 ;
     RECT  85.489 78.936 86.364 79.248 ;
     RECT  85.489 79.248 86.316 79.272 ;
     RECT  85.489 79.272 86.364 79.536 ;
     RECT  85.489 79.536 86.316 79.56 ;
     RECT  85.489 79.56 86.364 79.824 ;
     RECT  85.489 79.824 86.316 79.848 ;
     RECT  85.489 79.848 86.364 80.16 ;
     RECT  85.489 80.16 86.316 80.184 ;
     RECT  85.489 80.184 86.364 80.448 ;
     RECT  85.489 80.448 86.316 80.472 ;
     RECT  85.489 80.472 86.364 80.784 ;
     RECT  85.489 80.784 86.316 80.808 ;
     RECT  85.489 80.808 86.364 81.072 ;
     RECT  85.489 81.072 86.316 81.096 ;
     RECT  85.489 81.096 86.364 81.36 ;
     RECT  85.489 81.36 86.316 81.384 ;
     RECT  85.489 81.384 86.364 81.696 ;
     RECT  85.489 81.696 86.316 81.72 ;
     RECT  85.489 81.72 86.364 81.984 ;
     RECT  85.489 81.984 86.316 82.008 ;
     RECT  85.489 82.008 86.364 82.32 ;
     RECT  85.489 82.32 86.316 82.344 ;
     RECT  85.489 82.344 86.364 82.608 ;
     RECT  85.489 82.608 86.316 82.632 ;
     RECT  85.489 82.632 86.364 82.896 ;
     RECT  85.489 82.896 86.316 82.92 ;
     RECT  85.489 82.92 86.364 83.232 ;
     RECT  85.489 83.232 86.316 83.256 ;
     RECT  85.489 83.256 86.364 83.52 ;
     RECT  85.489 83.52 86.316 83.544 ;
     RECT  85.489 83.544 86.364 83.856 ;
     RECT  85.489 83.856 86.316 83.88 ;
     RECT  85.489 83.88 86.364 84.144 ;
     RECT  85.489 84.144 86.316 84.168 ;
     RECT  85.489 84.168 86.364 84.48 ;
     RECT  85.489 84.48 86.316 84.504 ;
     RECT  85.489 84.504 86.364 84.768 ;
     RECT  85.489 84.768 86.316 84.792 ;
     RECT  85.489 84.792 86.364 85.056 ;
     RECT  85.489 85.056 86.316 85.08 ;
     RECT  85.489 85.08 86.364 85.392 ;
     RECT  85.489 85.392 86.316 85.416 ;
     RECT  85.489 85.416 86.364 85.68 ;
     RECT  85.489 85.68 86.316 85.704 ;
     RECT  85.489 85.704 86.364 86.016 ;
     RECT  85.489 86.016 86.316 86.04 ;
     RECT  85.489 86.04 86.364 86.304 ;
     RECT  85.489 86.304 86.316 86.328 ;
     RECT  85.489 86.328 86.364 86.592 ;
     RECT  85.489 86.592 86.316 86.616 ;
     RECT  85.489 86.616 86.364 86.928 ;
     RECT  85.489 86.928 86.316 86.952 ;
     RECT  85.489 86.952 86.364 87.216 ;
     RECT  85.489 87.216 86.316 87.24 ;
     RECT  85.489 87.24 86.364 87.552 ;
     RECT  85.489 87.552 86.316 87.576 ;
     RECT  85.489 87.576 86.364 87.84 ;
     RECT  85.489 87.84 86.316 87.864 ;
     RECT  85.489 87.864 86.364 88.128 ;
     RECT  85.489 88.128 86.316 88.152 ;
     RECT  85.489 88.152 86.364 88.464 ;
     RECT  85.489 88.464 86.316 88.488 ;
     RECT  85.489 88.488 86.364 88.752 ;
     RECT  85.489 88.752 86.316 88.776 ;
     RECT  85.489 88.776 86.364 89.088 ;
     RECT  85.489 89.088 86.316 89.112 ;
     RECT  85.489 89.112 86.364 89.376 ;
     RECT  85.489 89.376 86.316 89.4 ;
     RECT  85.489 89.4 86.364 89.664 ;
     RECT  85.489 89.664 86.316 89.688 ;
     RECT  85.489 89.688 86.364 90 ;
     RECT  85.489 90 86.316 90.024 ;
     RECT  85.489 90.024 86.364 90.288 ;
     RECT  85.489 90.288 86.316 90.312 ;
     RECT  85.489 90.312 86.364 90.624 ;
     RECT  85.489 90.624 86.316 90.648 ;
     RECT  85.489 90.648 86.364 90.912 ;
     RECT  85.489 90.912 86.316 90.936 ;
     RECT  85.489 90.936 86.364 91.2 ;
     RECT  85.489 91.2 86.316 91.224 ;
     RECT  85.489 91.224 86.364 91.536 ;
     RECT  85.489 91.536 86.316 91.56 ;
     RECT  85.489 91.56 86.364 91.824 ;
     RECT  85.489 91.824 86.316 91.848 ;
     RECT  85.489 91.848 86.364 92.16 ;
     RECT  85.489 92.16 86.316 92.184 ;
     RECT  85.489 92.184 86.364 92.448 ;
     RECT  85.489 92.448 86.316 92.472 ;
     RECT  85.489 92.472 86.364 92.736 ;
     RECT  85.489 92.736 86.316 92.76 ;
     RECT  85.489 92.76 86.364 93.072 ;
     RECT  85.489 93.072 86.316 93.096 ;
     RECT  85.489 93.096 86.364 93.36 ;
     RECT  85.489 93.36 86.316 93.384 ;
     RECT  85.489 93.384 86.364 93.696 ;
     RECT  85.489 93.696 86.316 93.72 ;
     RECT  85.489 93.72 86.364 93.984 ;
     RECT  85.489 93.984 86.316 94.008 ;
     RECT  85.489 94.008 86.364 94.32 ;
     RECT  85.489 94.32 86.316 94.344 ;
     RECT  85.489 94.344 86.364 94.608 ;
     RECT  85.489 94.608 86.316 94.632 ;
     RECT  85.489 94.632 86.364 94.896 ;
     RECT  85.489 94.896 86.316 94.92 ;
     RECT  85.489 94.92 86.364 95.232 ;
     RECT  85.489 95.232 86.316 95.256 ;
     RECT  85.489 95.256 86.364 95.52 ;
     RECT  85.489 95.52 86.316 95.544 ;
     RECT  85.489 95.544 86.364 95.856 ;
     RECT  85.489 95.856 86.316 95.88 ;
     RECT  85.489 95.88 86.364 96.144 ;
     RECT  85.489 96.144 86.316 96.168 ;
     RECT  85.489 96.168 86.364 96.432 ;
     RECT  85.489 96.432 86.316 96.456 ;
     RECT  85.489 96.456 86.364 96.768 ;
     RECT  85.489 96.768 86.316 96.792 ;
     RECT  85.489 96.792 86.364 97.056 ;
     RECT  85.489 97.056 86.316 97.08 ;
     RECT  85.489 97.08 86.364 97.392 ;
     RECT  85.489 97.392 86.316 97.416 ;
     RECT  85.489 97.416 86.364 97.68 ;
     RECT  85.489 97.68 86.316 97.704 ;
     RECT  85.489 97.704 86.364 97.968 ;
     RECT  85.489 97.968 86.316 97.992 ;
     RECT  85.489 97.992 86.364 98.304 ;
     RECT  85.489 98.304 86.316 98.328 ;
     RECT  85.489 98.328 86.364 98.592 ;
     RECT  85.489 98.592 86.316 98.616 ;
     RECT  85.489 98.616 86.364 98.928 ;
     RECT  85.489 98.928 86.316 98.952 ;
     RECT  85.489 98.952 86.364 99.216 ;
     RECT  85.489 99.216 86.316 99.24 ;
     RECT  85.489 99.24 86.364 99.504 ;
     RECT  85.489 99.504 86.316 99.528 ;
     RECT  85.489 99.528 86.364 99.84 ;
     RECT  85.489 99.84 86.316 99.864 ;
     RECT  85.489 99.864 86.364 100.128 ;
     RECT  85.489 100.128 86.316 100.152 ;
     RECT  85.489 100.152 86.364 100.464 ;
     RECT  85.489 100.464 86.316 100.488 ;
     RECT  85.489 100.488 86.364 100.752 ;
     RECT  85.489 100.752 86.316 100.776 ;
     RECT  85.489 100.776 86.364 101.04 ;
     RECT  85.489 101.04 86.316 101.064 ;
     RECT  85.489 101.064 86.364 101.376 ;
     RECT  85.489 101.376 86.316 101.4 ;
     RECT  85.489 101.4 86.364 101.664 ;
     RECT  85.489 101.664 86.316 101.688 ;
     RECT  85.489 101.688 86.364 102 ;
     RECT  85.489 102 86.316 102.024 ;
     RECT  85.489 102.024 86.364 102.288 ;
     RECT  85.489 102.288 86.316 102.312 ;
     RECT  85.489 102.312 86.364 102.576 ;
     RECT  85.489 102.576 86.316 102.6 ;
     RECT  85.489 102.6 86.364 102.912 ;
     RECT  85.489 102.912 86.316 102.936 ;
     RECT  85.489 102.936 86.364 103.2 ;
     RECT  85.489 103.2 86.316 103.224 ;
     RECT  85.489 103.224 86.364 103.536 ;
     RECT  85.489 103.536 86.316 103.56 ;
     RECT  85.489 103.56 86.364 103.824 ;
     RECT  85.489 103.824 86.316 103.848 ;
     RECT  85.489 103.848 86.364 104.16 ;
     RECT  85.489 104.16 86.316 104.184 ;
     RECT  85.489 104.184 86.364 104.448 ;
     RECT  85.489 104.448 86.316 104.472 ;
     RECT  85.489 104.472 86.364 104.736 ;
     RECT  85.489 104.736 86.316 104.76 ;
     RECT  85.489 104.76 86.364 105.072 ;
     RECT  85.489 105.072 86.316 105.096 ;
     RECT  85.489 105.096 86.364 105.36 ;
     RECT  85.489 105.36 86.316 105.384 ;
     RECT  85.489 105.384 86.364 105.696 ;
     RECT  85.489 105.696 86.316 105.72 ;
    LAYER M5 ;
     RECT  2.4 2.137 2.52 2.151 ;
     RECT  7.8 2.137 7.92 2.151 ;
     RECT  13.2 2.137 13.32 2.151 ;
     RECT  18.6 2.137 18.72 2.151 ;
     RECT  24 2.137 24.12 2.151 ;
     RECT  29.4 2.137 29.52 2.151 ;
     RECT  34.8 2.137 34.92 2.151 ;
     RECT  45.6 2.137 45.72 2.151 ;
     RECT  51 2.137 51.12 2.151 ;
     RECT  56.4 2.137 56.52 2.151 ;
     RECT  61.8 2.137 61.92 2.151 ;
     RECT  67.2 2.137 67.32 2.151 ;
     RECT  72.6 2.137 72.72 2.151 ;
     RECT  78 2.137 78.12 2.151 ;
     RECT  83.4 2.137 83.52 2.151 ;
     RECT  36.72 2.773 36.744 7.237 ;
     RECT  36.48 7.237 36.744 7.283 ;
     RECT  45.6 2.151 45.912 7.381 ;
     RECT  45.456 7.381 45.912 10.067 ;
     RECT  45.6 10.067 45.912 11.221 ;
     RECT  44.736 11.221 45.912 12.563 ;
     RECT  36.48 7.283 36.504 13.333 ;
     RECT  40.2 2.137 40.512 13.333 ;
     RECT  36.48 13.333 36.696 13.379 ;
     RECT  36.672 13.379 36.696 13.667 ;
     RECT  43.008 7.141 43.032 14.245 ;
     RECT  43.008 14.245 43.224 14.291 ;
     RECT  43.2 14.291 43.224 14.725 ;
     RECT  43.2 14.725 43.608 17.315 ;
     RECT  43.2 17.315 43.224 17.605 ;
     RECT  42.24 17.605 43.224 18.755 ;
     RECT  44.352 18.181 44.376 18.851 ;
     RECT  44.304 19.093 44.328 22.787 ;
     RECT  40.2 13.333 41.016 22.835 ;
     RECT  42.144 21.541 42.168 23.987 ;
     RECT  43.2 18.755 43.224 27.349 ;
     RECT  42.768 27.349 43.224 27.635 ;
     RECT  41.952 28.261 41.976 29.029 ;
     RECT  40.2 22.835 40.512 31.429 ;
     RECT  41.856 29.029 41.976 31.429 ;
     RECT  40.2 31.429 41.976 31.525 ;
     RECT  43.2 27.635 43.224 31.525 ;
     RECT  40.2 31.525 43.224 31.571 ;
     RECT  40.2 31.571 42.84 32.195 ;
     RECT  42.768 32.195 42.84 34.883 ;
     RECT  42.816 34.883 42.84 36.661 ;
     RECT  0.144 38.917 0.168 39.539 ;
     RECT  40.2 32.195 41.352 39.877 ;
     RECT  42.816 36.661 42.888 39.877 ;
     RECT  40.2 39.877 42.888 40.309 ;
     RECT  40.2 40.309 43.032 45.683 ;
     RECT  43.008 45.683 43.032 46.499 ;
     RECT  40.2 45.683 41.976 46.787 ;
     RECT  40.2 46.787 41.88 47.845 ;
     RECT  86.256 48.949 86.28 49.091 ;
     RECT  40.2 47.845 42.504 49.619 ;
     RECT  40.2 49.619 42.024 50.195 ;
     RECT  40.2 50.195 41.976 62.005 ;
     RECT  43.2 53.845 43.224 62.005 ;
     RECT  40.2 62.005 43.224 63.685 ;
     RECT  40.2 63.685 43.32 70.163 ;
     RECT  40.2 70.163 43.224 71.843 ;
     RECT  42.816 71.843 43.224 73.477 ;
     RECT  40.2 71.843 41.304 75.299 ;
     RECT  42.672 73.477 43.224 75.781 ;
     RECT  42.48 75.781 43.224 86.581 ;
     RECT  41.76 86.581 43.224 87.539 ;
     RECT  42.48 87.539 43.224 91.477 ;
     RECT  42.288 91.477 43.224 92.821 ;
     RECT  7.8 2.151 8.112 94.597 ;
     RECT  51 2.151 51.312 94.597 ;
     RECT  61.8 2.151 62.112 94.597 ;
     RECT  67.2 2.151 67.512 94.597 ;
     RECT  78 2.151 78.312 94.597 ;
     RECT  83.4 2.151 83.712 94.597 ;
     RECT  6.816 94.597 8.112 94.739 ;
     RECT  50.688 94.597 51.312 94.739 ;
     RECT  66.672 94.597 67.512 94.739 ;
     RECT  58.704 94.597 58.728 94.883 ;
     RECT  61.8 94.597 62.664 94.883 ;
     RECT  74.64 94.597 74.664 94.883 ;
     RECT  78 94.597 78.648 94.883 ;
     RECT  82.656 94.597 83.712 94.883 ;
     RECT  42.048 92.821 43.224 96.995 ;
     RECT  42.288 96.995 43.224 99.685 ;
     RECT  42.192 99.685 43.224 100.691 ;
     RECT  42.72 100.691 43.224 104.915 ;
     RECT  2.4 2.151 2.712 105.849 ;
     RECT  7.8 94.739 8.112 105.849 ;
     RECT  13.2 2.151 13.512 105.849 ;
     RECT  18.6 2.151 18.912 105.849 ;
     RECT  24 2.151 24.312 105.849 ;
     RECT  29.4 2.151 29.712 105.849 ;
     RECT  34.8 2.151 35.112 105.849 ;
     RECT  40.2 75.299 40.512 105.849 ;
     RECT  45.6 12.563 45.912 105.849 ;
     RECT  51 94.739 51.312 105.849 ;
     RECT  56.4 2.151 56.712 105.849 ;
     RECT  61.8 94.883 62.112 105.849 ;
     RECT  67.2 94.739 67.512 105.849 ;
     RECT  72.6 2.151 72.912 105.849 ;
     RECT  78 94.883 78.312 105.849 ;
     RECT  83.4 94.883 83.712 105.849 ;
     RECT  2.4 105.849 2.52 105.863 ;
     RECT  7.8 105.849 7.92 105.863 ;
     RECT  13.2 105.849 13.32 105.863 ;
     RECT  18.6 105.849 18.72 105.863 ;
     RECT  24 105.849 24.12 105.863 ;
     RECT  29.4 105.849 29.52 105.863 ;
     RECT  34.8 105.849 34.92 105.863 ;
     RECT  40.2 105.849 40.32 105.863 ;
     RECT  45.6 105.849 45.72 105.863 ;
     RECT  51 105.849 51.12 105.863 ;
     RECT  56.4 105.849 56.52 105.863 ;
     RECT  61.8 105.849 61.92 105.863 ;
     RECT  67.2 105.849 67.32 105.863 ;
     RECT  72.6 105.849 72.72 105.863 ;
     RECT  78 105.849 78.12 105.863 ;
     RECT  83.4 105.849 83.52 105.863 ;
     RECT  35.112 7.237 36.48 13.379 ;
     RECT  45.456 10.067 45.6 11.221 ;
     RECT  43.224 17.315 43.608 18.181 ;
     RECT  41.016 17.605 42.24 18.755 ;
     RECT  43.224 18.181 44.352 18.851 ;
     RECT  44.376 18.181 45.6 18.851 ;
     RECT  43.224 18.851 45.6 19.093 ;
     RECT  43.224 19.093 44.304 22.787 ;
     RECT  44.328 19.093 45.6 22.787 ;
     RECT  41.016 21.541 42.144 22.835 ;
     RECT  42.168 21.541 43.2 23.987 ;
     RECT  42.768 27.635 43.2 28.261 ;
     RECT  40.512 28.261 41.952 29.029 ;
     RECT  41.976 28.261 43.2 31.525 ;
     RECT  40.512 29.029 41.856 31.429 ;
     RECT  41.352 32.195 42.768 34.883 ;
     RECT  41.352 34.883 42.816 39.877 ;
     RECT  41.976 45.683 43.008 46.499 ;
     RECT  41.976 46.499 42.504 46.787 ;
     RECT  41.88 46.787 42.504 47.845 ;
     RECT  41.976 53.845 43.2 62.005 ;
     RECT  41.304 71.843 42.816 73.477 ;
     RECT  41.304 73.477 42.672 75.299 ;
     RECT  42.48 75.299 42.672 75.781 ;
     RECT  40.512 86.581 41.76 87.539 ;
  END
END ot_s81hd_lsc_r0m
END LIBRARY
